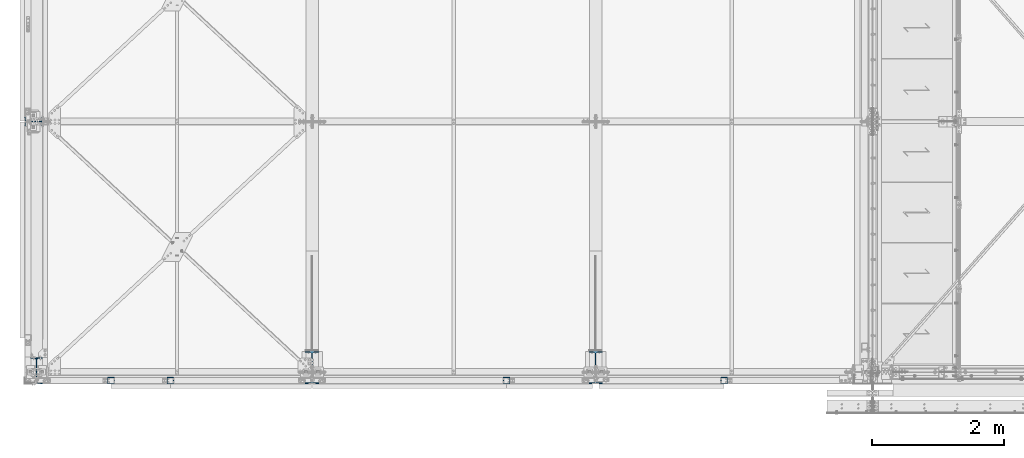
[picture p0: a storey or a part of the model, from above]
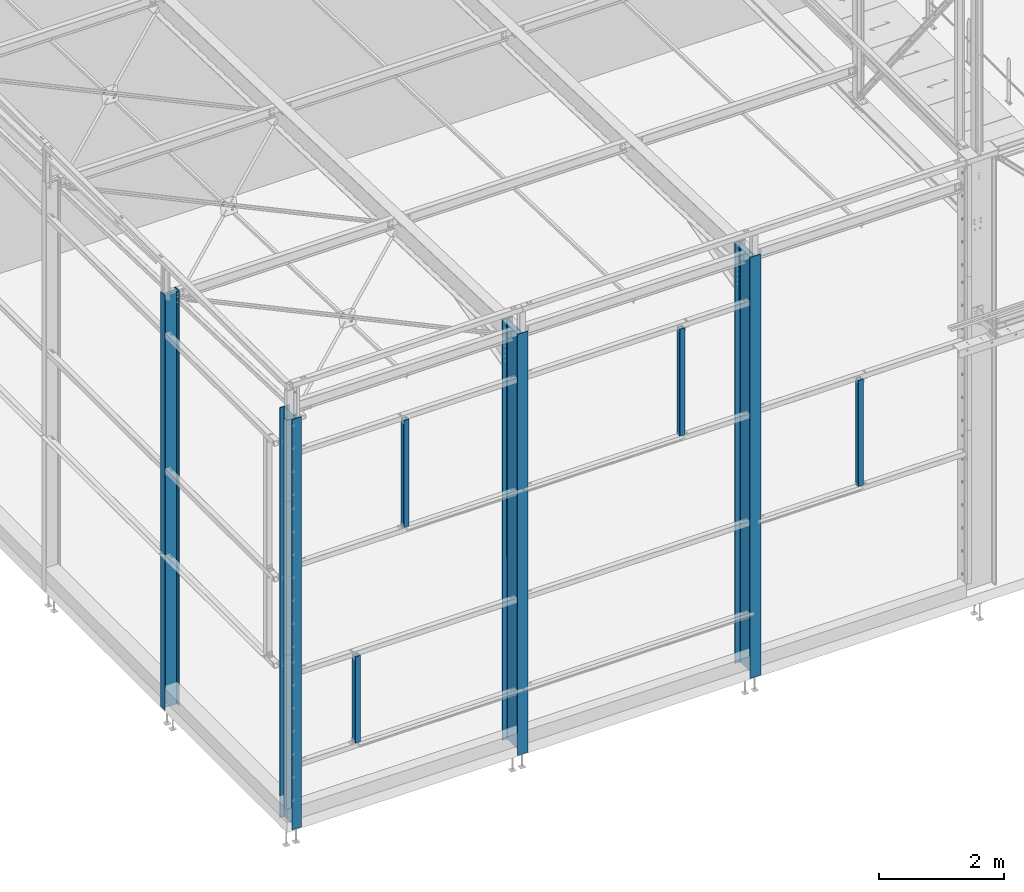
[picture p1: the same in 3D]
Properties of the parts of a building model (IFC2X3), part 1 of 4

# File
Description: ViewDefinition[CoordinationView_V2.0, QuantityTakeOffAddOnView], Option [BaseQuantities:On], Option [GridExport:Off], Option [Assemblies:On], Option [Bolts:On], Option [Rebars:On], Option [PourObjects:Off], Option [Welds:Off], Option [SurfaceTreatments:Off], Option [LocationBy:0], Option [ViewColors:On], Option [SectionedSpine:Off], Option [PropertySets:On], Option [Export all:On]
File name: Tekla.ifc
Time: 2021-06-01T16:03:29
Author: PORTCM01\professeur
Organization: Structural Designer
Written by: IFC Database Version: Work
Made in: Tekla Structures Educational 2019, IFC Export Version: 4.0.0.0 Mar 7 2019

# IfcSite, Undefined
RefElevation: 0 mm

# IfcBuildingStorey, Undefined
In: Undefined
Elevation: 0 mm

# IfcBeam: 250*200 (2)
In: Undefined
Description: 250*200; Material: CONCRETE/C25/30
Tekla Commun - Phase: 1; Profil: 250*200; Nom: POUTRE; sets with these values: 2
Tekla Quantités - Surface par tonne: 7.6 m2; Hauteur: 250 mm; Largeur: 200 mm; sets with these values: 2
Pset_BeamCommon - LoadBearing: no
Name | Repère de pièce = Repère d'assemblage = Reference | Poids (kg) = NetWeight (kg) | Volume (m3) | Surface supérieure totale (m2) | Surface nette (m2) | Longueur (mm) = Length (mm) | OuterSurfaceArea (m2) | NetVolume (m3)
POUTRE | Po9 | 1277.4 | 0.5 | 2.1 | 9.7 | 10645 | 9.6805 | 0.53225
POUTRE | Po8 | 1474.8 | 0.6 | 2.5 | 11.2 | 12290 | 11.161 | 0.6145

# IfcBeam: 250*270 (2)
In: Undefined
Description: 250*270; Material: CONCRETE/C25/30
Tekla Commun - Phase: 1; Profil: 250*270; Nom: POUTRE; sets with these values: 2
Tekla Quantités - Hauteur: 250 mm; Largeur: 270 mm; sets with these values: 2
Pset_BeamCommon - LoadBearing: no
Name | Repère de pièce = Repère d'assemblage = Reference | Poids (kg) | Volume (m3) | Surface supérieure totale (m2) | Surface par tonne (m2) | Surface nette (m2) | Longueur (mm) = Length (mm) | OuterSurfaceArea (m2) | NetVolume (m3) | NetWeight (kg)
POUTRE | Po11 | 2174.9 | 0.9 | 3.6 | 6.5 | 14.1 | 13425 | 14.097 | 0.906188 | 2174.85
POUTRE | Po10 | 81 | 0 | 0.1 | 8.1 | 0.7 | 500 | 0.655 | 0.03375 | 81

# IfcBeam: 4550*200 (2)
In: Undefined
Description: 4550*200; Material: CONCRETE/C25/30
Tekla Commun - Phase: 1; Profil: 4550*200; Nom: POUTRE; sets with these values: 2
Tekla Quantités - Hauteur: 4550 mm; Largeur: 200 mm; sets with these values: 2
Pset_BeamCommon - LoadBearing: no
Name | Repère de pièce = Repère d'assemblage = Reference | Poids (kg) = NetWeight (kg) | Volume (m3) | Surface supérieure totale (m2) | Surface par tonne (m2) | Surface nette (m2) | Longueur (mm) | Length (mm) | OuterSurfaceArea (m2) | NetVolume (m3)
POUTRE | Po5 | 29791.9 | 12.4 | 2.7 | 4.4 | 131.7 | 13733.4 | 13733.4 | 131.739 | 12.4133
POUTRE | Po4 | 20476.6 | 8.5 | 1.9 | 4.5 | 91.2 | 9478.7 | 9478.66 | 91.2034 | 8.53192

# IfcBeam: 8550*200 (5)
In: Undefined
Description: 8550*200; Material: CONCRETE/C25/30
Tekla Commun - Phase: 1; Profil: 8550*200; Nom: POUTRE; sets with these values: 2
Tekla Quantités - Hauteur: 8550 mm; Largeur: 200 mm; sets with these values: 2
Pset_BeamCommon - LoadBearing: no
Name | Repère de pièce = Repère d'assemblage = Reference | Poids (kg) = NetWeight (kg) | Volume (m3) | Surface supérieure totale (m2) | Surface par tonne (m2) | Surface nette (m2) | Longueur (mm) = Length (mm) | OuterSurfaceArea (m2) | NetVolume (m3)
POUTRE | Po7 | 37962 | 15.8 | 1.9 | 4.4 | 165.3 | 9250 | 165.295 | 15.8175
POUTRE | Po6 | 38372.4 | 16 | 1.9 | 4.4 | 167.8 | 9450 | 167.753 | 15.9885
POUTRE | Po3 | 124128 | 51.7 | 6.9 | 4.4 | 547.8 | 34778 | 547.813 | 51.7201
POUTRE | Po2 | 38782.8 | 16.2 | 1.9 | 4.4 | 170.2 | 9650 | 170.212 | 16.1595
POUTRE | Po1 | 201274 | 83.9 | 9.4 | 4.3 | 862.8 | 49248 | 862.765 | 83.8642

# IfcBeam: B140/150 (18)
In: Undefined
Description: B140/150; Material: Undefined/S235-E24
Tekla Commun - Repère de pièce: PN35; Repère d'assemblage: PN35; Phase: 1; Profil: B140/150; Nom: PANNE SHED; sets with these values: 2
Tekla Quantités - Poids: 0 kg; Volume: 0 m3; Surface supérieure totale: 0 m2; Surface par tonne: 0 m2; Surface nette: 4.6 m2; Hauteur: 140 mm; Largeur: 56 mm; Longueur: 7750 mm; sets with these values: 2
Pset_BeamCommon - LoadBearing: no; Reference: PN35
BaseQuantities - Length: 7750 mm; OuterSurfaceArea: 0.00000456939 m2; NetVolume: 0.00341 m3; NetWeight: 0 kg

# IfcBeam: D22 (22)
In: Undefined
Description: D22; Material: Undefined/S235-E24
Tekla Commun - Repère de pièce: 210; Phase: 1; Profil: D22; Nom: TIGE D'ANCRAGE; sets with these values: 2
Tekla Quantités - Poids: 0 kg; Volume: 0 m3; Surface supérieure totale: 0 m2; Surface par tonne: 0 m2; Surface nette: 0 m2; Hauteur: 22 mm; Largeur: 22 mm; Longueur: 350 mm; sets with these values: 2
Pset_BeamCommon - LoadBearing: no; Reference: 210
BaseQuantities - Length: 350 mm; OuterSurfaceArea: 0.0246409 m2; NetVolume: 0.00012705 m3; NetWeight: 0 kg
Name | Repère d'assemblage
14 x TIGE D'ANCRAGE | PS1
8 x TIGE D'ANCRAGE | PS2

# IfcBeam: D24 (22)
In: Undefined
Description: D24; Material: Undefined/S235-E24
Tekla Commun - Repère de pièce: 218; Phase: 1; Profil: D24; Nom: TIGE D'ANCRAGE; sets with these values: 2
Tekla Quantités - Poids: 0 kg; Volume: 0 m3; Surface supérieure totale: 0 m2; Surface par tonne: 0 m2; Surface nette: 0 m2; Hauteur: 24 mm; Largeur: 24 mm; Longueur: 150 mm; sets with these values: 2
Pset_BeamCommon - LoadBearing: no; Reference: 218
BaseQuantities - Length: 150 mm; OuterSurfaceArea: 0.012045 m2; NetVolume: 0.0000648 m3; NetWeight: 0 kg
Name | Repère d'assemblage
14 x TIGE D'ANCRAGE | PS1
8 x TIGE D'ANCRAGE | PS2

# IfcBeam: HEA100, BECHE
In: Undefined
Description: HEA100; Material: Undefined/S275-E28
Tekla Commun - Repère de pièce: 200; Repère d'assemblage: PS3; Phase: 1; Profil: HEA100; Nom: BECHE; sets with these values: 2
Tekla Quantités - Poids: 0 kg; Volume: 0 m3; Surface supérieure totale: 0 m2; Surface par tonne: 0 m2; Surface nette: 0.1 m2; Hauteur: 96 mm; Largeur: 100 mm; Longueur: 100 mm; sets with these values: 2
Pset_BeamCommon - LoadBearing: no; Reference: 200
BaseQuantities - Length: 100 mm; OuterSurfaceArea: 0.0561 m2; NetVolume: 0.0002 m3; NetWeight: 0 kg

# IfcBeam: HEA120 (4)
In: Undefined
Description: HEA120; Material: Undefined/S275-E28
Tekla Commun - Repère de pièce: 201; Repère d'assemblage: PS2; Phase: 1; Profil: HEA120; Nom: BECHE; sets with these values: 2
Tekla Quantités - Poids: 0 kg; Volume: 0 m3; Surface supérieure totale: 0 m2; Surface par tonne: 0 m2; Surface nette: 0.1 m2; Hauteur: 114 mm; Largeur: 120 mm; Longueur: 120 mm; sets with these values: 2
Pset_BeamCommon - LoadBearing: no; Reference: 201
BaseQuantities - Length: 120 mm; OuterSurfaceArea: 0.08124 m2; NetVolume: 0.0002892 m3; NetWeight: 0 kg

# IfcBeam: HEA140 (27)
In: Undefined
Description: HEA140; Material: Undefined/S275-E28
Tekla Commun - Phase: 1; Profil: HEA140; sets with these values: 2
Tekla Quantités - Poids: 0 kg; Volume: 0 m3; Surface par tonne: 0 m2; Hauteur: 133 mm; Largeur: 140 mm; sets with these values: 2
Pset_BeamCommon - LoadBearing: no
BaseQuantities - NetWeight: 0 kg
Name | Repère de pièce = Reference | Repère d'assemblage | Nom | Surface supérieure totale (m2) | Surface nette (m2) | Longueur (mm) = Length (mm) | OuterSurfaceArea (m2) | NetVolume (m3)
LONGERON | L43 | L43 | LONGERON | 0.5 | 2.8 | 3465 | 2.75121 | 0.0104574
12 x LONGERON | L3 | L3 | LONGERON | 0.5 | 3 | 3650 | 2.8981 | 0.0110157
6 x BECHE | 32 | PS6 | BECHE | 0 | 0.1 | 100 | 0.0794 | 0.0003018
BECHE | 33 | PS5 | BECHE | 0 | 0.1 | 125 | 0.09925 | 0.00037725
6 x BECHE | 32 | PS4 | BECHE | 0 | 0.1 | 100 | 0.0794 | 0.0003018
LONGERON | L32 | L32 | LONGERON | 1.6 | 9.4 | 11545 | 9.16673 | 0.0348428

# IfcBeam: HEA180 (2)
In: Undefined
Description: HEA180; Material: Undefined/S275-E28
Tekla Commun - Phase: 1; Profil: HEA180; Nom: LONGERON; sets with these values: 2
Tekla Quantités - Poids: 0 kg; Surface par tonne: 0 m2; Hauteur: 171 mm; Largeur: 180 mm; sets with these values: 2
Pset_BeamCommon - LoadBearing: no
BaseQuantities - NetWeight: 0 kg
Name | Repère de pièce = Repère d'assemblage = Reference | Volume (m3) | Surface supérieure totale (m2) | Surface nette (m2) | Longueur (mm) = Length (mm) | OuterSurfaceArea (m2) | NetVolume (m3)
LONGERON | L42 | 0 | 0.7 | 3.9 | 3690 | 3.77856 | 0.0159851
LONGERON | L40 | 0.1 | 2.1 | 12.1 | 11545 | 11.8221 | 0.0500129

# IfcBeam: HEA200 (6)
In: Undefined
Description: HEA200; Material: Undefined/S275-E28
Tekla Commun - Phase: 1; Profil: HEA200; sets with these values: 2
Tekla Quantités - Poids: 0 kg; Surface par tonne: 0 m2; Hauteur: 190 mm; Largeur: 200 mm; sets with these values: 2
Pset_BeamCommon - LoadBearing: no
BaseQuantities - NetWeight: 0 kg
Name | Repère de pièce = Repère d'assemblage = Reference | Nom | Volume (m3) | Surface supérieure totale (m2) | Surface nette (m2) | Longueur (mm) = Length (mm) | OuterSurfaceArea (m2) | NetVolume (m3)
LONGERON | L41 | LONGERON | 0 | 0.8 | 4.4 | 3765 | 4.27704 | 0.0192203
TRAVERSE HAUTE | TH2 | TRAVERSE HAUTE | 0 | 1.7 | 9.9 | 8515 | 9.67304 | 0.0434691
TRAVERSE BASSE | TB2 | TRAVERSE BASSE | 0 | 1.4 | 8.2 | 7055 | 8.01448 | 0.0360158
TRAVERSE HAUTE | TH1 | TRAVERSE HAUTE | 0 | 1.4 | 8.2 | 7055 | 8.01448 | 0.0360158
TRAVERSE BASSE | TB1 | TRAVERSE BASSE | 0 | 1.7 | 9.9 | 8515 | 9.67304 | 0.0434691
LONGERON | L39 | LONGERON | 0.1 | 2.3 | 13.5 | 11545 | 13.1151 | 0.0589372

# IfcBeam: IPE120 (7)
In: Undefined
Description: IPE120; Material: Undefined/S275-E28
Tekla Commun - Profil: IPE120; Nom: PANNE; sets with these values: 2
Tekla Quantités - Poids: 0 kg; Volume: 0 m3; Surface supérieure totale: 0 m2; Surface par tonne: 0 m2; Hauteur: 120 mm; Largeur: 64 mm; sets with these values: 2
Pset_BeamCommon - LoadBearing: no
BaseQuantities - NetWeight: 0 kg
Name | Repère de pièce = Repère d'assemblage = Reference | Phase | Surface nette (m2) | Longueur (mm) = Length (mm) | OuterSurfaceArea (m2) | NetVolume (m3)
PANNE | PN37 | 2 | 5.2 | 10758 | 5.11005 | 0.0137591 | Tekla Commun - Finition: GALVA
PANNE | PN36 | 2 | 5.2 | 10758 | 5.11005 | 0.0137591 | Tekla Commun - Finition: GALVA
PANNE | PN11 | 2 | 5.2 | 10758 | 5.11005 | 0.0137591 | Tekla Commun - Finition: GALVA
PANNE | PN18 | 1 | 0.6 | 1125 | 0.534375 | 0.00143883
3 x PANNE | PN10 | 1 | 0.6 | 1125 | 0.534375 | 0.00143883

# IfcBeam: IPE160 (4)
In: Undefined
Description: IPE160; Material: Undefined/S275-E28
Tekla Commun - Finition: GALVA; Phase: 2; Profil: IPE160; Nom: TRAVERSE; sets with these values: 2
Tekla Quantités - Poids: 0 kg; Volume: 0 m3; Surface supérieure totale: 0 m2; Surface par tonne: 0 m2; Surface nette: 2.6 m2; Hauteur: 160 mm; Largeur: 82 mm; Longueur: 4043.9 mm; sets with these values: 2
Pset_BeamCommon - LoadBearing: no
BaseQuantities - Length: 4043.91 mm; OuterSurfaceArea: 2.51935 m2; NetVolume: 0.0078273 m3; NetWeight: 0 kg
Name | Repère de pièce = Repère d'assemblage = Reference
2 x TRAVERSE | T8
TRAVERSE | T6
TRAVERSE | T9

# IfcBeam: IPE180 (5)
In: Undefined
Description: IPE180; Material: Undefined/S275-E28
Tekla Commun - Phase: 1; Profil: IPE180; Nom: PANNE; sets with these values: 2
Tekla Quantités - Poids: 0 kg; Volume: 0 m3; Surface supérieure totale: 0 m2; Surface par tonne: 0 m2; Hauteur: 180 mm; Largeur: 91 mm; sets with these values: 2
Pset_BeamCommon - LoadBearing: no
BaseQuantities - NetWeight: 0 kg
Name | Repère de pièce = Repère d'assemblage = Reference | Surface nette (m2) | Longueur (mm) = Length (mm) | OuterSurfaceArea (m2) | NetVolume (m3)
3 x PANNE | PN16 | 2.7 | 3733.5 | 2.60598 | 0.00868113
PANNE | PN17 | 2.7 | 3733.5 | 2.60598 | 0.00868113
PANNE | PN2 | 2.8 | 3866.5 | 2.69882 | 0.00899039

# IfcBeam: IPE200 (20)
In: Undefined
Description: IPE200
Tekla Commun - Phase: 1; Profil: IPE200; Nom: PANNE; sets with these values: 2
Tekla Quantités - Volume: 0 m3; Surface supérieure totale: 0 m2; Hauteur: 200 mm; Largeur: 100 mm; sets with these values: 2
Pset_BeamCommon - LoadBearing: no
Name | Material | Repère de pièce = Repère d'assemblage = Reference | Poids (kg) | Surface par tonne (m2) | Surface nette (m2) | Longueur (mm) = Length (mm) | OuterSurfaceArea (m2) | NetVolume (m3) | NetWeight (kg)
3 x PANNE | Undefined/S275-E28 | PN9 | 0 | 0 | 4.1 | 5213.5 | 4.00397 | 0.0142057 | 0
PANNE | Undefined/S275-E28 | PN15 | 0 | 0 | 4.1 | 5213.5 | 4.00397 | 0.0142057 | 0
PANNE | Undefined/S275-E28 | PN8 | 0 | 0 | 4 | 5075 | 3.8976 | 0.0138284 | 0
2 x PANNE | Undefined/S275-E28 | PN7 | 0 | 0 | 3.2 | 4023.5 | 3.09005 | 0.0109632 | 0
2 x PANNE | Undefined/S275-E28 | PN5 | 0 | 0 | 3.2 | 4100 | 3.1488 | 0.0111717 | 0
2 x PANNE | Undefined/S275-E28 | PN14 | 0 | 0 | 3.2 | 4023.5 | 3.09005 | 0.0109632 | 0
3 x PANNE | Undefined/S275-E28 | PN13 | 0 | 0 | 3.2 | 4100 | 3.1488 | 0.0111717 | 0
PANNE | Undefined/S275-E28 | PN6 | 0 | 0 | 3 | 3790 | 2.91072 | 0.010327 | 0
3 x PANNE | Undefined/S275-E28 | PN4 | 0 | 0 | 3.1 | 3980 | 3.05664 | 0.0108447 | 0
PANNE | Undefined/S275-E28 | PN3 | 0 | 0 | 3.3 | 4165 | 3.19872 | 0.0113488 | 0
PANNE | STEEL/S235J0 | PN12 | 93.2 | 34.3 | 3.3 | 4165 | 3.19872 | 0.0113488 | 89.088

# IfcBeam: IPE270 (2)
In: Undefined
Description: IPE270; Material: Undefined/S275-E28
Tekla Commun - Phase: 1; Profil: IPE270; sets with these values: 2
Tekla Quantités - Poids: 0 kg; Surface supérieure totale: 0 m2; Surface par tonne: 0 m2; Hauteur: 270 mm; Largeur: 135 mm; sets with these values: 2
Pset_BeamCommon - LoadBearing: no
BaseQuantities - NetWeight: 0 kg
Name | Repère de pièce = Reference | Repère d'assemblage | Nom | Volume (m3) | Surface nette (m2) | Longueur (mm) = Length (mm) | OuterSurfaceArea (m2) | NetVolume (m3)
PANNE | PN1 | PN1 | PANNE | 0 | 5.6 | 5260 | 5.47566 | 0.0231512
TRAVERSE | 11 | T3 | TRAVERSE | 0.1 | 16 | 15040.9 | 15.6576 | 0.0661631

# IfcBeam: IPE450 (3)
In: Undefined
Description: IPE450; Material: Undefined/S275-E28
Tekla Commun - Phase: 1; Profil: IPE450; Nom: TRAVERSE; sets with these values: 2
Tekla Quantités - Poids: 0 kg; Surface supérieure totale: 0 m2; Surface par tonne: 0 m2; Hauteur: 450 mm; Largeur: 190 mm; sets with these values: 2
Pset_BeamCommon - LoadBearing: no
BaseQuantities - NetWeight: 0 kg
Name | Repère de pièce = Reference | Repère d'assemblage | Volume (m3) | Surface nette (m2) | Longueur (mm) = Length (mm) | OuterSurfaceArea (m2) | NetVolume (m3)
TRAVERSE | 155 | T7 | 0.1 | 24.7 | 15046.6 | 24.1497 | 0.142861
TRAVERSE | T2 | T2 | 0.2 | 25.1 | 15291.1 | 24.5422 | 0.145252
TRAVERSE | 6 | T1 | 0.1 | 24.7 | 15046.6 | 24.1497 | 0.142861

# IfcBeam: IPE550 (2)
In: Undefined
Description: IPE550; Material: Undefined/S275-E28
Tekla Commun - Phase: 1; Profil: IPE550; Nom: TRAVERSE; sets with these values: 2
Tekla Quantités - Poids: 0 kg; Volume: 0.2 m3; Surface supérieure totale: 0 m2; Surface par tonne: 0 m2; Hauteur: 550 mm; Largeur: 210 mm; sets with these values: 2
Pset_BeamCommon - LoadBearing: no
BaseQuantities - NetWeight: 0 kg
Name | Repère de pièce = Reference | Repère d'assemblage | Surface nette (m2) | Longueur (mm) = Length (mm) | OuterSurfaceArea (m2) | NetVolume (m3)
TRAVERSE | 36 | T5 | 29.3 | 15264.8 | 28.652 | 0.197412
TRAVERSE | 35 | T4 | 29.4 | 15353.9 | 28.8192 | 0.198565

# IfcBeam: L100*10 (19)
In: Undefined
Description: L100*10; Material: Undefined/S235-E24
Tekla Commun - Phase: 1; Profil: L100*10; Nom: ATTACHE; sets with these values: 2
Tekla Quantités - Poids: 0 kg; Volume: 0 m3; Surface supérieure totale: 0 m2; Surface par tonne: 0 m2; Surface nette: 0.1 m2; Hauteur: 100 mm; Largeur: 100 mm; sets with these values: 2
Pset_BeamCommon - LoadBearing: no
BaseQuantities - NetWeight: 0 kg
Name | Repère de pièce = Reference | Repère d'assemblage | Longueur (mm) = Length (mm) | OuterSurfaceArea (m2) | NetVolume (m3)
ATTACHE | A24 | A24 | 200 | 0.078 | 0.00038
ATTACHE | A23 | A23 | 120 | 0.0468 | 0.000228
4 x ATTACHE | A19 | A19 | 200 | 0.078 | 0.00038
5 x ATTACHE | A22 | A22 | 130 | 0.0507 | 0.000247
ATTACHE | 347 | A21 | 200 | 0.078 | 0.00038
ATTACHE | 347 | A20 | 200 | 0.078 | 0.00038
2 x ATTACHE | A10 | A10 | 280 | 0.1092 | 0.000532
3 x ATTACHE | A11 | A11 | 240 | 0.0936 | 0.000456
ATTACHE | A9 | A9 | 180 | 0.0702 | 0.000342

# IfcBeam: L150*15 (10)
In: Undefined
Description: L150*15; Material: Undefined/S235-E24
Tekla Commun - Repère de pièce: A1; Repère d'assemblage: A1; Phase: 1; Profil: L150*15; Nom: ATTACHE; sets with these values: 2
Tekla Quantités - Poids: 0 kg; Volume: 0 m3; Surface supérieure totale: 0 m2; Surface par tonne: 0 m2; Surface nette: 0.1 m2; Hauteur: 150 mm; Largeur: 150 mm; Longueur: 200 mm; sets with these values: 2
Pset_BeamCommon - LoadBearing: no; Reference: A1
BaseQuantities - Length: 200 mm; OuterSurfaceArea: 0.1172 m2; NetVolume: 0.000855 m3; NetWeight: 0 kg

# IfcBeam: L200*100*10 (87)
In: Undefined
Description: L200*100*10; Material: Undefined/S235-E24
Tekla Commun - Phase: 1; Profil: L200*100*10; Nom: ATTACHE; sets with these values: 2
Tekla Quantités - Poids: 0 kg; Volume: 0 m3; Surface supérieure totale: 0 m2; Surface par tonne: 0 m2; sets with these values: 2
Pset_BeamCommon - LoadBearing: no
BaseQuantities - NetWeight: 0 kg
Name | Repère de pièce = Repère d'assemblage = Reference | Surface nette (m2) | Hauteur (mm) | Largeur (mm) | Longueur (mm) = Length (mm) | OuterSurfaceArea (m2) | NetVolume (m3)
ATTACHE | A52 | 0.1 | 150 | 100 | 100 | 0.0587 | 0.00024
ATTACHE | A50 | 0.1 | 200 | 100 | 110 | 0.06457 | 0.000319
35 x ATTACHE | A46 | 0 | 200 | 100 | 60 | 0.03522 | 0.000174
ATTACHE | A49 | 0 | 192 | 100 | 60 | 0.03522 | 0.0001692
ATTACHE | A48 | 0 | 171 | 100 | 60 | 0.03522 | 0.0001566
ATTACHE | A47 | 0.1 | 200 | 100 | 110 | 0.06457 | 0.000319
2 x ATTACHE | A56 | 0.1 | 200 | 100 | 100 | 0.0587 | 0.00029
2 x ATTACHE | A57 | 0.1 | 200 | 70 | 100 | 0.0587 | 0.00026
ATTACHE | A51 | 0.1 | 200 | 100 | 80 | 0.04696 | 0.000232
42 x ATTACHE | A44 | 0 | 200 | 100 | 60 | 0.03522 | 0.000174

# IfcBeam: L40*4 (7)
In: Undefined
Description: L40*4; Material: Undefined/S235-E24
Tekla Commun - Profil: L40*4; sets with these values: 2
Tekla Quantités - Poids: 0 kg; Volume: 0 m3; Surface supérieure totale: 0 m2; Surface par tonne: 0 m2; Hauteur: 40 mm; Largeur: 40 mm; sets with these values: 2
Pset_BeamCommon - LoadBearing: no
BaseQuantities - NetWeight: 0 kg
Name | Finition | Repère de pièce = Repère d'assemblage = Reference | Phase | Nom | Surface nette (m2) | Longueur (mm) | Length (mm) | OuterSurfaceArea (m2) | NetVolume (m3)
4 x STABILITE CVT | GALVA | S15 | 2 | STABILITE CVT | 0.4 | 2209.6 | 2209.65 | 0.342495 | 0.000672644
3 x ATTACHE |  | A14 | 1 | ATTACHE | 0 | 120 | 120 | 0.0186 | 0.00003648

# IfcBeam: L50*5 (64)
In: Undefined
Description: L50*5
Tekla Commun - Profil: L50*5; sets with these values: 2
Tekla Quantités - Poids: 0 kg; Volume: 0 m3; Surface par tonne: 0 m2; Hauteur: 50 mm; Largeur: 50 mm; sets with these values: 2
Pset_BeamCommon - LoadBearing: no
BaseQuantities - NetWeight: 0 kg
Name | Material | Repère de pièce = Reference | Repère d'assemblage | Phase | Nom | Surface supérieure totale (m2) | Surface nette (m2) | Longueur (mm) | Length (mm) | OuterSurfaceArea (m2) | NetVolume (m3)
SUPPORT | Undefined/S235-E24 | S51 | S51 | 3 | SUPPORT | 0.3 | 1.1 | 5660 | 5660 | 1.09804 | 0.0026885 | Tekla Commun - Finition: GALVA
SUPPORT | Undefined/S235-E24 | S33 | S33 | 3 | SUPPORT | 0.3 | 1.1 | 5600 | 5600 | 1.0864 | 0.00266 | Tekla Commun - Finition: GALVA
3 x SUPPORT | Undefined/S235-E24 | S54 | S54 | 3 | SUPPORT | 0 | 0.1 | 705 | 705 | 0.13677 | 0.000334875 | Tekla Commun - Finition: GALVA
3 x SUPPORT | Undefined/S235-E24 | S53 | S53 | 3 | SUPPORT | 0 | 0.1 | 705 | 705 | 0.13677 | 0.000334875 | Tekla Commun - Finition: GALVA
SUPPORT | Undefined/S235-E24 | S25 | S25 | 3 | SUPPORT | 0.3 | 1.1 | 5660 | 5660 | 1.09804 | 0.0026885 | Tekla Commun - Finition: GALVA
4 x SUPPORT | Undefined/S235-E24 | S35 | S35 | 3 | SUPPORT | 0.1 | 0.4 | 2010 | 2010 | 0.38994 | 0.00095475 | Tekla Commun - Finition: GALVA
2 x SUPPORT | Undefined/S235-E24 | S52 | S52 | 3 | SUPPORT | 0 | 0.2 | 960 | 959.999 | 0.18624 | 0.000456 | Tekla Commun - Finition: GALVA
2 x SUPPORT | Undefined/S235-E24 | S36 | S36 | 3 | SUPPORT | 0 | 0.2 | 840 | 840 | 0.16296 | 0.000399 | Tekla Commun - Finition: GALVA
SUPPORT | Undefined/S235-E24 | S41 | S41 | 3 | SUPPORT | 0.3 | 1.1 | 5600 | 5600 | 1.0864 | 0.00266 | Tekla Commun - Finition: GALVA
2 x LIERNE | Undefined/S235-E24 | L79 | L79 | 1 | LIERNE | 0 | 0.8 | 3874.7 | 3874.7 | 0.751691 | 0.00184143
2 x LIERNE | Undefined/S235-E24 | L78 | L78 | 1 | LIERNE | 0 | 0.9 | 4309.7 | 4309.66 | 0.836074 | 0.00204804
LIERNE | Undefined/S235-E24 | L83 | L83 | 1 | LIERNE | 0 | 1.5 | 7646.8 | 7646.75 | 1.48347 | 0.00363316
3 x LIERNE | Undefined/S235-E24 | L80 | L80 | 1 | LIERNE | 0 | 1.5 | 7646.8 | 7646.75 | 1.48347 | 0.00363316
LIERNE | Undefined/S235-E24 | L82 | L82 | 1 | LIERNE | 0 | 1.5 | 7642.3 | 7642.25 | 1.4826 | 0.00363102
LIERNE | Undefined/S235-E24 | L81 | L81 | 1 | LIERNE | 0 | 1.5 | 7400 | 7399.96 | 1.43559 | 0.00351593
STABILITE CVT | Undefined/S235-E24 | S39 | S39 | 1 | STABILITE CVT | 0 | 0.5 | 2596.8 | 2596.85 | 0.503789 | 0.00123493
STABILITE CVT | Undefined/S235-E24 | S40 | S40 | 1 | STABILITE CVT | 0 | 0.5 | 2535 | 2535.02 | 0.491794 | 0.00120556
2 x LIERNE | Undefined/S235-E24 | L84 | L84 | 1 | LIERNE | 0 | 1.5 | 7646.8 | 7646.75 | 1.48347 | 0.00363316
5 x STABILITE CVT | Undefined/S235-E24 | S9 | S9 | 1 | STABILITE CVT | 0 | 0.5 | 2519.7 | 2519.71 | 0.488823 | 0.00119829
LIERNE | Undefined/S235-E24 | L86 | L86 | 1 | LIERNE | 0 | 1.5 | 7646.8 | 7646.75 | 1.48347 | 0.00363316
LIERNE | Undefined/S235-E24 | L85 | L85 | 1 | LIERNE | 0 | 1.5 | 7646.8 | 7646.75 | 1.48347 | 0.00363316
2 x STABILITE CVT | Undefined/S235-E24 | S38 | S38 | 1 | STABILITE CVT | 0 | 1.1 | 5256.2 | 5256.19 | 1.0197 | 0.00249812
2 x STABILITE CVT | Undefined/S235-E24 | S9 | S9 | 1 | STABILITE CVT | 0 | 0.5 | 2519.7 | 2519.7 | 0.488822 | 0.00119828
3 x SUPPORT | Undefined/S235-E24 | S37 | S37 | 1 | SUPPORT | 0.4 | 1.5 | 7470 | 7470 | 1.44918 | 0.00354825
3 x SUPPORT | Undefined/S235-E24 | S13 | S13 | 1 | SUPPORT | 0.4 | 1.5 | 7675 | 7675 | 1.48895 | 0.00364563
8 x STABILITE CVT | Undefined/S235-E24 | S8 | S8 | 1 | STABILITE CVT | 0 | 0.8 | 4071 | 4071.04 | 0.789781 | 0.00193469
STABILITE CVT | Undefined/S235-E24 | S40 | S40 | 1 | STABILITE CVT | 0 | 0.5 | 2535 | 2535.03 | 0.491796 | 0.00120556
STABILITE CVT | Undefined/S235-E24 | S12 | S12 | 1 | STABILITE CVT | 0 | 1.1 | 5283.1 | 5283.05 | 1.02491 | 0.00251087
STABILITE CVT | Undefined/S235-E24 | S39 | S39 | 1 | STABILITE CVT | 0 | 0.5 | 2596.9 | 2596.86 | 0.50379 | 0.00123493
STABILITE CVT | Undefined/S235-E24 | S11 | S11 | 1 | STABILITE CVT | 0 | 1.1 | 5406.7 | 5406.7 | 1.0489 | 0.00256961
STABILITE CVT | Undefined/S235-E24 | S38 | S38 | 1 | STABILITE CVT | 0 | 1.1 | 5256.2 | 5256.19 | 1.0197 | 0.00249811
STABILITE CVT | Undefined/S235-E24 | S9 | S9 | 1 | STABILITE CVT | 0 | 0.5 | 2519.7 | 2519.69 | 0.488821 | 0.00119828
STABILITE CVT | STEEL/S235 -------------- | S38 | S38(?) | 1 | STABILITE CVT | 0 | 1.1 | 5311.3 | 5311.31 | 1.03039 | 0.00252429

# IfcBeam: L60*5 (2)
In: Undefined
Description: L60*5; Material: STEEL/S235 --------------
Tekla Commun - Repère de pièce: S0; Repère d'assemblage: S0(?); Phase: 1; Profil: L60*5; Nom: CORNIERE; sets with these values: 2
Tekla Quantités - Poids: 0 kg; Volume: 0 m3; Surface supérieure totale: 0 m2; Surface par tonne: 0 m2; Surface nette: 0 m2; Hauteur: 60 mm; Largeur: 60 mm; sets with these values: 2
Pset_BeamCommon - LoadBearing: no; Reference: S0
BaseQuantities - NetWeight: 0 kg
Name | Longueur (mm) | Length (mm) | OuterSurfaceArea (m2) | NetVolume (m3)
CORNIERE | 107 | 106.997 | 0.0249304 | 0.0000632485
CORNIERE | 107.2 | 107.192 | 0.0249758 | 0.0000633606

# IfcBeam: L60*6 (59)
In: Undefined
Description: L60*6; Material: Undefined/S235-E24
Tekla Commun - Profil: L60*6; sets with these values: 2
Tekla Quantités - Poids: 0 kg; Volume: 0 m3; Surface supérieure totale: 0 m2; Surface par tonne: 0 m2; Hauteur: 60 mm; Largeur: 60 mm; sets with these values: 2
Pset_BeamCommon - LoadBearing: no
BaseQuantities - NetWeight: 0 kg
Name | Repère de pièce = Repère d'assemblage = Reference | Phase | Nom | Surface nette (m2) | Longueur (mm) | Length (mm) | OuterSurfaceArea (m2) | NetVolume (m3)
14 x ATTACHE | A29 | 3 | ATTACHE | 0 | 120 | 120 | 0.02796 | 0.00008208 | Tekla Commun - Finition: GALVA
2 x ATTACHE | A45 | 3 | ATTACHE | 0 | 180 | 180 | 0.04194 | 0.00012312 | Tekla Commun - Finition: GALVA
3 x ATTACHE | A26 | 1 | ATTACHE | 0 | 150 | 150 | 0.03495 | 0.0001026
5 x STABILITE CVT | S7 | 1 | STABILITE CVT | 1.1 | 4471.9 | 4471.95 | 1.04196 | 0.00306018
3 x STABILITE CVT | S7 | 1 | STABILITE CVT | 1.1 | 4472 | 4471.95 | 1.04196 | 0.00306018
7 x STABILITE CVT | S6 | 1 | STABILITE CVT | 1.2 | 5017.9 | 5017.95 | 1.16918 | 0.00343364
16 x ATTACHE | A25 | 1 | ATTACHE | 0 | 200 | 200 | 0.0466 | 0.0001368
6 x STABILITE CVT | S30 | 1 | STABILITE CVT | 0.8 | 3399.5 | 3399.54 | 0.792092 | 0.00232734
2 x STABILITE CVT | S31 | 1 | STABILITE CVT | 0.8 | 3279.5 | 3279.54 | 0.764132 | 0.00224525
STABILITE CVT | S6 | 1 | STABILITE CVT | 1.2 | 5017.9 | 5017.94 | 1.16918 | 0.00343364

# IfcBeam: L70*7 (66)
In: Undefined
Description: L70*7; Material: Undefined/S235-E24
Tekla Commun - Phase: 1; Profil: L70*7; sets with these values: 2
Tekla Quantités - Poids: 0 kg; Volume: 0 m3; Surface par tonne: 0 m2; Hauteur: 70 mm; Largeur: 70 mm; sets with these values: 2
Pset_BeamCommon - LoadBearing: no
BaseQuantities - NetWeight: 0 kg
Name | Repère de pièce = Reference | Repère d'assemblage | Nom | Surface supérieure totale (m2) | Surface nette (m2) | Longueur (mm) | Length (mm) | OuterSurfaceArea (m2) | NetVolume (m3)
SUPPORT | S10 | S10 | SUPPORT | 0 | 1.9 | 6735 | 6735 | 1.83192 | 0.00627028
SUPPORT | S32 | S32 | SUPPORT | 0.1 | 2.3 | 8195 | 8195 | 2.22904 | 0.00762954
SUPPORT | 495 | L25 | SUPPORT | 0.2 | 0.6 | 2155 | 2155 | 0.586159 | 0.0020063
SUPPORT | 494 | L55 | SUPPORT | 0.2 | 0.8 | 2940 | 2940 | 0.799681 | 0.00273714
SUPPORT | 493 | L2 | SUPPORT | 0.3 | 1.2 | 4240 | 4240 | 1.15328 | 0.00394744
12 x ATTACHE | A37 | A37 | ATTACHE | 0 | 0 | 140 | 140 | 0.03808 | 0.00013034
ATTACHE | A31 | A31 | ATTACHE | 0 | 0.1 | 180 | 180 | 0.04896 | 0.00016758
8 x ATTACHE | A30 | A30 | ATTACHE | 0 | 0 | 100 | 100 | 0.0272 | 0.0000931
ATTACHE | A36 | A36 | ATTACHE | 0 | 0 | 150 | 150 | 0.0408 | 0.00013965
6 x ATTACHE | A35 | A35 | ATTACHE | 0 | 0 | 130 | 130.004 | 0.0353611 | 0.000121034
4 x ATTACHE | A34 | A34 | ATTACHE | 0 | 0 | 160 | 160 | 0.04352 | 0.00014896
ATTACHE | A33 | A33 | ATTACHE | 0 | 0 | 160 | 160 | 0.04352 | 0.00014896
SUPPORT | 380 | L29 | SUPPORT | 0.1 | 0.5 | 1900 | 1900 | 0.516799 | 0.0017689
SUPPORT | 379 | L24 | SUPPORT | 0.3 | 1.3 | 4625 | 4625 | 1.258 | 0.00430587
SUPPORT | 378 | L58 | SUPPORT | 0.2 | 0.8 | 3000 | 3000 | 0.815999 | 0.002793
SUPPORT | 380 | L23 | SUPPORT | 0.1 | 0.5 | 1900 | 1900 | 0.516799 | 0.0017689
SUPPORT | 377 | L21 | SUPPORT | 0.2 | 0.9 | 3040 | 3040 | 0.82688 | 0.00283024
SUPPORT | 376 | L52 | SUPPORT | 0.1 | 0.6 | 2140 | 2140.01 | 0.582081 | 0.00199234
18 x ATTACHE | A32 | A32 | ATTACHE | 0 | 0 | 100 | 100 | 0.0272 | 0.0000931
2 x LISSE CHASSIS | 375 | L4 | LISSE CHASSIS | 0.3 | 1.1 | 3780 | 3780 | 1.02816 | 0.00351918
LISSE CHASSIS | 374 | L18 | LISSE CHASSIS | 0.2 | 1 | 3530 | 3530 | 0.96016 | 0.00326879
LISSE CHASSIS | 373 | L20 | LISSE CHASSIS | 0.2 | 0.9 | 3270 | 3270.01 | 0.889443 | 0.00304438

# IfcBeam: L80*8 (38)
In: Undefined
Description: L80*8; Material: Undefined/S235-E24
Tekla Commun - Phase: 1; Profil: L80*8; Nom: ATTACHE; sets with these values: 2
Tekla Quantités - Poids: 0 kg; Volume: 0 m3; Surface supérieure totale: 0 m2; Surface par tonne: 0 m2; Hauteur: 80 mm; Largeur: 80 mm; sets with these values: 2
Pset_BeamCommon - LoadBearing: no
BaseQuantities - NetWeight: 0 kg
Name | Repère de pièce = Repère d'assemblage = Reference | Surface nette (m2) | Longueur (mm) = Length (mm) | OuterSurfaceArea (m2) | NetVolume (m3)
14 x ATTACHE | A78 | 0 | 100 | 0.0311 | 0.0001216
14 x ATTACHE | A79 | 0.1 | 200 | 0.0622 | 0.0002432
2 x ATTACHE | A18 | 0 | 100 | 0.0311 | 0.0001216
4 x ATTACHE | A15 | 0 | 120 | 0.03732 | 0.00014592
3 x ATTACHE | A17 | 0 | 120 | 0.03732 | 0.00014592
ATTACHE | A8 | 0 | 120 | 0.03732 | 0.00014592

# IfcBeam: PL1*1065 (3)
In: Undefined
Description: PL1*1065; Material: Undefined/S235-E24
Tekla Commun - Finition: X; Repère de pièce: C5; Phase: 3; Profil: PL1*1065; Nom: COIFFE; sets with these values: 2
Tekla Quantités - Poids: 0 kg; Volume: 0 m3; Surface supérieure totale: 0 m2; Surface par tonne: 0 m2; Surface nette: 0.5 m2; Hauteur: 1065 mm; Largeur: 1 mm; Longueur: 229.1 mm; sets with these values: 2
Pset_BeamCommon - LoadBearing: no; Reference: C5
BaseQuantities - Length: 229.098 mm; OuterSurfaceArea: 0.505241 m2; NetVolume: 0.000251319 m3; NetWeight: 0 kg
Name | Repère d'assemblage
COIFFE | C5(?)
2 x COIFFE | C5

# IfcBeam: PL1*20000 (2)
In: Undefined
Description: PL1*20000; Material: Undefined/S235-E24
Tekla Commun - Repère de pièce: X1; Repère d'assemblage: X1; Phase: 2; Profil: PL1*20000; Nom: BAVETTE; sets with these values: 2
Tekla Quantités - Poids: 0 kg; Volume: 0 m3; Surface supérieure totale: 0 m2; Surface par tonne: 0 m2; Surface nette: 7 m2; Hauteur: 20000 mm; Largeur: 1 mm; Longueur: 167.9 mm; sets with these values: 2
Pset_BeamCommon - LoadBearing: no; Reference: X1
BaseQuantities - Length: 167.904 mm; OuterSurfaceArea: 7.03146 m2; NetVolume: 0.00349555 m3; NetWeight: 0 kg

# IfcBeam: PL1*283 (2)
In: Undefined
Description: PL1*283; Material: Undefined/S235-E24
Pset_BeamCommon - LoadBearing: no; Reference: C0
Tekla Commun - Finition: X; Repère de pièce: C0; Repère d'assemblage: C0(?); Phase: 3; Profil: PL1*283; Nom: COIFFE; sets with these values: 2
Tekla Quantités - Poids: 0 kg; Volume: 0 m3; Surface supérieure totale: 0 m2; Surface par tonne: 0 m2; Surface nette: 0.1 m2; Hauteur: 283 mm; Largeur: 1 mm; Longueur: 233.1 mm; sets with these values: 2
BaseQuantities - Length: 233.121 mm; OuterSurfaceArea: 0.133542 m2; NetVolume: 0.0000662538 m3; NetWeight: 0 kg

# IfcBeam: PL1*3000 (2)
In: Undefined
Description: PL1*3000; Material: Undefined/S235-E24
Tekla Commun - Finition: X; Phase: 3; Profil: PL1*3000; Nom: COIFFE; sets with these values: 2
Tekla Quantités - Poids: 0 kg; Volume: 0 m3; Surface supérieure totale: 0 m2; Surface par tonne: 0 m2; Hauteur: 3000 mm; Largeur: 1 mm; sets with these values: 2
Pset_BeamCommon - LoadBearing: no
BaseQuantities - NetWeight: 0 kg
Name | Repère de pièce = Reference | Repère d'assemblage | Surface nette (m2) | Longueur (mm) | Length (mm) | OuterSurfaceArea (m2) | NetVolume (m3)
COIFFE | C8 | C8(?) | 4.4 | 718.7 | 718.69 | 4.3618 | 0.00217718
COIFFE | C7 | C7(?) | 4.7 | 788.7 | 788.68 | 4.70364 | 0.00234807

# IfcBeam: PL1*3045, COIFFE
In: Undefined
Description: PL1*3045; Material: Undefined/S235-E24
Pset_BeamCommon - LoadBearing: no; Reference: C4
Tekla Commun - Finition: X; Repère de pièce: C4; Repère d'assemblage: C4(?); Phase: 3; Profil: PL1*3045; Nom: COIFFE; sets with these values: 2
Tekla Quantités - Poids: 0 kg; Volume: 0 m3; Surface supérieure totale: 0 m2; Surface par tonne: 0 m2; Surface nette: 4 m2; Hauteur: 3045 mm; Largeur: 1 mm; Longueur: 653.7 mm; sets with these values: 2
BaseQuantities - Length: 653.71 mm; OuterSurfaceArea: 4.03135 m2; NetVolume: 0.00201197 m3; NetWeight: 0 kg

# IfcBeam: PL1*3585, COIFFE
In: Undefined
Description: PL1*3585; Material: Undefined/S235-E24
Pset_BeamCommon - LoadBearing: no; Reference: C0
Tekla Commun - Finition: X; Repère de pièce: C0; Repère d'assemblage: C0(?); Phase: 3; Profil: PL1*3585; Nom: COIFFE; sets with these values: 2
Tekla Quantités - Poids: 0 kg; Volume: 0 m3; Surface supérieure totale: 0 m2; Surface par tonne: 0 m2; Surface nette: 1.7 m2; Hauteur: 3585 mm; Largeur: 1 mm; Longueur: 233.1 mm; sets with these values: 2
BaseQuantities - Length: 233.121 mm; OuterSurfaceArea: 1.68622 m2; NetVolume: 0.000839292 m3; NetWeight: 0 kg

# IfcBeam: PL1*419, COIFFE
In: Undefined
Description: PL1*419; Material: Undefined/S235-E24
Tekla Commun - Finition: X; Repère de pièce: C0; Repère d'assemblage: C0(?); Phase: 3; Profil: PL1*419; Nom: COIFFE; sets with these values: 2
Tekla Quantités - Poids: 0 kg; Volume: 0 m3; Surface supérieure totale: 0 m2; Surface par tonne: 0 m2; Surface nette: 0.2 m2; Hauteur: 419 mm; Largeur: 1 mm; Longueur: 233.1 mm; sets with these values: 2
Pset_BeamCommon - LoadBearing: no; Reference: C0
BaseQuantities - Length: 233.121 mm; OuterSurfaceArea: 0.197492 m2; NetVolume: 0.000098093 m3; NetWeight: 0 kg

# IfcBeam: PL1*4540, COIFFE
In: Undefined
Description: PL1*4540; Material: Undefined/S235-E24
Tekla Commun - Finition: X; Repère de pièce: C4; Repère d'assemblage: C4(?); Phase: 3; Profil: PL1*4540; Nom: COIFFE; sets with these values: 2
Tekla Quantités - Poids: 0 kg; Volume: 0 m3; Surface supérieure totale: 0 m2; Surface par tonne: 0 m2; Surface nette: 6 m2; Hauteur: 4540 mm; Largeur: 1 mm; Longueur: 653.7 mm; sets with these values: 2
Pset_BeamCommon - LoadBearing: no; Reference: C4
BaseQuantities - Length: 653.71 mm; OuterSurfaceArea: 6.00997 m2; NetVolume: 0.00299978 m3; NetWeight: 0 kg

# IfcBeam: PL1*4921.5, COIFFE
In: Undefined
Description: PL1*4921.5; Material: Undefined/S235-E24
Pset_BeamCommon - LoadBearing: no; Reference: C0
Tekla Commun - Finition: X; Repère de pièce: C0; Repère d'assemblage: C0(?); Phase: 3; Profil: PL1*4921.5; Nom: COIFFE; sets with these values: 2
Tekla Quantités - Poids: 0 kg; Volume: 0 m3; Surface supérieure totale: 0 m2; Surface par tonne: 0 m2; Surface nette: 2.3 m2; Hauteur: 4921.5 mm; Largeur: 1 mm; Longueur: 233.1 mm; sets with these values: 2
BaseQuantities - Length: 233.121 mm; OuterSurfaceArea: 2.31468 m2; NetVolume: 0.00115218 m3; NetWeight: 0 kg

# IfcBeam: PL1*6000, COIFFE
In: Undefined
Description: PL1*6000; Material: Undefined/S235-E24
Tekla Commun - Finition: X; Repère de pièce: C6; Repère d'assemblage: C6; Phase: 3; Profil: PL1*6000; Nom: COIFFE; sets with these values: 2
Tekla Quantités - Poids: 0 kg; Volume: 0 m3; Surface supérieure totale: 0 m2; Surface par tonne: 0 m2; Surface nette: 6.9 m2; Hauteur: 6000 mm; Largeur: 1 mm; Longueur: 698.7 mm; sets with these values: 2
Pset_BeamCommon - LoadBearing: no; Reference: C6
BaseQuantities - Length: 698.693 mm; OuterSurfaceArea: 6.90223 m2; NetVolume: 0.00344446 m3; NetWeight: 0 kg

# IfcBeam: PL10*100, PLAT
In: Undefined
Description: PL10*100; Material: Undefined/S235-E24
Tekla Commun - Repère de pièce: 119; Repère d'assemblage: PS3; Phase: 1; Profil: PL10*100; Nom: PLAT; sets with these values: 2
Tekla Quantités - Poids: 0 kg; Volume: 0 m3; Surface supérieure totale: 0 m2; Surface par tonne: 0 m2; Surface nette: 0 m2; Hauteur: 100 mm; Largeur: 10 mm; Longueur: 96 mm; sets with these values: 2
Pset_BeamCommon - LoadBearing: no; Reference: 119
BaseQuantities - Length: 96 mm; OuterSurfaceArea: 0.02312 m2; NetVolume: 0.000096 m3; NetWeight: 0 kg

# IfcBeam: PL10*110 (6)
In: Undefined
Description: PL10*110; Material: Undefined/S235-E24
Tekla Commun - Phase: 1; Profil: PL10*110; Nom: RAIDISSEUR; sets with these values: 2
Tekla Quantités - Poids: 0 kg; Volume: 0 m3; Surface supérieure totale: 0 m2; Surface par tonne: 0 m2; Surface nette: 0.1 m2; Hauteur: 110 mm; Largeur: 10 mm; sets with these values: 2
Pset_BeamCommon - LoadBearing: no
BaseQuantities - NetWeight: 0 kg
Name | Repère de pièce = Reference | Repère d'assemblage | Longueur (mm) | Length (mm) | OuterSurfaceArea (m2) | NetVolume (m3)
4 x RAIDISSEUR | 111 | S1 | 547.7 | 547.663 | 0.0839134 | 0.000358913
2 x RAIDISSEUR | 112 | S2 | 447.6 | 447.613 | 0.0689904 | 0.000294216

# IfcBeam: PL10*120 (8)
In: Undefined
Description: PL10*120; Material: Undefined/S235-E24
Tekla Commun - Repère de pièce: E3; Repère d'assemblage: E3; Phase: 1; Profil: PL10*120; Nom: ECLISSE; sets with these values: 2
Tekla Quantités - Poids: 0 kg; Volume: 0 m3; Surface supérieure totale: 0 m2; Surface par tonne: 0 m2; Surface nette: 0.1 m2; Hauteur: 120 mm; Largeur: 10 mm; Longueur: 410 mm; sets with these values: 2
Pset_BeamCommon - LoadBearing: no; Reference: E3
BaseQuantities - Length: 410 mm; OuterSurfaceArea: 0.109 m2; NetVolume: 0.000492 m3; NetWeight: 0 kg

# IfcBeam: PL10*133 (19)
In: Undefined
Description: PL10*133; Material: Undefined/S235-E24
Tekla Commun - Phase: 1; Profil: PL10*133; sets with these values: 2
Tekla Quantités - Poids: 0 kg; Volume: 0 m3; Surface par tonne: 0 m2; Hauteur: 133 mm; Largeur: 10 mm; sets with these values: 2
Pset_BeamCommon - LoadBearing: no
BaseQuantities - NetWeight: 0 kg
Name | Repère de pièce = Reference | Repère d'assemblage | Nom | Surface supérieure totale (m2) | Surface nette (m2) | Longueur (mm) | Length (mm) | OuterSurfaceArea (m2) | NetVolume (m3)
PLATINE | 279 | M36 | PLATINE | 0 | 0 | 146.1 | 146.069 | 0.0444358 | 0.000194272
PLATINE | 288 | M34 | PLATINE | 0 | 0.1 | 200 | 200 | 0.05986 | 0.000266
PLATINE | 288 | M29 | PLATINE | 0 | 0.1 | 200 | 200 | 0.05986 | 0.000266
PLATINE | 289 | M7 | PLATINE | 0 | 0.1 | 180 | 180 | 0.05414 | 0.0002394
3 x ECLISSE | E4 | E4 | ECLISSE | 0.1 | 0.1 | 410 | 410 | 0.11992 | 0.0005453
PLATINE | 288 | M3 | PLATINE | 0 | 0.1 | 200 | 200 | 0.05986 | 0.000266
PLATINE | 288 | M5 | PLATINE | 0 | 0.1 | 200 | 200 | 0.05986 | 0.000266
PLATINE | 288 | M33 | PLATINE | 0 | 0.1 | 200 | 200 | 0.05986 | 0.000266
PLATINE | 288 | M28 | PLATINE | 0 | 0.1 | 200 | 200 | 0.05986 | 0.000266
PLATINE | 288 | M27 | PLATINE | 0 | 0.1 | 200 | 200 | 0.05986 | 0.000266
PLATINE | 295 | M8 | PLATINE | 0.1 | 0.1 | 410 | 410 | 0.11992 | 0.0005453
PLATINE | 288 | M26 | PLATINE | 0 | 0.1 | 200 | 200 | 0.05986 | 0.000266
PLATINE | 295 | M6 | PLATINE | 0.1 | 0.1 | 410 | 410 | 0.11992 | 0.0005453
PLATINE | 288 | M24 | PLATINE | 0 | 0.1 | 200 | 200 | 0.05986 | 0.000266
PLATINE | 295 | M4 | PLATINE | 0.1 | 0.1 | 410 | 410 | 0.11992 | 0.0005453
PLATINE | 288 | M30 | PLATINE | 0 | 0.1 | 200 | 200 | 0.05986 | 0.000266
PLATINE | 288 | M25 | PLATINE | 0 | 0.1 | 200 | 200 | 0.05986 | 0.000266

# IfcBeam: PL10*135 (3)
In: Undefined
Description: PL10*135; Material: Undefined/S235-E24
Tekla Commun - Phase: 1; Profil: PL10*135; sets with these values: 2
Tekla Quantités - Poids: 0 kg; Volume: 0 m3; Surface supérieure totale: 0 m2; Surface par tonne: 0 m2; Hauteur: 135 mm; Largeur: 10 mm; sets with these values: 2
Pset_BeamCommon - LoadBearing: no
BaseQuantities - NetWeight: 0 kg
Name | Repère de pièce = Reference | Repère d'assemblage | Nom | Surface nette (m2) | Longueur (mm) | Length (mm) | OuterSurfaceArea (m2) | NetVolume (m3)
JARRET | 273 | T3 | JARRET | 0.5 | 1549.7 | 1549.71 | 0.452116 | 0.00209211
ATTACHE | A7 | A7 | ATTACHE | 0.1 | 180.6 | 180.619 | 0.0578897 | 0.000256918
COIFFE | 135 | PT4 | COIFFE | 0.1 | 484.2 | 484.239 | 0.143129 | 0.000653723

# IfcBeam: PL10*140 (29)
In: Undefined
Description: PL10*140; Material: Undefined/S235-E24
Tekla Commun - Phase: 1; Profil: PL10*140; sets with these values: 2
Tekla Quantités - Poids: 0 kg; Volume: 0 m3; Surface supérieure totale: 0 m2; Surface par tonne: 0 m2; Hauteur: 140 mm; Largeur: 10 mm; sets with these values: 2
Pset_BeamCommon - LoadBearing: no
BaseQuantities - NetWeight: 0 kg
Name | Repère de pièce = Reference | Repère d'assemblage | Nom | Surface nette (m2) | Longueur (mm) | Length (mm) | OuterSurfaceArea (m2) | NetVolume (m3)
ATTACHE | A4 | A4 | ATTACHE | 0.1 | 239.4 | 239.362 | 0.0668841 | 0.000299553
ATTACHE | A3 | A3 | ATTACHE | 0.1 | 240.6 | 240.619 | 0.0670727 | 0.000300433
PLATINE | 284 | TS9 | PLATINE | 0.1 | 213.4 | 213.395 | 0.0668184 | 0.000298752
PLATINE | 283 | TS4 | PLATINE | 0.1 | 215.7 | 215.685 | 0.0675054 | 0.000301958
PLATINE | 284 | TS8 | PLATINE | 0.1 | 213.4 | 213.395 | 0.0668184 | 0.000298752
PLATINE | 283 | TS3 | PLATINE | 0.1 | 215.7 | 215.685 | 0.0675054 | 0.000301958
PLATINE | 284 | TS7 | PLATINE | 0.1 | 213.4 | 213.395 | 0.0668184 | 0.000298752
PLATINE | 283 | TS2 | PLATINE | 0.1 | 215.7 | 215.685 | 0.0675054 | 0.000301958
PLATINE | 284 | TS6 | PLATINE | 0.1 | 213.4 | 213.395 | 0.0668184 | 0.000298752
PLATINE | 283 | TS1 | PLATINE | 0.1 | 215.7 | 215.685 | 0.0675054 | 0.000301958
PLATINE | 284 | TS10 | PLATINE | 0.1 | 213.4 | 213.395 | 0.0668184 | 0.000298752
PLATINE | 283 | TS5 | PLATINE | 0.1 | 215.7 | 215.685 | 0.0675054 | 0.000301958
PLATINE | 286 | TS15 | PLATINE | 0.1 | 259.8 | 259.795 | 0.0807386 | 0.000363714
PLATINE | 286 | TS13 | PLATINE | 0.1 | 259.8 | 259.795 | 0.0807386 | 0.000363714
PLATINE | 286 | TS12 | PLATINE | 0.1 | 259.8 | 259.795 | 0.0807386 | 0.000363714
PLATINE | 286 | TS11 | PLATINE | 0.1 | 259.8 | 259.795 | 0.0807386 | 0.000363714
PLATINE | 286 | TS14 | PLATINE | 0.1 | 259.8 | 259.795 | 0.0807386 | 0.000363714
6 x PLAT | 129 | PS6 | PLAT | 0 | 133 | 133 | 0.0427 | 0.0001862
6 x PLAT | 129 | PS4 | PLAT | 0 | 133 | 133 | 0.0427 | 0.0001862

# IfcBeam: PL10*141 (2)
In: Undefined
Description: PL10*141; Material: Undefined/S235-E24
Tekla Commun - Finition: GALVA; Repère de pièce: 496; Repère d'assemblage: G11; Phase: 2; Profil: PL10*141; Nom: GOUSSET; sets with these values: 2
Tekla Quantités - Poids: 0 kg; Volume: 0 m3; Surface supérieure totale: 0 m2; Surface par tonne: 0 m2; Surface nette: 0.2 m2; Hauteur: 141.2 mm; Largeur: 10 mm; Longueur: 732.8 mm; sets with these values: 2
Pset_BeamCommon - LoadBearing: no; Reference: 496
BaseQuantities - Length: 732.76 mm; OuterSurfaceArea: 0.167426 m2; NetVolume: 0.000757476 m3; NetWeight: 0 kg

# IfcBeam: PL10*150 (11)
In: Undefined
Description: PL10*150; Material: Undefined/S235-E24
Tekla Commun - Repère de pièce: 42; Phase: 1; Profil: PL10*150; Nom: PRESCELLEMENT PS24; sets with these values: 2
Tekla Quantités - Poids: 0 kg; Volume: 0 m3; Surface supérieure totale: 0.1 m2; Surface par tonne: 0 m2; Surface nette: 0.1 m2; Hauteur: 150 mm; Largeur: 10 mm; Longueur: 350 mm; sets with these values: 2
Pset_BeamCommon - LoadBearing: no; Reference: 42
BaseQuantities - Length: 350 mm; OuterSurfaceArea: 0.115094 m2; NetVolume: 0.000523 m3; NetWeight: 0 kg
Name | Repère d'assemblage
7 x PRESCELLEMENT PS24 | PS1
4 x PRESCELLEMENT PS24 | PS2

# IfcBeam: PL10*155 (2)
In: Undefined
Description: PL10*155; Material: Undefined/S235-E24
Tekla Commun - Repère de pièce: 115; Repère d'assemblage: S5; Phase: 1; Profil: PL10*155; Nom: RAIDISSEUR; sets with these values: 2
Tekla Quantités - Poids: 0 kg; Volume: 0 m3; Surface supérieure totale: 0 m2; Surface par tonne: 0 m2; Surface nette: 0 m2; Hauteur: 155 mm; Largeur: 10 mm; Longueur: 170 mm; sets with these values: 2
Pset_BeamCommon - LoadBearing: no; Reference: 115
BaseQuantities - Length: 170 mm; OuterSurfaceArea: 0.0370421 m2; NetVolume: 0.000157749 m3; NetWeight: 0 kg

# IfcBeam: PL10*160 (66)
In: Undefined
Description: PL10*160
Tekla Commun - Profil: PL10*160; sets with these values: 2
Tekla Quantités - Poids: 0 kg; Volume: 0 m3; Surface supérieure totale: 0 m2; Surface par tonne: 0 m2; Hauteur: 160 mm; Largeur: 10 mm; sets with these values: 2
Pset_BeamCommon - LoadBearing: no
BaseQuantities - NetWeight: 0 kg
Name | Material | Repère de pièce = Reference | Repère d'assemblage | Phase | Nom | Surface nette (m2) | Longueur (mm) = Length (mm) | OuterSurfaceArea (m2) | NetVolume (m3)
4 x PLATINE | Undefined/S275-E28 | 500 | G29 | 2 | PLATINE | 0.1 | 250 | 0.0882 | 0.0004 | Tekla Commun - Finition: GALVA
2 x PLATINE | Undefined/S275-E28 | 500 | G28 | 2 | PLATINE | 0.1 | 250 | 0.0882 | 0.0004 | Tekla Commun - Finition: GALVA
60 x PANNE SHED | Undefined/S235-E24 | 267 | PN19 | 1 | PANNE SHED | 0.2 | 460 | 0.163 | 0.000752

# IfcBeam: PL10*170 (4)
In: Undefined
Description: PL10*170; Material: Undefined/S235-E24
Tekla Commun - Phase: 1; Profil: PL10*170; Nom: RAIDISSEUR; sets with these values: 2
Tekla Quantités - Poids: 0 kg; Volume: 0 m3; Surface supérieure totale: 0 m2; Surface par tonne: 0 m2; Surface nette: 0 m2; Hauteur: 170 mm; Largeur: 10 mm; sets with these values: 2
Pset_BeamCommon - LoadBearing: no
BaseQuantities - NetWeight: 0 kg
Name | Repère de pièce = Reference | Repère d'assemblage | Longueur (mm) | Length (mm) | OuterSurfaceArea (m2) | NetVolume (m3)
2 x RAIDISSEUR | 114 | S4 | 195 | 194.999 | 0.045329 | 0.000195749
2 x RAIDISSEUR | 113 | S3 | 215 | 214.999 | 0.0494843 | 0.000214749

# IfcBeam: PL10*190 (4)
In: Undefined
Description: PL10*190; Material: Undefined/S235-E24
Tekla Commun - Profil: PL10*190; sets with these values: 2
Tekla Quantités - Poids: 0 kg; Volume: 0 m3; Surface supérieure totale: 0 m2; Surface par tonne: 0 m2; Hauteur: 190 mm; Largeur: 10 mm; sets with these values: 2
Pset_BeamCommon - LoadBearing: no
BaseQuantities - NetWeight: 0 kg
Name | Repère de pièce = Reference | Repère d'assemblage | Phase | Nom | Surface nette (m2) | Longueur (mm) | Length (mm) | OuterSurfaceArea (m2) | NetVolume (m3)
COIFFE | 133 | PT5 | 4 | COIFFE | 0.2 | 484.2 | 484.239 | 0.197496 | 0.000920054
2 x ATTACHE | A6 | A6 | 1 | ATTACHE | 0.1 | 180.6 | 180.619 | 0.0799237 | 0.000361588
COIFFE | 133 | PT6(?) | 1 | COIFFE | 0.2 | 484.2 | 484.239 | 0.197496 | 0.000920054

# IfcBeam: PL10*200 (26)
In: Undefined
Description: PL10*200; Material: Undefined/S235-E24
Tekla Commun - Phase: 1; Profil: PL10*200; sets with these values: 2
Tekla Quantités - Poids: 0 kg; Volume: 0 m3; Surface par tonne: 0 m2; Hauteur: 200 mm; Largeur: 10 mm; sets with these values: 2
Pset_BeamCommon - LoadBearing: no
BaseQuantities - NetWeight: 0 kg
Name | Repère de pièce = Reference | Repère d'assemblage | Nom | Surface supérieure totale (m2) | Surface nette (m2) | Longueur (mm) | Length (mm) | OuterSurfaceArea (m2) | NetVolume (m3)
2 x CONTRE PLATINE | CP1 | CP1 | CONTRE PLATINE | 0 | 0.1 | 265 | 264.998 | 0.115299 | 0.000529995 | Tekla Commun - Finition: GALVA
2 x PLATINE | 272 | M20 | PLATINE | 0 | 0.1 | 182 | 182 | 0.0838 | 0.00038
PLATINE | 275 | TS1 | PLATINE | 0 | 0.1 | 150 | 150 | 0.067 | 0.0003
PLATINE | 275 | TS2 | PLATINE | 0 | 0.1 | 150 | 150 | 0.067 | 0.0003
PLATINE | 275 | TS3 | PLATINE | 0 | 0.1 | 150 | 150 | 0.067 | 0.0003
PLATINE | 275 | TS4 | PLATINE | 0 | 0.1 | 150 | 150 | 0.067 | 0.0003
PLATINE | 276 | TS10 | PLATINE | 0 | 0.1 | 135 | 135 | 0.0607 | 0.00027
PLATINE | 275 | TS6 | PLATINE | 0 | 0.1 | 150 | 150 | 0.067 | 0.0003
PLATINE | 275 | TS7 | PLATINE | 0 | 0.1 | 150 | 150 | 0.067 | 0.0003
PLATINE | 275 | TS8 | PLATINE | 0 | 0.1 | 150 | 150 | 0.067 | 0.0003
PLATINE | 275 | TS9 | PLATINE | 0 | 0.1 | 150 | 150 | 0.067 | 0.0003
2 x PLATINE | 294 | M23 | PLATINE | 0.1 | 0.2 | 410 | 410 | 0.1762 | 0.00082
2 x ECLISSE | E2 | E2 | ECLISSE | 0.1 | 0.2 | 410 | 410 | 0.1762 | 0.00082
2 x PLATINE | 287 | M32 | PLATINE | 0 | 0.1 | 200 | 200.003 | 0.0880013 | 0.000400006
2 x PLATINE | 287 | M22 | PLATINE | 0 | 0.1 | 200 | 200.003 | 0.0880013 | 0.000400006
2 x PLATINE | 287 | M19 | PLATINE | 0 | 0.1 | 200 | 200.003 | 0.0880013 | 0.000400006
2 x PLATINE | 287 | M31 | PLATINE | 0 | 0.1 | 200 | 200.003 | 0.0880013 | 0.000400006
COIFFE | 136 | PT3 | COIFFE | 0.1 | 0.2 | 484 | 484 | 0.20728 | 0.000968

# IfcBeam: PL10*240 (4)
In: Undefined
Description: PL10*240; Material: Undefined/S235-E24
Tekla Commun - Repère de pièce: 277; Phase: 1; Profil: PL10*240; Nom: PLATINE; sets with these values: 2
Tekla Quantités - Poids: 0 kg; Volume: 0 m3; Surface supérieure totale: 0 m2; Surface par tonne: 0 m2; Surface nette: 0.1 m2; Hauteur: 240 mm; Largeur: 10 mm; Longueur: 150 mm; sets with these values: 2
Pset_BeamCommon - LoadBearing: no; Reference: 277
BaseQuantities - Length: 150 mm; OuterSurfaceArea: 0.0798 m2; NetVolume: 0.00036 m3; NetWeight: 0 kg
Name | Repère d'assemblage
PLATINE | TS14
PLATINE | TS11
PLATINE | TS12
PLATINE | TS13

# IfcBeam: PL10*250, PRESCELLEMENT
In: Undefined
Description: PL10*250; Material: Undefined/S235-E24
Tekla Commun - Repère de pièce: 118; Repère d'assemblage: PS3; Phase: 1; Profil: PL10*250; Nom: PRESCELLEMENT; sets with these values: 2
Tekla Quantités - Poids: 0 kg; Volume: 0 m3; Surface supérieure totale: 0 m2; Surface par tonne: 0 m2; Surface nette: 0.1 m2; Hauteur: 250 mm; Largeur: 10 mm; Longueur: 230 mm; sets with these values: 2
Pset_BeamCommon - LoadBearing: no; Reference: 118
BaseQuantities - Length: 230 mm; OuterSurfaceArea: 0.1246 m2; NetVolume: 0.000575 m3; NetWeight: 0 kg

# IfcBeam: PL10*260 (12)
In: Undefined
Description: PL10*260; Material: Undefined/S235-E24
Tekla Commun - Phase: 1; Profil: PL10*260; Nom: SABOT; sets with these values: 2
Tekla Quantités - Poids: 0 kg; Volume: 0 m3; Surface supérieure totale: 0 m2; Surface par tonne: 0 m2; Hauteur: 260 mm; Largeur: 10 mm; sets with these values: 2
Pset_BeamCommon - LoadBearing: no
BaseQuantities - NetWeight: 0 kg
Name | Repère de pièce = Reference | Repère d'assemblage | Surface nette (m2) | Longueur (mm) | Length (mm) | OuterSurfaceArea (m2) | NetVolume (m3)
2 x SABOT | 125 | S1 | 0.1 | 110 | 110.012 | 0.0646066 | 0.000286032
2 x SABOT | 120 | S1 | 0.3 | 565 | 565 | 0.3103 | 0.001469
SABOT | 117 | S5 | 0.1 | 170 | 170 | 0.097 | 0.000442
SABOT | 124 | S5 | 0.1 | 180 | 180.001 | 0.1024 | 0.000468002
SABOT | 116 | S4 | 0.1 | 170 | 170 | 0.097 | 0.000442
SABOT | 123 | S4 | 0.1 | 220 | 220.001 | 0.124 | 0.000572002
SABOT | 116 | S3 | 0.1 | 170 | 170 | 0.097 | 0.000442
SABOT | 122 | S3 | 0.1 | 240 | 240.001 | 0.1348 | 0.000624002
SABOT | 126 | S2 | 0.1 | 110 | 110.012 | 0.0646066 | 0.000286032
SABOT | 121 | S2 | 0.3 | 465 | 465 | 0.2563 | 0.001209

# IfcBeam: PL10*290 (2)
In: Undefined
Description: PL10*290; Material: Undefined/S235-E24
Tekla Commun - Phase: 1; Profil: PL10*290; Nom: PLATINE; sets with these values: 2
Tekla Quantités - Poids: 0 kg; Volume: 0 m3; Surface supérieure totale: 0.2 m2; Surface par tonne: 0 m2; Surface nette: 0.4 m2; Hauteur: 290 mm; Largeur: 10 mm; Longueur: 581 mm; sets with these values: 2
Pset_BeamCommon - LoadBearing: no
BaseQuantities - Length: 581 mm; OuterSurfaceArea: 0.3544 m2; NetVolume: 0.0016849 m3; NetWeight: 0 kg
Name | Repère de pièce = Reference | Repère d'assemblage
PLATINE | 274 | PT10
PLATINE | 108 | PT12

# IfcBeam: PL10*360 (4)
In: Undefined
Description: PL10*360; Material: Undefined/S235-E24
Tekla Commun - Finition: GALVA; Repère de pièce: 499; Repère d'assemblage: G29; Phase: 2; Profil: PL10*360; Nom: GOUSSET; sets with these values: 2
Tekla Quantités - Poids: 0 kg; Volume: 0 m3; Surface supérieure totale: 0 m2; Surface par tonne: 0 m2; Surface nette: 0.1 m2; Hauteur: 360 mm; Largeur: 10 mm; Longueur: 237.4 mm; sets with these values: 2
Pset_BeamCommon - LoadBearing: no; Reference: 499
BaseQuantities - Length: 237.448 mm; OuterSurfaceArea: 0.115218 m2; NetVolume: 0.000519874 m3; NetWeight: 0 kg

# IfcBeam: PL10*370 (2)
In: Undefined
Description: PL10*370; Material: Undefined/S235-E24
Tekla Commun - Finition: GALVA; Repère de pièce: 497; Repère d'assemblage: G28; Phase: 2; Profil: PL10*370; Nom: GOUSSET; sets with these values: 2
Tekla Quantités - Poids: 0 kg; Volume: 0 m3; Surface supérieure totale: 0 m2; Surface par tonne: 0 m2; Surface nette: 0.1 m2; Hauteur: 370 mm; Largeur: 10 mm; Longueur: 309.4 mm; sets with these values: 2
Pset_BeamCommon - LoadBearing: no; Reference: 497
BaseQuantities - Length: 309.388 mm; OuterSurfaceArea: 0.14183 m2; NetVolume: 0.000653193 m3; NetWeight: 0 kg

# IfcBeam: PL10*420, PLATINE
In: Undefined
Description: PL10*420; Material: Undefined/S235-E24
Tekla Commun - Repère de pièce: 278; Repère d'assemblage: TS5; Phase: 1; Profil: PL10*420; Nom: PLATINE; sets with these values: 2
Tekla Quantités - Poids: 0 kg; Volume: 0 m3; Surface supérieure totale: 0.1 m2; Surface par tonne: 0 m2; Surface nette: 0.1 m2; Hauteur: 420 mm; Largeur: 10 mm; Longueur: 150 mm; sets with these values: 2
Pset_BeamCommon - LoadBearing: no; Reference: 278
BaseQuantities - Length: 150 mm; OuterSurfaceArea: 0.1374 m2; NetVolume: 0.00063 m3; NetWeight: 0 kg

# IfcBeam: PL10*500, PLATINE
In: Undefined
Description: PL10*500; Material: Undefined/S235-E24
Tekla Commun - Repère de pièce: 285; Repère d'assemblage: TS15; Phase: 1; Profil: PL10*500; Nom: PLATINE; sets with these values: 2
Tekla Quantités - Poids: 0 kg; Volume: 0 m3; Surface supérieure totale: 0.1 m2; Surface par tonne: 0 m2; Surface nette: 0.2 m2; Hauteur: 500 mm; Largeur: 10 mm; Longueur: 150 mm; sets with these values: 2
Pset_BeamCommon - LoadBearing: no; Reference: 285
BaseQuantities - Length: 150 mm; OuterSurfaceArea: 0.163 m2; NetVolume: 0.00075 m3; NetWeight: 0 kg

# IfcBeam: PL10*60 (112)
In: Undefined
Description: PL10*60; Material: Undefined/S235-E24
Tekla Commun - Profil: PL10*60; sets with these values: 2
Tekla Quantités - Poids: 0 kg; Volume: 0 m3; Surface supérieure totale: 0 m2; Surface par tonne: 0 m2; Hauteur: 60 mm; Largeur: 10 mm; sets with these values: 2
Pset_BeamCommon - LoadBearing: no
BaseQuantities - NetWeight: 0 kg
Name | Finition | Repère de pièce = Reference | Repère d'assemblage | Phase | Nom | Surface nette (m2) | Longueur (mm) | Length (mm) | OuterSurfaceArea (m2) | NetVolume (m3)
5 x PLATINE | GALVA | 525 | GC0(?) | 3 | PLATINE | 0 | 130 | 130 | 0.0194 | 0.000078
MONTANT | GALVA | 519 | GC0(?) | 3 | MONTANT | 0.1 | 967.6 | 967.6 | 0.133929 | 0.00056856
MONTANT | GALVA | 0 | 0(?) | 3 | MONTANT | 0.1 | 967.6 | 967.6 | 0.133929 | 0.000568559
2 x PLATINE | GALVA | 526 | GC0(?) | 3 | PLATINE | 0 | 130 | 130 | 0.0194 | 0.000078
2 x MONTANT | GALVA | 569 | GC0(?) | 3 | MONTANT | 0.1 | 876.5 | 876.489 | 0.120647 | 0.000511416
MONTANT | GALVA | 518 | GC0(?) | 3 | MONTANT | 0.1 | 967.6 | 967.6 | 0.133929 | 0.00056856
PLATINE | GALVA | 0 | 0(?) | 3 | PLATINE | 0 | 130 | 130 | 0.0194 | 0.000078
4 x PLATINE | GALVA | 525 | GC12 | 3 | PLATINE | 0 | 130 | 130 | 0.0194 | 0.000078
PLATINE | GALVA | 324 | GC8 | 3 | PLATINE | 0 | 65 | 65 | 0.0103 | 0.000039
2 x PLATINE | GALVA | 324 | GC10 | 3 | PLATINE | 0 | 65 | 65 | 0.0103 | 0.000039
5 x PLATINE | GALVA | 525 | GC8 | 3 | PLATINE | 0 | 130 | 130 | 0.0194 | 0.000078
4 x MONTANT | GALVA | 519 | GC8 | 3 | MONTANT | 0.1 | 967.6 | 967.6 | 0.133929 | 0.00056856
4 x PLATINE | GALVA | 525 | GC4 | 3 | PLATINE | 0 | 130 | 130 | 0.0194 | 0.000078
3 x MONTANT | GALVA | 519 | GC4 | 3 | MONTANT | 0.1 | 967.6 | 967.6 | 0.133929 | 0.00056856
MONTANT | GALVA | 518 | GC8 | 3 | MONTANT | 0.1 | 967.6 | 967.6 | 0.133929 | 0.00056856
3 x PLATINE | GALVA | 525 | GC10 | 3 | PLATINE | 0 | 130 | 130 | 0.0194 | 0.000078
PLATINE | GALVA | 324 | GC4 | 3 | PLATINE | 0 | 65 | 65 | 0.0103 | 0.000039
4 x PLATINE | GALVA | 525 | GC2 | 3 | PLATINE | 0 | 130 | 130 | 0.0194 | 0.000078
3 x MONTANT | GALVA | 509 | GC2 | 3 | MONTANT | 0.1 | 937.6 | 937.6 | 0.129729 | 0.00055056
2 x PLATINE | GALVA | 319 | GC6 | 3 | PLATINE | 0 | 130 | 130 | 0.0194 | 0.000078
2 x MONTANT | GALVA | 518 | GC6 | 3 | MONTANT | 0.1 | 967.6 | 967.6 | 0.133929 | 0.00056856
6 x PLATINE | GALVA | 525 | GC3 | 3 | PLATINE | 0 | 130 | 130 | 0.0194 | 0.000078
5 x MONTANT | GALVA | 509 | GC3 | 3 | MONTANT | 0.1 | 937.6 | 937.6 | 0.129729 | 0.00055056
3 x MONTANT | GALVA | 514 | GC3 | 3 | MONTANT | 0.1 | 863.2 | 863.191 | 0.118507 | 0.000501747
2 x MONTANT | GALVA | 507 | GC2 | 3 | MONTANT | 0.1 | 863.2 | 863.191 | 0.118507 | 0.000501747
2 x PLATINE | GALVA | 318 | GC1 | 3 | PLATINE | 0 | 130 | 130 | 0.0194 | 0.000078
2 x MONTANT | GALVA | 509 | GC1 | 3 | MONTANT | 0.1 | 937.6 | 937.6 | 0.129729 | 0.00055056
MONTANT | GALVA | 507 | GC1 | 3 | MONTANT | 0.1 | 863.2 | 863.191 | 0.118507 | 0.000501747
MONTANT | GALVA | 518 | GC4 | 3 | MONTANT | 0.1 | 967.6 | 967.6 | 0.133929 | 0.00056856
2 x PLATINE | GALVA | 526 | GC7 | 3 | PLATINE | 0 | 130 | 130 | 0.0194 | 0.000078
2 x MONTANT | GALVA | 518 | GC7 | 3 | MONTANT | 0.1 | 967.6 | 967.6 | 0.133929 | 0.00056856
3 x MONTANT | GALVA | 519 | GC10 | 3 | MONTANT | 0.1 | 967.6 | 967.6 | 0.133929 | 0.00056856
MONTANT | GALVA | 517 | GC8 | 3 | MONTANT | 0.1 | 860.1 | 860.124 | 0.117945 | 0.000499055
12 x PLATINE |  | 282 | MC3 | 1 | PLATINE | 0 | 130 | 130 | 0.0194 | 0.000078
6 x PLATINE |  | 282 | MC2 | 1 | PLATINE | 0 | 130 | 130 | 0.0194 | 0.000078
12 x PLATINE |  | 282 | MC1 | 1 | PLATINE | 0 | 130 | 130 | 0.0194 | 0.000078

# IfcBeam: PL10*70 (9)
In: Undefined
Description: PL10*70; Material: Undefined/S235-E24
Tekla Commun - Repère de pièce: 270; Phase: 1; Profil: PL10*70; Nom: PLATINE; sets with these values: 2
Tekla Quantités - Poids: 0 kg; Volume: 0 m3; Surface supérieure totale: 0 m2; Surface par tonne: 0 m2; Surface nette: 0.1 m2; Hauteur: 70 mm; Largeur: 10 mm; Longueur: 360 mm; sets with these values: 2
Pset_BeamCommon - LoadBearing: no; Reference: 270
BaseQuantities - Length: 360 mm; OuterSurfaceArea: 0.059 m2; NetVolume: 0.000252 m3; NetWeight: 0 kg
Name | Repère d'assemblage
3 x PLATINE | S20
3 x PLATINE | S22
3 x PLATINE | S21

# IfcBeam: PL10*80 (8)
In: Undefined
Description: PL10*80; Material: Undefined/S235-E24
Tekla Commun - Profil: PL10*80; sets with these values: 2
Tekla Quantités - Poids: 0 kg; Volume: 0 m3; Surface par tonne: 0 m2; Hauteur: 80 mm; Largeur: 10 mm; sets with these values: 2
Pset_BeamCommon - LoadBearing: no
BaseQuantities - NetWeight: 0 kg
Name | Repère de pièce = Reference | Repère d'assemblage | Phase | Nom | Surface supérieure totale (m2) | Surface nette (m2) | Longueur (mm) = Length (mm) | OuterSurfaceArea (m2) | NetVolume (m3)
SUPPORT | S42 | S42 | 1 | SUPPORT | 0.1 | 1.2 | 6735 | 1.2139 | 0.005388
SUPPORT | S16 | S16 | 1 | SUPPORT | 0.1 | 1.5 | 8195 | 1.4767 | 0.006556
4 x GOUSSET | 498 | B14 | 2 | GOUSSET | 0 | 0 | 260 | 0.0466612 | 0.00020103 | Tekla Commun - Finition: GALVA
2 x ATTACHE | A5 | A5 | 1 | ATTACHE | 0 | 0.1 | 270 | 0.052 | 0.000224

# IfcBeam: PL10*82 (4)
In: Undefined
Description: PL10*82
Tekla Commun - Finition: GALVA; Phase: 2; Profil: PL10*82; sets with these values: 2
Tekla Quantités - Poids: 0 kg; Volume: 0 m3; Surface supérieure totale: 0 m2; Surface par tonne: 0 m2; Hauteur: 82 mm; Largeur: 10 mm; sets with these values: 2
Pset_BeamCommon - LoadBearing: no
BaseQuantities - NetWeight: 0 kg
Name | Material | Repère de pièce = Reference | Repère d'assemblage | Nom | Surface nette (m2) | Longueur (mm) | Length (mm) | OuterSurfaceArea (m2) | NetVolume (m3)
PLAT | Undefined/S235-E24 | 502 | PT11 | PLAT | 0 | 150 | 149.999 | 0.0297919 | 0.000125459
PLAT | Undefined/S235-E24 | 502 | PT13 | PLAT | 0 | 150 | 149.999 | 0.0297919 | 0.000125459
2 x PLATINE | Undefined/S275-E28 | 501 | G11 | PLATINE | 0.1 | 300 | 300 | 0.05684 | 0.000246

# IfcBeam: PL10*90 (2)
In: Undefined
Description: PL10*90; Material: Undefined/S235-E24
Tekla Commun - Repère de pièce: E1; Repère d'assemblage: E1; Phase: 1; Profil: PL10*90; Nom: ECLISSE; sets with these values: 2
Tekla Quantités - Poids: 0 kg; Volume: 0 m3; Surface supérieure totale: 0 m2; Surface par tonne: 0 m2; Surface nette: 0.1 m2; Hauteur: 90 mm; Largeur: 10 mm; Longueur: 410 mm; sets with these values: 2
Pset_BeamCommon - LoadBearing: no; Reference: E1
BaseQuantities - Length: 410 mm; OuterSurfaceArea: 0.0838 m2; NetVolume: 0.000369 m3; NetWeight: 0 kg

# IfcBeam: PL100*5 (15)
In: Undefined
Description: PL100*5; Material: Undefined/S235-E24
Pset_BeamCommon - LoadBearing: no
Tekla Commun - Finition: GALVA; Phase: 3; Profil: PL100*5; Nom: PLINTHE; sets with these values: 2
Tekla Quantités - Poids: 0 kg; Volume: 0 m3; Surface supérieure totale: 0 m2; Surface par tonne: 0 m2; Hauteur: 100 mm; Largeur: 5 mm; sets with these values: 2
BaseQuantities - NetWeight: 0 kg
Name | Reference = Repère de pièce | Repère d'assemblage | Surface nette (m2) | Longueur (mm) | Length (mm) | OuterSurfaceArea (m2) | NetVolume (m3)
PLINTHE | 0 | 0(?) | 0.8 | 3850 | 3849.99 | 0.809498 | 0.00192499
PLINTHE | 537 | GC12 | 0.4 | 1735 | 1734.99 | 0.365349 | 0.000867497
PLINTHE | 540 | GC12 | 0.2 | 1100 | 1100 | 0.232 | 0.00055
PLINTHE | 539 | GC10 | 1.1 | 5200 | 5200 | 1.093 | 0.0026
PLINTHE | 538 | GC4 | 0.8 | 3650 | 3649.98 | 0.767497 | 0.00182499
PLINTHE | 537 | GC8 | 0.4 | 1735 | 1734.99 | 0.365349 | 0.000867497
PLINTHE | 530 | GC6 | 0.2 | 1010 | 1009.99 | 0.213099 | 0.000504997
PLINTHE | 529 | GC3 | 0.2 | 845 | 845.004 | 0.178451 | 0.000422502
2 x PLINTHE | 529 | GC2 | 0.2 | 845 | 845 | 0.17845 | 0.0004225
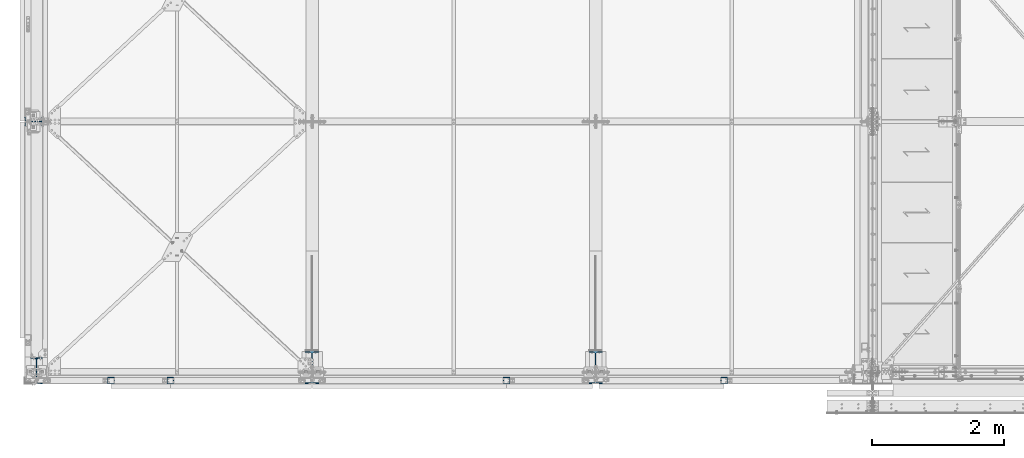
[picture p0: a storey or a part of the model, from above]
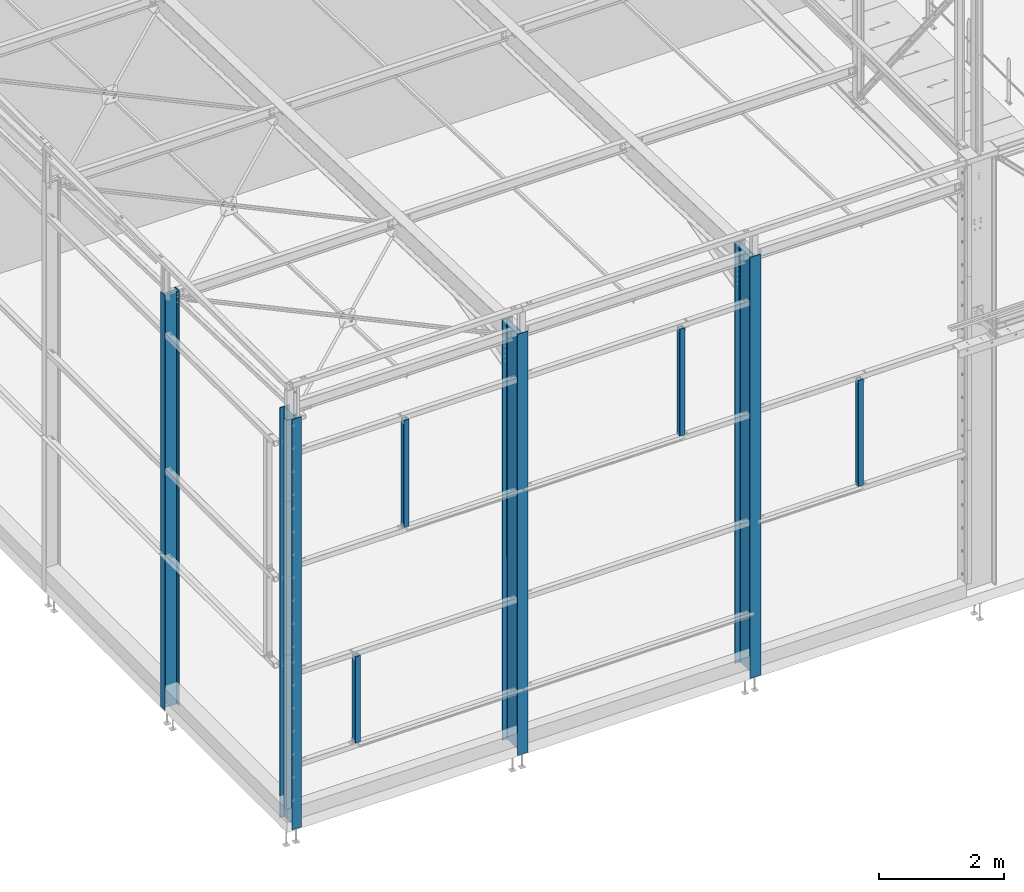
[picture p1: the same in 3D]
Properties of the parts of a building model (IFC2X3), part 2 of 4

# IfcBeam: PL100*5 (15)
Name | Reference = Repère de pièce | Repère d'assemblage | Surface nette (m2) | Longueur (mm) | Length (mm) | OuterSurfaceArea (m2) | NetVolume (m3)
PLINTHE | 529 | GC3 | 0.2 | 845 | 845 | 0.17845 | 0.0004225
PLINTHE | 529 | GC1 | 0.2 | 845 | 845 | 0.17845 | 0.0004225
PLINTHE | 532 | GC8 | 0.5 | 2550 | 2550 | 0.5365 | 0.001275
PLINTHE | 530 | GC7 | 0.2 | 1010 | 1009.99 | 0.213099 | 0.000504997
PLINTHE | 529 | GC3 | 0.2 | 845 | 845.001 | 0.17845 | 0.0004225

# IfcBeam: PL12*140, PLAT
In: Undefined
Description: PL12*140; Material: Undefined/S235-E24
Tekla Commun - Repère de pièce: 226; Repère d'assemblage: PS5; Phase: 1; Profil: PL12*140; Nom: PLAT; sets with these values: 2
Tekla Quantités - Poids: 0 kg; Volume: 0 m3; Surface supérieure totale: 0 m2; Surface par tonne: 0 m2; Surface nette: 0 m2; Hauteur: 140 mm; Largeur: 12 mm; Longueur: 133 mm; sets with these values: 2
Pset_BeamCommon - LoadBearing: no; Reference: 226
BaseQuantities - Length: 133 mm; OuterSurfaceArea: 0.043792 m2; NetVolume: 0.00022344 m3; NetWeight: 0 kg

# IfcBeam: PL12*250, PRESCELLEMENT
In: Undefined
Description: PL12*250; Material: Undefined/S235-E24
Tekla Commun - Repère de pièce: 229; Repère d'assemblage: PS5; Phase: 1; Profil: PL12*250; Nom: PRESCELLEMENT; sets with these values: 2
Tekla Quantités - Poids: 0 kg; Volume: 0 m3; Surface supérieure totale: 0 m2; Surface par tonne: 0 m2; Surface nette: 0.1 m2; Hauteur: 250 mm; Largeur: 12 mm; Longueur: 230 mm; sets with these values: 2
Pset_BeamCommon - LoadBearing: no; Reference: 229
BaseQuantities - Length: 230 mm; OuterSurfaceArea: 0.12652 m2; NetVolume: 0.00069 m3; NetWeight: 0 kg

# IfcBeam: PL12*300 (27)
In: Undefined
Description: PL12*300; Material: Undefined/S235-E24
Tekla Commun - Profil: PL12*300; sets with these values: 2
Tekla Quantités - Poids: 0 kg; Volume: 0 m3; Surface par tonne: 0 m2; Hauteur: 300 mm; Largeur: 12 mm; sets with these values: 2
Pset_BeamCommon - LoadBearing: no
BaseQuantities - NetWeight: 0 kg
Name | Finition | Repère de pièce = Reference | Repère d'assemblage | Phase | Nom | Surface supérieure totale (m2) | Surface nette (m2) | Longueur (mm) = Length (mm) | OuterSurfaceArea (m2) | NetVolume (m3)
7 x PLATINE CONSOLE | GALVA | 511 | C9 | 3 | PLATINE CONSOLE | 0 | 0.2 | 300 | 0.1944 | 0.00108
6 x PLATINE | GALVA | 510 | P4 | 3 | PLATINE | 0.1 | 0.2 | 300 | 0.1944 | 0.00108
8 x PLATINE | GALVA | 510 | P3 | 3 | PLATINE | 0.1 | 0.2 | 300 | 0.1944 | 0.00108
3 x PRESCELLEMENT |  | 227 | PS6 | 1 | PRESCELLEMENT | 0 | 0.4 | 655 | 0.41592 | 0.002358
3 x PRESCELLEMENT |  | 228 | PS4 | 1 | PRESCELLEMENT | 0 | 0.3 | 430 | 0.27552 | 0.001548

# IfcBeam: PL15*190 (5)
In: Undefined
Description: PL15*190; Material: Undefined/S235-E24
Tekla Commun - Phase: 1; Profil: PL15*190; sets with these values: 2
Tekla Quantités - Poids: 0 kg; Volume: 0 m3; Surface supérieure totale: 0 m2; Surface par tonne: 0 m2; Hauteur: 190 mm; Largeur: 15 mm; sets with these values: 2
Pset_BeamCommon - LoadBearing: no
BaseQuantities - NetWeight: 0 kg
Name | Repère de pièce = Reference | Repère d'assemblage | Nom | Surface nette (m2) | Longueur (mm) | Length (mm) | OuterSurfaceArea (m2) | NetVolume (m3)
PLATINE | 154 | T3 | PLATINE | 0.3 | 720 | 720 | 0.3009 | 0.002052
JARRET | 152 | T7 | JARRET | 0.6 | 1549.7 | 1549.71 | 0.641081 | 0.00441667
PLATINE | 139 | T7 | PLATINE | 0.4 | 900 | 900 | 0.3747 | 0.002565
JARRET | 152 | T1 | JARRET | 0.6 | 1549.7 | 1549.71 | 0.641081 | 0.00441667
PLATINE | 139 | T1 | PLATINE | 0.4 | 900 | 900 | 0.3747 | 0.002565

# IfcBeam: PL15*200 (7)
In: Undefined
Description: PL15*200; Material: Undefined/S235-E24
Tekla Commun - Finition: GALVA; Repère de pièce: 199; Phase: 1; Profil: PL15*200; Nom: PLATINE; sets with these values: 2
Tekla Quantités - Poids: 0 kg; Volume: 0 m3; Surface supérieure totale: 0 m2; Surface par tonne: 0 m2; Surface nette: 0.1 m2; Hauteur: 200 mm; Largeur: 15 mm; Longueur: 265 mm; sets with these values: 2
Pset_BeamCommon - LoadBearing: no; Reference: 199
BaseQuantities - NetWeight: 0 kg
Name | Repère d'assemblage | Length (mm) | OuterSurfaceArea (m2) | NetVolume (m3)
2 x PLATINE | C12 | 264.998 | 0.119949 | 0.000794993
5 x PLATINE | C11 | 265 | 0.11995 | 0.000795

# IfcBeam: PL15*210 (2)
In: Undefined
Description: PL15*210; Material: Undefined/S235-E24
Tekla Commun - Repère de pièce: 153; Phase: 1; Profil: PL15*210; Nom: PLATINE; sets with these values: 2
Tekla Quantités - Poids: 0 kg; Volume: 0 m3; Surface supérieure totale: 0 m2; Surface par tonne: 0 m2; Surface nette: 0.3 m2; Hauteur: 210 mm; Largeur: 15 mm; Longueur: 550 mm; sets with these values: 2
Pset_BeamCommon - LoadBearing: no; Reference: 153
BaseQuantities - Length: 550 mm; OuterSurfaceArea: 0.2538 m2; NetVolume: 0.0017325 m3; NetWeight: 0 kg
Name | Repère d'assemblage
PLATINE | T4
PLATINE | T5

# IfcBeam: PL15*300 (2)
In: Undefined
Description: PL15*300; Material: Undefined/S235-E24
Tekla Commun - Repère de pièce: 29; Phase: 1; Profil: PL15*300; Nom: PLATINE; sets with these values: 2
Tekla Quantités - Poids: 0 kg; Volume: 0 m3; Surface supérieure totale: 0.1 m2; Surface par tonne: 0 m2; Surface nette: 0.2 m2; Hauteur: 300 mm; Largeur: 15 mm; Longueur: 310 mm; sets with these values: 2
Pset_BeamCommon - LoadBearing: no; Reference: 29
BaseQuantities - Length: 310 mm; OuterSurfaceArea: 0.2043 m2; NetVolume: 0.001395 m3; NetWeight: 0 kg
Name | Repère d'assemblage
PLATINE | PT10
PLATINE | PT12

# IfcBeam: PL15*490 (4)
In: Undefined
Description: PL15*490; Material: Undefined/S235-E24
Tekla Commun - Repère de pièce: 28; Profil: PL15*490; Nom: PLATINE; sets with these values: 2
Tekla Quantités - Poids: 0 kg; Volume: 0 m3; Surface supérieure totale: 0.2 m2; Surface par tonne: 0 m2; Surface nette: 0.3 m2; Hauteur: 490 mm; Largeur: 15 mm; Longueur: 310 mm; sets with these values: 2
Pset_BeamCommon - LoadBearing: no; Reference: 28
BaseQuantities - Length: 310 mm; OuterSurfaceArea: 0.3278 m2; NetVolume: 0.0022785 m3; NetWeight: 0 kg
Name | Repère d'assemblage | Phase
PLATINE | PT5 | 4
PLATINE | PT4 | 1
PLATINE | PT3 | 1
PLATINE | PT6(?) | 1

# IfcBeam: PL15*90 (44)
In: Undefined
Description: PL15*90; Material: Undefined/S235-E24
Tekla Commun - Phase: 1; Profil: PL15*90; Nom: PLAQUETTE; sets with these values: 2
Tekla Quantités - Poids: 0 kg; Volume: 0 m3; Surface supérieure totale: 0 m2; Surface par tonne: 0 m2; Surface nette: 0 m2; Hauteur: 90 mm; Largeur: 15 mm; Longueur: 90 mm; sets with these values: 2
Pset_BeamCommon - LoadBearing: no
BaseQuantities - Length: 90 mm; OuterSurfaceArea: 0.0216 m2; NetVolume: 0.0001215 m3; NetWeight: 0 kg
Name | Repère de pièce = Reference | Repère d'assemblage
14 x PLAQUETTE | 41 | PS1
14 x PLAQUETTE | 34 | PS1
8 x PLAQUETTE | 41 | PS2
8 x PLAQUETTE | 34 | PS2

# IfcBeam: PL150*4 (7)
In: Undefined
Description: PL150*4; Material: Undefined/S235-E24
Tekla Commun - Phase: 1; Profil: PL150*4; Nom: SUPPORT; sets with these values: 2
Tekla Quantités - Poids: 0 kg; Volume: 0 m3; Surface supérieure totale: 0 m2; Surface par tonne: 0 m2; Hauteur: 150 mm; Largeur: 4 mm; sets with these values: 2
Pset_BeamCommon - LoadBearing: no
BaseQuantities - NetWeight: 0 kg
Name | Repère de pièce = Repère d'assemblage = Reference | Surface nette (m2) | Longueur (mm) = Length (mm) | OuterSurfaceArea (m2) | NetVolume (m3)
SUPPORT | S50 | 0.2 | 515 | 0.15982 | 0.000309
SUPPORT | S49 | 0.7 | 2125 | 0.6557 | 0.001275
2 x SUPPORT | S46 | 0.9 | 2965 | 0.91442 | 0.001779
3 x SUPPORT | S45 | 0.9 | 3000 | 0.9252 | 0.0018

# IfcBeam: PL160*8, ATTACHE
In: Undefined
Description: PL160*8; Material: Undefined/S235-E24
Tekla Commun - Repère de pièce: A76; Repère d'assemblage: A76; Phase: 1; Profil: PL160*8; Nom: ATTACHE; sets with these values: 2
Tekla Quantités - Poids: 0 kg; Volume: 0 m3; Surface supérieure totale: 0 m2; Surface par tonne: 0 m2; Surface nette: 0.1 m2; Hauteur: 160 mm; Largeur: 8 mm; Longueur: 164 mm; sets with these values: 2
Pset_BeamCommon - LoadBearing: no; Reference: A76
BaseQuantities - Length: 164 mm; OuterSurfaceArea: 0.060352 m2; NetVolume: 0.00022016 m3; NetWeight: 0 kg

# IfcBeam: PL2*4000 (12)
In: Undefined
Description: PL2*4000; Material: Undefined/S235-E24
Tekla Commun - Phase: 1; Profil: PL2*4000; Nom: POUTRE; sets with these values: 2
Tekla Quantités - Poids: 0 kg; Volume: 0 m3; Surface supérieure totale: 0 m2; Surface par tonne: 0 m2; Largeur: 2 mm; sets with these values: 2
Pset_BeamCommon - LoadBearing: no
BaseQuantities - NetWeight: 0 kg
Name | Repère de pièce = Repère d'assemblage = Reference | Surface nette (m2) | Hauteur (mm) | Longueur (mm) = Length (mm) | OuterSurfaceArea (m2) | NetVolume (m3)
6 x POUTRE | A70 | 1.3 | 3791.9 | 176 | 1.33859 | 0.00132271
POUTRE | A2 | 1 | 3791.9 | 136 | 1.02828 | 0.00101256
2 x POUTRE | A69 | 1 | 3791.9 | 136 | 1.03508 | 0.00101936
2 x POUTRE | A71 | 1.4 | 3947.3 | 176 | 1.37957 | 0.00136273
POUTRE | A72 | 1.1 | 3947.3 | 136 | 1.06363 | 0.00104695

# IfcBeam: PL20*80, PLAT
In: Undefined
Description: PL20*80; Material: Undefined/S235-E24
Tekla Commun - Repère de pièce: 130; Repère d'assemblage: PS3; Phase: 1; Profil: PL20*80; Nom: PLAT; sets with these values: 2
Tekla Quantités - Poids: 0 kg; Volume: 0 m3; Surface supérieure totale: 0 m2; Surface par tonne: 0 m2; Surface nette: 0 m2; Hauteur: 80 mm; Largeur: 20 mm; Longueur: 120 mm; sets with these values: 2
Pset_BeamCommon - LoadBearing: no; Reference: 130
BaseQuantities - Length: 120 mm; OuterSurfaceArea: 0.0272 m2; NetVolume: 0.000192 m3; NetWeight: 0 kg

# IfcBeam: PL200*6 (3)
In: Undefined
Description: PL200*6; Material: Undefined/S235-E24
Tekla Commun - Finition: GALVA; Repère de pièce: GC0; Repère d'assemblage: GC0(?); Phase: 3; Profil: PL200*6; Nom: CACHE VIDE; sets with these values: 2
Tekla Quantités - Poids: 0 kg; Volume: 0 m3; Surface par tonne: 0 m2; Hauteur: 200 mm; Largeur: 6 mm; sets with these values: 2
Pset_BeamCommon - LoadBearing: no; Reference: GC0
BaseQuantities - NetWeight: 0 kg
Name | Surface supérieure totale (m2) | Surface nette (m2) | Longueur (mm) = Length (mm) | OuterSurfaceArea (m2) | NetVolume (m3)
2 x CACHE VIDE | 0.3 | 0.7 | 1650 | 0.6822 | 0.00198
CACHE VIDE | 1.1 | 2.2 | 5350 | 2.2066 | 0.00642

# IfcBeam: PL3*1055, SUPPORT CHARGE BARDAG
In: Undefined
Description: PL3*1055; Material: Undefined/S235-E24
Tekla Commun - Repère de pièce: S26; Repère d'assemblage: S26; Phase: 1; Profil: PL3*1055; Nom: SUPPORT CHARGE BARDAG; sets with these values: 2
Tekla Quantités - Poids: 0 kg; Volume: 0 m3; Surface supérieure totale: 0 m2; Surface par tonne: 0 m2; Surface nette: 0.8 m2; Hauteur: 1055 mm; Largeur: 3 mm; Longueur: 378 mm; sets with these values: 2
Pset_BeamCommon - LoadBearing: no; Reference: S26
BaseQuantities - Length: 378 mm; OuterSurfaceArea: 0.818874 m2; NetVolume: 0.00121536 m3; NetWeight: 0 kg

# IfcBeam: PL3*1450 (2)
In: Undefined
Description: PL3*1450; Material: Undefined/S235-E24
Tekla Commun - Finition: GALVA; Repère de pièce: F18; Repère d'assemblage: F18; Phase: 2; Profil: PL3*1450; Nom: FEUILLURE; sets with these values: 2
Tekla Quantités - Poids: 0 kg; Volume: 0 m3; Surface supérieure totale: 0 m2; Surface par tonne: 0 m2; Surface nette: 0.5 m2; Hauteur: 1450 mm; Largeur: 3 mm; Longueur: 159.3 mm; sets with these values: 2
Pset_BeamCommon - LoadBearing: no; Reference: F18
BaseQuantities - Length: 159.306 mm; OuterSurfaceArea: 0.479917 m2; NetVolume: 0.000705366 m3; NetWeight: 0 kg

# IfcBeam: PL3*1550 (2)
In: Undefined
Description: PL3*1550; Material: Undefined/S235-E24
Tekla Commun - Repère de pièce: F14; Repère d'assemblage: F14; Phase: 1; Profil: PL3*1550; Nom: FEUILLURE; sets with these values: 2
Tekla Quantités - Poids: 0 kg; Volume: 0 m3; Surface supérieure totale: 0 m2; Surface par tonne: 0 m2; Surface nette: 0.9 m2; Hauteur: 1550 mm; Largeur: 3 mm; Longueur: 285.3 mm; sets with these values: 2
Pset_BeamCommon - LoadBearing: no; Reference: F14
BaseQuantities - Length: 285.25 mm; OuterSurfaceArea: 0.913922 m2; NetVolume: 0.00135431 m3; NetWeight: 0 kg

# IfcBeam: PL3*1950 (2)
In: Undefined
Description: PL3*1950; Material: Undefined/S235-E24
Tekla Commun - Repère de pièce: F13; Repère d'assemblage: F13; Phase: 1; Profil: PL3*1950; Nom: FEUILLURE; sets with these values: 2
Tekla Quantités - Poids: 0 kg; Volume: 0 m3; Surface supérieure totale: 0 m2; Surface par tonne: 0 m2; Surface nette: 1.1 m2; Hauteur: 1950 mm; Largeur: 3 mm; Longueur: 285.3 mm; sets with these values: 2
Pset_BeamCommon - LoadBearing: no; Reference: F13
BaseQuantities - Length: 285.25 mm; OuterSurfaceArea: 1.14932 m2; NetVolume: 0.00170381 m3; NetWeight: 0 kg

# IfcBeam: PL3*2280, FEUILLURE
In: Undefined
Description: PL3*2280; Material: Undefined/S235-E24
Tekla Commun - Repère de pièce: F15; Repère d'assemblage: F15; Phase: 1; Profil: PL3*2280; Nom: FEUILLURE; sets with these values: 2
Tekla Quantités - Poids: 0 kg; Volume: 0 m3; Surface supérieure totale: 0 m2; Surface par tonne: 0 m2; Surface nette: 1.3 m2; Hauteur: 2280 mm; Largeur: 3 mm; Longueur: 285.3 mm; sets with these values: 2
Pset_BeamCommon - LoadBearing: no; Reference: F15
BaseQuantities - Length: 285.25 mm; OuterSurfaceArea: 1.34353 m2; NetVolume: 0.00199215 m3; NetWeight: 0 kg

# IfcBeam: PL3*2515, SUPPORT CHARGE BARDAG
In: Undefined
Description: PL3*2515; Material: Undefined/S235-E24
Tekla Commun - Repère de pièce: S24; Repère d'assemblage: S24; Phase: 1; Profil: PL3*2515; Nom: SUPPORT CHARGE BARDAG; sets with these values: 2
Tekla Quantités - Poids: 0 kg; Volume: 0 m3; Surface supérieure totale: 0 m2; Surface par tonne: 0 m2; Surface nette: 1.9 m2; Hauteur: 2515 mm; Largeur: 3 mm; Longueur: 378 mm; sets with these values: 2
Pset_BeamCommon - LoadBearing: no; Reference: S24
BaseQuantities - Length: 378 mm; OuterSurfaceArea: 1.94891 m2; NetVolume: 0.00289728 m3; NetWeight: 0 kg

# IfcBeam: PL3*3000 (4)
In: Undefined
Description: PL3*3000; Material: Undefined/S235-E24
Tekla Commun - Repère de pièce: S23; Repère d'assemblage: S23; Phase: 1; Profil: PL3*3000; Nom: SUPPORT CHARGE BARDAG; sets with these values: 2
Tekla Quantités - Poids: 0 kg; Volume: 0 m3; Surface supérieure totale: 0 m2; Surface par tonne: 0 m2; Surface nette: 2.3 m2; Hauteur: 3000 mm; Largeur: 3 mm; Longueur: 378 mm; sets with these values: 2
Pset_BeamCommon - LoadBearing: no; Reference: S23
BaseQuantities - Length: 378 mm; OuterSurfaceArea: 2.3243 m2; NetVolume: 0.003456 m3; NetWeight: 0 kg

# IfcBeam: PL3*3790 (12)
In: Undefined
Description: PL3*3790; Material: Undefined/S235-E24
Tekla Commun - Phase: 1; Profil: PL3*3790; Nom: PANNE SHED; sets with these values: 2
Tekla Quantités - Poids: 0 kg; Volume: 0 m3; Surface par tonne: 0 m2; Hauteur: 3790 mm; Largeur: 3 mm; sets with these values: 2
Pset_BeamCommon - LoadBearing: no
BaseQuantities - NetWeight: 0 kg
Name | Repère de pièce = Repère d'assemblage = Reference | Surface supérieure totale (m2) | Surface nette (m2) | Longueur (mm) | Length (mm) | OuterSurfaceArea (m2) | NetVolume (m3)
2 x PANNE SHED | PN21 | 0 | 3.1 | 394.9 | 394.935 | 3.07365 | 0.00457274
2 x PANNE SHED | PN20 | 0 | 3.1 | 394.9 | 394.862 | 3.07331 | 0.00457224
2 x PANNE SHED | PN21 | 0 | 3.1 | 394.9 | 394.949 | 3.07371 | 0.00457283
2 x PANNE SHED | PN34 | 0.3 | 3.5 | 448.2 | 448.194 | 3.48043 | 0.00518243
2 x PANNE SHED | PN33 | 0.3 | 3.5 | 449.6 | 449.551 | 3.49062 | 0.00519771
2 x PANNE SHED | PN33 | 0.3 | 3.5 | 449.8 | 449.806 | 3.49254 | 0.00520058

# IfcBeam: PL3*3950 (12)
In: Undefined
Description: PL3*3950; Material: Undefined/S235-E24
Tekla Commun - Phase: 1; Profil: PL3*3950; Nom: PANNE SHED; sets with these values: 2
Tekla Quantités - Poids: 0 kg; Volume: 0 m3; Surface par tonne: 0 m2; Hauteur: 3950 mm; Largeur: 3 mm; sets with these values: 2
Pset_BeamCommon - LoadBearing: no
BaseQuantities - NetWeight: 0 kg
Name | Repère de pièce = Repère d'assemblage = Reference | Surface supérieure totale (m2) | Surface nette (m2) | Longueur (mm) | Length (mm) | OuterSurfaceArea (m2) | NetVolume (m3)
PANNE SHED | PN32 | 0 | 3.2 | 394.9 | 394.949 | 3.20336 | 0.00476588
PANNE SHED | PN32 | 0 | 3.2 | 394.9 | 394.935 | 3.2033 | 0.00476578
PANNE SHED | PN31 | 0 | 3.2 | 394.9 | 394.862 | 3.20296 | 0.00476526
PANNE SHED | PN29 | 0.3 | 3.6 | 448.2 | 448.194 | 3.62724 | 0.00540121
PANNE SHED | PN28 | 0.3 | 3.6 | 449.6 | 449.551 | 3.63787 | 0.00541714
PANNE SHED | PN28 | 0.3 | 3.6 | 449.8 | 449.806 | 3.63986 | 0.00542013
PANNE SHED | PN23 | 0 | 3.2 | 394.9 | 394.949 | 3.20336 | 0.00476588
PANNE SHED | PN23 | 0 | 3.2 | 394.9 | 394.935 | 3.2033 | 0.00476578
PANNE SHED | PN22 | 0 | 3.2 | 394.9 | 394.862 | 3.20296 | 0.00476526
PANNE SHED | PN27 | 0.3 | 3.6 | 448.2 | 448.194 | 3.62724 | 0.00540121
PANNE SHED | PN26 | 0.3 | 3.6 | 449.6 | 449.551 | 3.63787 | 0.00541714
PANNE SHED | PN26 | 0.3 | 3.6 | 449.8 | 449.806 | 3.63986 | 0.00542013

# IfcBeam: PL3*70 (24)
In: Undefined
Description: PL3*70; Material: Undefined/S235-E24
Tekla Commun - Finition: GALVA; Repère de pièce: 551; Repère d'assemblage: M18; Phase: 3; Profil: PL3*70; Nom: PLAT MARCHE; sets with these values: 2
Tekla Quantités - Poids: 0 kg; Volume: 0 m3; Surface supérieure totale: 0 m2; Surface par tonne: 0 m2; Surface nette: 0 m2; Hauteur: 70 mm; Largeur: 3 mm; Longueur: 310 mm; sets with these values: 2
Pset_BeamCommon - LoadBearing: no; Reference: 551
BaseQuantities - Length: 310 mm; OuterSurfaceArea: 0.0450382 m2; NetVolume: 0.0000642 m3; NetWeight: 0 kg

# IfcBeam: PL30*990 (19)
In: Undefined
Description: PL30*990; Material: Undefined/S235-E24
Tekla Commun - Finition: GALVA; Phase: 3; Profil: PL30*990; Nom: PALIER; sets with these values: 2
Tekla Quantités - Poids: 0 kg; Volume: 0 m3; Surface par tonne: 0 m2; Hauteur: 990 mm; Largeur: 30 mm; sets with these values: 2
Pset_BeamCommon - LoadBearing: no
BaseQuantities - NetWeight: 0 kg
Name | Repère de pièce = Reference | Repère d'assemblage | Surface supérieure totale (m2) | Surface nette (m2) | Longueur (mm) | Length (mm) | OuterSurfaceArea (m2) | NetVolume (m3)
PALIER | P6 | P6(?) | 0.8 | 1.7 | 810 | 810 | 1.7344 | 0.023892
12 x PALIER | P10 | P10(?) | 1 | 2.2 | 1050 | 1050 | 2.224 | 0.03102
2 x PALIER | P5 | P5(?) | 0.8 | 1.8 | 845 | 845 | 1.8058 | 0.0249315
2 x PALIER | P11 | P11(?) | 1.1 | 2.3 | 1090 | 1090 | 2.3056 | 0.032208
PALIER | P5 | P5(?) | 0.8 | 1.8 | 845 | 845.004 | 1.80581 | 0.0249316
PALIER | P8 | P8(?) | 1 | 2.1 | 990 | 990 | 2.1016 | 0.029238

# IfcBeam: PL30*994 (22)
In: Undefined
Description: PL30*994; Material: Undefined/S235-E24
Tekla Commun - Finition: GALVA; Phase: 3; Profil: PL30*994; Nom: MARCHE; sets with these values: 2
Tekla Quantités - Poids: 0 kg; Volume: 0 m3; Surface supérieure totale: 0.3 m2; Surface par tonne: 0 m2; Surface nette: 0.7 m2; Hauteur: 994 mm; Largeur: 30 mm; sets with these values: 2
Pset_BeamCommon - LoadBearing: no
BaseQuantities - NetWeight: 0 kg
Name | Repère de pièce = Reference | Repère d'assemblage | Longueur (mm) = Length (mm) | OuterSurfaceArea (m2) | NetVolume (m3)
12 x MARCHE | 616 | M18 | 310 | 0.69452 | 0.0092442
10 x MARCHE | 576 | M37 | 290 | 0.65356 | 0.0086478

# IfcBeam: PL4*80 (28)
In: Undefined
Description: PL4*80; Material: Undefined/S235-E24
Tekla Commun - Finition: GALVA; Repère de pièce: 579; Phase: 3; Profil: PL4*80; Nom: BORD COLLERETTE; sets with these values: 2
Tekla Quantités - Poids: 0 kg; Volume: 0 m3; Surface supérieure totale: 0 m2; Surface par tonne: 0 m2; Surface nette: 0 m2; Hauteur: 80 mm; Largeur: 4 mm; Longueur: 200 mm; sets with these values: 2
Pset_BeamCommon - LoadBearing: no; Reference: 579
BaseQuantities - Length: 200 mm; OuterSurfaceArea: 0.03424 m2; NetVolume: 0.000064 m3; NetWeight: 0 kg
Name | Repère d'assemblage
12 x BORD COLLERETTE | P4
16 x BORD COLLERETTE | P3

# IfcBeam: PL5*100 (6)
In: Undefined
Description: PL5*100; Material: Undefined/S235-E24
Tekla Commun - Phase: 1; Profil: PL5*100; Nom: ATTACHE; sets with these values: 2
Tekla Quantités - Poids: 0 kg; Volume: 0 m3; Surface supérieure totale: 0 m2; Surface par tonne: 0 m2; Surface nette: 0 m2; Hauteur: 100 mm; Largeur: 5 mm; sets with these values: 2
Pset_BeamCommon - LoadBearing: no
BaseQuantities - NetWeight: 0 kg
Name | Repère de pièce = Repère d'assemblage = Reference | Longueur (mm) | Length (mm) | OuterSurfaceArea (m2) | NetVolume (m3)
4 x ATTACHE | A77 | 130 | 129.999 | 0.0293499 | 0.0000674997
2 x ATTACHE | A13 | 220 | 220 | 0.04825 | 0.0001125

# IfcBeam: PL5*1120, FEUILLURE
In: Undefined
Description: PL5*1120; Material: Undefined/S235-E24
Tekla Commun - Repère de pièce: F2; Repère d'assemblage: F2; Phase: 1; Profil: PL5*1120; Nom: FEUILLURE; sets with these values: 2
Tekla Quantités - Poids: 0 kg; Volume: 0 m3; Surface supérieure totale: 0 m2; Surface par tonne: 0 m2; Surface nette: 0.5 m2; Hauteur: 1120 mm; Largeur: 5 mm; Longueur: 220 mm; sets with these values: 2
Pset_BeamCommon - LoadBearing: no; Reference: F2
BaseQuantities - Length: 220 mm; OuterSurfaceArea: 0.51745 m2; NetVolume: 0.00126 m3; NetWeight: 0 kg

# IfcBeam: PL5*140 (6)
In: Undefined
Description: PL5*140; Material: Undefined/S235-E24
Tekla Commun - Phase: 1; Profil: PL5*140; Nom: SUPPORT; sets with these values: 2
Tekla Quantités - Poids: 0 kg; Volume: 0 m3; Surface supérieure totale: 0 m2; Surface par tonne: 0 m2; Surface nette: 0 m2; Hauteur: 140 mm; Largeur: 5 mm; sets with these values: 2
Pset_BeamCommon - LoadBearing: no
BaseQuantities - NetWeight: 0 kg
Name | Repère de pièce = Repère d'assemblage = Reference | Longueur (mm) | Length (mm) | OuterSurfaceArea (m2) | NetVolume (m3)
3 x SUPPORT | S19 | 110.5 | 110.529 | 0.0348586 | 0.0000807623
3 x SUPPORT | S17 | 109.7 | 109.681 | 0.0347037 | 0.0000803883

# IfcBeam: PL5*157 (4)
In: Undefined
Description: PL5*157; Material: Undefined/S235-E24
Tekla Commun - Finition: GALVA; Repère de pièce: G32; Repère d'assemblage: G32; Phase: 2; Profil: PL5*157; Nom: GOUSSET; sets with these values: 2
Tekla Quantités - Poids: 0 kg; Volume: 0 m3; Surface supérieure totale: 0 m2; Surface par tonne: 0 m2; Surface nette: 0 m2; Hauteur: 156.7 mm; Largeur: 5 mm; Longueur: 169 mm; sets with these values: 2
Pset_BeamCommon - LoadBearing: no; Reference: G32
BaseQuantities - Length: 168.971 mm; NetWeight: 0 kg
Name | OuterSurfaceArea (m2) | NetVolume (m3)
GOUSSET | 0.0305038 | 0.000069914
GOUSSET | 0.030501 | 0.0000699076
2 x GOUSSET | 0.0305038 | 0.0000699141

# IfcBeam: PL5*1590, FEUILLURE
In: Undefined
Description: PL5*1590; Material: Undefined/S235-E24
Tekla Commun - Repère de pièce: F3; Repère d'assemblage: F3; Phase: 1; Profil: PL5*1590; Nom: FEUILLURE; sets with these values: 2
Tekla Quantités - Poids: 0 kg; Volume: 0 m3; Surface supérieure totale: 0 m2; Surface par tonne: 0 m2; Surface nette: 0.7 m2; Hauteur: 1590 mm; Largeur: 5 mm; Longueur: 220 mm; sets with these values: 2
Pset_BeamCommon - LoadBearing: no; Reference: F3
BaseQuantities - Length: 220 mm; OuterSurfaceArea: 0.73365 m2; NetVolume: 0.00178875 m3; NetWeight: 0 kg

# IfcBeam: PL5*211 (4)
In: Undefined
Description: PL5*211; Material: Undefined/S235-E24
Tekla Commun - Finition: GALVA; Repère de pièce: G30; Repère d'assemblage: G30; Phase: 2; Profil: PL5*211; Nom: GOUSSET; sets with these values: 2
Tekla Quantités - Poids: 0 kg; Volume: 0 m3; Surface supérieure totale: 0 m2; Surface par tonne: 0 m2; Surface nette: 0.1 m2; Hauteur: 211.5 mm; Largeur: 5 mm; Longueur: 235.8 mm; sets with these values: 2
Pset_BeamCommon - LoadBearing: no; Reference: G30
BaseQuantities - NetVolume: 0.000143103 m3; NetWeight: 0 kg
Name | Length (mm) | OuterSurfaceArea (m2)
GOUSSET | 235.796 | 0.0608244
GOUSSET | 235.796 | 0.0608243
2 x GOUSSET | 235.797 | 0.0608245

# IfcBeam: PL5*2110 (2)
In: Undefined
Description: PL5*2110; Material: Undefined/S235-E24
Tekla Commun - Repère de pièce: 144; Repère d'assemblage: PT2; Phase: 1; Profil: PL5*2110; Nom: FEUILLURE; sets with these values: 2
Tekla Quantités - Poids: 0 kg; Volume: 0 m3; Surface supérieure totale: 0 m2; Surface par tonne: 0 m2; Surface nette: 0.7 m2; Hauteur: 2110 mm; Largeur: 5 mm; Longueur: 160 mm; sets with these values: 2
Pset_BeamCommon - LoadBearing: no; Reference: 144
BaseQuantities - Length: 160 mm; OuterSurfaceArea: 0.71905 m2; NetVolume: 0.00174075 m3; NetWeight: 0 kg

# IfcBeam: PL5*2180 (2)
In: Undefined
Description: PL5*2180; Material: Undefined/S235-E24
Tekla Commun - Phase: 1; Profil: PL5*2180; Nom: FEUILLURE; sets with these values: 2
Tekla Quantités - Poids: 0 kg; Volume: 0 m3; Surface supérieure totale: 0 m2; Surface par tonne: 0 m2; Surface nette: 0.9 m2; Hauteur: 2180 mm; Largeur: 5 mm; Longueur: 200 mm; sets with these values: 2
Pset_BeamCommon - LoadBearing: no
BaseQuantities - Length: 200 mm; NetWeight: 0 kg
Name | Repère de pièce = Repère d'assemblage = Reference | OuterSurfaceArea (m2) | NetVolume (m3)
FEUILLURE | F12 | 0.86785 | 0.0021055
FEUILLURE | F7 | 0.89185 | 0.0021685

# IfcBeam: PL5*240 (2)
In: Undefined
Description: PL5*240; Material: Undefined/S235-E24
Tekla Commun - Repère de pièce: A12; Repère d'assemblage: A12; Phase: 1; Profil: PL5*240; Nom: ATTACHE; sets with these values: 2
Tekla Quantités - Poids: 0 kg; Volume: 0 m3; Surface supérieure totale: 0 m2; Surface par tonne: 0 m2; Surface nette: 0.1 m2; Hauteur: 240 mm; Largeur: 5 mm; sets with these values: 2
Pset_BeamCommon - LoadBearing: no; Reference: A12
BaseQuantities - NetWeight: 0 kg
Name | Longueur (mm) | Length (mm) | OuterSurfaceArea (m2) | NetVolume (m3)
ATTACHE | 195.2 | 195.156 | 0.0989167 | 0.000236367
ATTACHE | 195.1 | 195.135 | 0.0989102 | 0.000236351

# IfcBeam: PL5*2500, FEUILLURE
In: Undefined
Description: PL5*2500; Material: Undefined/S235-E24
Tekla Commun - Repère de pièce: 149; Repère d'assemblage: PT2; Phase: 1; Profil: PL5*2500; Nom: FEUILLURE; sets with these values: 2
Tekla Quantités - Poids: 0 kg; Volume: 0 m3; Surface supérieure totale: 0 m2; Surface par tonne: 0 m2; Surface nette: 0.9 m2; Hauteur: 2500 mm; Largeur: 5 mm; Longueur: 160 mm; sets with these values: 2
Pset_BeamCommon - LoadBearing: no; Reference: 149
BaseQuantities - Length: 160 mm; OuterSurfaceArea: 0.85165 m2; NetVolume: 0.0020625 m3; NetWeight: 0 kg

# IfcBeam: PL5*300, GOUSSET
In: Undefined
Description: PL5*300; Material: Undefined/S235-E24
Tekla Commun - Finition: GALVA; Repère de pièce: G31; Repère d'assemblage: G31; Phase: 2; Profil: PL5*300; Nom: GOUSSET; sets with these values: 2
Tekla Quantités - Poids: 0 kg; Volume: 0 m3; Surface supérieure totale: 0 m2; Surface par tonne: 0 m2; Surface nette: 0.2 m2; Hauteur: 300.3 mm; Largeur: 5 mm; Longueur: 353.7 mm; sets with these values: 2
Pset_BeamCommon - LoadBearing: no; Reference: G31
BaseQuantities - Length: 353.658 mm; OuterSurfaceArea: 0.213616 m2; NetVolume: 0.000518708 m3; NetWeight: 0 kg

# IfcBeam: PL5*3000 (8)
In: Undefined
Description: PL5*3000; Material: Undefined/S235-E24
Tekla Commun - Phase: 1; Profil: PL5*3000; Nom: FEUILLURE; sets with these values: 2
Tekla Quantités - Poids: 0 kg; Volume: 0 m3; Surface supérieure totale: 0 m2; Surface par tonne: 0 m2; Hauteur: 3000 mm; Largeur: 5 mm; sets with these values: 2
Pset_BeamCommon - LoadBearing: no
BaseQuantities - NetWeight: 0 kg
Name | Repère de pièce = Repère d'assemblage = Reference | Surface nette (m2) | Longueur (mm) = Length (mm) | OuterSurfaceArea (m2) | NetVolume (m3)
FEUILLURE | F11 | 1.3 | 200 | 1.25425 | 0.003054
FEUILLURE | F9 | 1.2 | 200 | 1.24645 | 0.003033
FEUILLURE | F10 | 1.3 | 200 | 1.25425 | 0.003054
FEUILLURE | F6 | 1.3 | 200 | 1.25425 | 0.003054
3 x FEUILLURE | F1 | 1.4 | 220 | 1.38225 | 0.003375
FEUILLURE | F17 | 1.4 | 220 | 1.36725 | 0.0033375

# IfcBeam: PL5*350, FEUILLURE
In: Undefined
Description: PL5*350; Material: Undefined/S235-E24
Tekla Commun - Repère de pièce: F8; Repère d'assemblage: F8; Phase: 1; Profil: PL5*350; Nom: FEUILLURE; sets with these values: 2
Tekla Quantités - Poids: 0 kg; Volume: 0 m3; Surface supérieure totale: 0 m2; Surface par tonne: 0 m2; Surface nette: 0.1 m2; Hauteur: 350 mm; Largeur: 5 mm; Longueur: 230 mm; sets with these values: 2
Pset_BeamCommon - LoadBearing: no; Reference: F8
BaseQuantities - Length: 230 mm; OuterSurfaceArea: 0.11975 m2; NetVolume: 0.000285 m3; NetWeight: 0 kg

# IfcBeam: PL5*560, FEUILLURE
In: Undefined
Description: PL5*560; Material: Undefined/S235-E24
Tekla Commun - Repère de pièce: F4; Repère d'assemblage: F4; Phase: 1; Profil: PL5*560; Nom: FEUILLURE; sets with these values: 2
Tekla Quantités - Poids: 0 kg; Volume: 0 m3; Surface supérieure totale: 0 m2; Surface par tonne: 0 m2; Surface nette: 0.3 m2; Hauteur: 560 mm; Largeur: 5 mm; Longueur: 235 mm; sets with these values: 2
Pset_BeamCommon - LoadBearing: no; Reference: F4
BaseQuantities - Length: 235 mm; OuterSurfaceArea: 0.2768 m2; NetVolume: 0.000672 m3; NetWeight: 0 kg

# IfcBeam: PL5*581 (2)
In: Undefined
Description: PL5*581; Material: Undefined/S235-E24
Tekla Commun - Repère de pièce: 137; Phase: 1; Profil: PL5*581; Nom: PLATINE; sets with these values: 2
Tekla Quantités - Poids: 0 kg; Volume: 0 m3; Surface supérieure totale: 0 m2; Surface par tonne: 0 m2; Surface nette: 0.1 m2; Hauteur: 581 mm; Largeur: 5 mm; Longueur: 90 mm; sets with these values: 2
Pset_BeamCommon - LoadBearing: no; Reference: 137
BaseQuantities - Length: 90 mm; OuterSurfaceArea: 0.11129 m2; NetVolume: 0.00026145 m3; NetWeight: 0 kg
Name | Repère d'assemblage
PLATINE | PT10
PLATINE | PT12

# IfcBeam: PL5*60 (8)
In: Undefined
Description: PL5*60; Material: Undefined/S235-E24
Tekla Commun - Finition: GALVA; Profil: PL5*60; sets with these values: 2
Tekla Quantités - Poids: 0 kg; Volume: 0 m3; Surface supérieure totale: 0 m2; Surface par tonne: 0 m2; Hauteur: 60 mm; Largeur: 5 mm; sets with these values: 2
Pset_BeamCommon - LoadBearing: no
BaseQuantities - NetWeight: 0 kg
Name | Repère de pièce = Reference | Repère d'assemblage | Phase | Nom | Surface nette (m2) | Longueur (mm) = Length (mm) | OuterSurfaceArea (m2) | NetVolume (m3)
MONTANT | 528 | GC8 | 3 | MONTANT | 0.1 | 967.6 | 0.12382 | 0.00028428
2 x MONTANT | 528 | GC10 | 3 | MONTANT | 0.1 | 967.6 | 0.12382 | 0.00028428
MONTANT | 528 | GC4 | 3 | MONTANT | 0.1 | 967.6 | 0.12382 | 0.00028428
4 x ATTACHE | A16 | A16 | 2 | ATTACHE | 0 | 247 | 0.03336 | 0.0000756

# IfcBeam: PL5*620, FEUILLURE
In: Undefined
Description: PL5*620; Material: Undefined/S235-E24
Tekla Commun - Repère de pièce: F5; Repère d'assemblage: F5; Phase: 1; Profil: PL5*620; Nom: FEUILLURE; sets with these values: 2
Tekla Quantités - Poids: 0 kg; Volume: 0 m3; Surface supérieure totale: 0 m2; Surface par tonne: 0 m2; Surface nette: 0.3 m2; Hauteur: 620 mm; Largeur: 5 mm; Longueur: 230 mm; sets with these values: 2
Pset_BeamCommon - LoadBearing: no; Reference: F5
BaseQuantities - Length: 230 mm; OuterSurfaceArea: 0.25265 m2; NetVolume: 0.0006105 m3; NetWeight: 0 kg

# IfcBeam: PL5*75 (9)
In: Undefined
Description: PL5*75; Material: Undefined/S235-E24
Tekla Commun - Repère de pièce: 161; Repère d'assemblage: PT2; Phase: 1; Profil: PL5*75; Nom: RAIDISSEUR; sets with these values: 2
Tekla Quantités - Poids: 0 kg; Volume: 0 m3; Surface supérieure totale: 0 m2; Surface par tonne: 0 m2; Surface nette: 0 m2; Hauteur: 75 mm; Largeur: 5 mm; Longueur: 169.7 mm; sets with these values: 2
Pset_BeamCommon - LoadBearing: no; Reference: 161
BaseQuantities - Length: 169.7 mm; OuterSurfaceArea: 0.0255279 m2; NetVolume: 0.0000579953 m3; NetWeight: 0 kg

# IfcBeam: PL5*90 (2)
In: Undefined
Description: PL5*90; Material: Undefined/S235-E24
Tekla Commun - Repère de pièce: 138; Phase: 1; Profil: PL5*90; Nom: RAIDISSEUR; sets with these values: 2
Tekla Quantités - Poids: 0 kg; Volume: 0 m3; Surface supérieure totale: 0 m2; Surface par tonne: 0 m2; Surface nette: 0 m2; Hauteur: 90 mm; Largeur: 5 mm; Longueur: 168 mm; sets with these values: 2
Pset_BeamCommon - LoadBearing: no; Reference: 138
BaseQuantities - Length: 168 mm; OuterSurfaceArea: 0.0319028 m2; NetVolume: 0.0000736 m3; NetWeight: 0 kg
Name | Repère d'assemblage
RAIDISSEUR | PT10
RAIDISSEUR | PT12

# IfcBeam: PL50*1250 (3)
In: Undefined
Description: PL50*1250; Material: MISCELLANEOUS/POLYURETHANE
Tekla Commun - Repère de pièce: S55; Repère d'assemblage: S55; Phase: 3; Profil: PL50*1250; Nom: STYRODUR; sets with these values: 2
Tekla Quantités - Poids: 1.9 kg; Volume: 0 m3; Surface supérieure totale: 0 m2; Surface par tonne: 898.7 m2; Surface nette: 1.7 m2; Hauteur: 1250 mm; Largeur: 50 mm; Longueur: 600 mm; sets with these values: 2
Pset_BeamCommon - LoadBearing: no; Reference: S55
BaseQuantities - Length: 600 mm; OuterSurfaceArea: 1.685 m2; NetVolume: 0.0375 m3; NetWeight: 1.875 kg

# IfcBeam: PL50*500 (6)
In: Undefined
Description: PL50*500; Material: CONCRETE/BETON
Tekla Commun - Repère de pièce: DP1; Repère d'assemblage: DP1; Phase: 3; Profil: PL50*500; Nom: DALLE SUR PLOT; sets with these values: 2
Tekla Quantités - Poids: 30 kg; Volume: 0 m3; Surface supérieure totale: 0 m2; Surface par tonne: 20 m2; Surface nette: 0.6 m2; Hauteur: 500 mm; Largeur: 50 mm; Longueur: 500 mm; sets with these values: 2
Pset_BeamCommon - LoadBearing: no; Reference: DP1
BaseQuantities - Length: 500 mm; OuterSurfaceArea: 0.6 m2; NetVolume: 0.0125 m3; NetWeight: 30 kg

# IfcBeam: PL6*120 (3)
In: Undefined
Description: PL6*120; Material: Undefined/S235-E24
Tekla Commun - Repère de pièce: 469; Phase: 1; Profil: PL6*120; Nom: PLATINE; sets with these values: 2
Tekla Quantités - Poids: 0 kg; Volume: 0 m3; Surface supérieure totale: 0 m2; Surface par tonne: 0 m2; Surface nette: 0 m2; Hauteur: 120 mm; Largeur: 6 mm; Longueur: 64 mm; sets with these values: 2
Pset_BeamCommon - LoadBearing: no; Reference: 469
BaseQuantities - Length: 64 mm; OuterSurfaceArea: 0.017568 m2; NetVolume: 0.00004608 m3; NetWeight: 0 kg
Name | Repère d'assemblage
PLATINE | G10
PLATINE | G9
PLATINE | G8

# IfcBeam: PL6*150 (8)
In: Undefined
Description: PL6*150; Material: Undefined/S235-E24
Tekla Commun - Repère de pièce: A68; Repère d'assemblage: A68; Phase: 1; Profil: PL6*150; Nom: ATTACHE; sets with these values: 2
Tekla Quantités - Poids: 0 kg; Volume: 0 m3; Surface supérieure totale: 0 m2; Surface par tonne: 0 m2; Surface nette: 0.1 m2; Hauteur: 150 mm; Largeur: 6 mm; sets with these values: 2
Pset_BeamCommon - LoadBearing: no; Reference: A68
BaseQuantities - NetWeight: 0 kg
Name | Longueur (mm) = Length (mm) | OuterSurfaceArea (m2) | NetVolume (m3)
4 x ATTACHE | 185 | 0.0523029 | 0.00014595
4 x ATTACHE | 184.5 | 0.0521469 | 0.0001455

# IfcBeam: PL6*50 (30)
In: Undefined
Description: PL6*50; Material: Undefined/S235-E24
Tekla Commun - Phase: 1; Profil: PL6*50; Nom: ATTACHE; sets with these values: 2
Tekla Quantités - Poids: 0 kg; Volume: 0 m3; Surface supérieure totale: 0 m2; Surface par tonne: 0 m2; Surface nette: 0 m2; Hauteur: 50 mm; Largeur: 6 mm; sets with these values: 2
Pset_BeamCommon - LoadBearing: no
BaseQuantities - NetWeight: 0 kg
Name | Repère de pièce = Repère d'assemblage = Reference | Longueur (mm) | Length (mm) | OuterSurfaceArea (m2) | NetVolume (m3)
2 x ATTACHE | A67 | 330 | 330.012 | 0.0382125 | 0.000100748
5 x ATTACHE | A62 | 276.4 | 276.371 | 0.0328768 | 0.0000864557
ATTACHE | A66 | 274.4 | 274.384 | 0.0320245 | 0.0000841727
2 x ATTACHE | A65 | 275.7 | 275.651 | 0.0321241 | 0.0000844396
ATTACHE | A66 | 274.4 | 274.394 | 0.0320255 | 0.0000841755
8 x ATTACHE | A64 | 279 | 279.037 | 0.0325456 | 0.0000855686
11 x ATTACHE | A63 | 280 | 280.012 | 0.0326125 | 0.0000857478

# IfcBeam: PL60*10 (4)
In: Undefined
Description: PL60*10; Material: Undefined/S235-E24
Tekla Commun - Repère de pièce: A75; Repère d'assemblage: A75; Phase: 1; Profil: PL60*10; Nom: ATTACHE; sets with these values: 2
Tekla Quantités - Poids: 0 kg; Volume: 0 m3; Surface supérieure totale: 0 m2; Surface par tonne: 0 m2; Surface nette: 0 m2; Hauteur: 60 mm; Largeur: 10 mm; Longueur: 320 mm; sets with these values: 2
Pset_BeamCommon - LoadBearing: no; Reference: A75
BaseQuantities - Length: 320 mm; OuterSurfaceArea: 0.0474 m2; NetVolume: 0.000198 m3; NetWeight: 0 kg

# IfcBeam: PL8*160 (14)
In: Undefined
Description: PL8*160; Material: Undefined/S235-E24
Tekla Commun - Finition: GALVA; Repère de pièce: 527; Phase: 3; Profil: PL8*160; Nom: PLATINE; sets with these values: 2
Tekla Quantités - Poids: 0 kg; Volume: 0 m3; Surface supérieure totale: 0 m2; Surface par tonne: 0 m2; Surface nette: 0.1 m2; Hauteur: 160 mm; Largeur: 8 mm; Longueur: 210 mm; sets with these values: 2
Pset_BeamCommon - LoadBearing: no; Reference: 527
BaseQuantities - Length: 210 mm; OuterSurfaceArea: 0.0731198 m2; NetVolume: 0.000268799 m3; NetWeight: 0 kg
Name | Repère d'assemblage
6 x PLATINE | P4
8 x PLATINE | P3

# IfcBeam: PL8*80 (6)
In: Undefined
Description: PL8*80; Material: Undefined/S235-E24
Tekla Commun - Finition: GALVA; Repère de pièce: A80; Repère d'assemblage: A80; Phase: 3; Profil: PL8*80; Nom: ATTACHE; sets with these values: 2
Tekla Quantités - Poids: 0 kg; Volume: 0 m3; Surface supérieure totale: 0 m2; Surface par tonne: 0 m2; Surface nette: 0 m2; Hauteur: 80 mm; Largeur: 8 mm; Longueur: 234 mm; sets with these values: 2
Pset_BeamCommon - LoadBearing: no; Reference: A80
BaseQuantities - Length: 233.997 mm; OuterSurfaceArea: 0.0438714 m2; NetVolume: 0.000154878 m3; NetWeight: 0 kg

# IfcBeam: PL8*90 (20)
In: Undefined
Description: PL8*90; Material: Undefined/S235-E24
Tekla Commun - Finition: GALVA; Phase: 3; Profil: PL8*90; Nom: PLAT LIMON; sets with these values: 2
Tekla Quantités - Poids: 0 kg; Volume: 0 m3; Surface supérieure totale: 0 m2; Surface par tonne: 0 m2; Hauteur: 90 mm; Largeur: 8 mm; sets with these values: 2
Pset_BeamCommon - LoadBearing: no
BaseQuantities - NetWeight: 0 kg
Name | Repère de pièce = Reference | Repère d'assemblage | Surface nette (m2) | Longueur (mm) | Length (mm) | OuterSurfaceArea (m2) | NetVolume (m3)
3 x PLAT LIMON | 561 | L90 | 0.1 | 285.4 | 285.371 | 0.0573727 | 0.000205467
3 x PLAT LIMON | 552 | L90 | 0 | 115 | 114.997 | 0.0239795 | 0.000082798
3 x PLAT LIMON | 561 | L89 | 0.1 | 285.4 | 285.371 | 0.0573727 | 0.000205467
3 x PLAT LIMON | 552 | L89 | 0 | 115 | 114.997 | 0.0239795 | 0.000082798
PLAT LIMON | 524 | L33(?) | 0 | 237.7 | 237.733 | 0.0480357 | 0.000171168
PLAT LIMON | 523 | L33(?) | 0 | 147 | 147 | 0.030252 | 0.00010584
PLAT LIMON | 524 | L63 | 0 | 237.7 | 237.733 | 0.0480357 | 0.000171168
PLAT LIMON | 523 | L63 | 0 | 147 | 147 | 0.030252 | 0.00010584
PLAT LIMON | 524 | L5(?) | 0 | 237.7 | 237.733 | 0.0480357 | 0.000171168
PLAT LIMON | 523 | L5(?) | 0 | 147 | 147 | 0.030252 | 0.00010584
PLAT LIMON | 524 | L75(?) | 0 | 237.7 | 237.733 | 0.0480357 | 0.000171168
PLAT LIMON | 523 | L75(?) | 0 | 147 | 147 | 0.030252 | 0.00010584

# IfcBeam: TOLE10*149 (2)
In: Undefined
Description: TOLE10*149; Material: Undefined/S235-E24
Tekla Commun - Finition: GALVA; Repère de pièce: 590; Repère d'assemblage: C12; Phase: 1; Profil: TOLE10*149; Nom: RAIDISSEUR; sets with these values: 2
Tekla Quantités - Poids: 0 kg; Volume: 0 m3; Surface supérieure totale: 0 m2; Surface par tonne: 0 m2; Surface nette: 0 m2; Hauteur: 149 mm; Largeur: 10 mm; Longueur: 200 mm; sets with these values: 2
Pset_BeamCommon - LoadBearing: no; Reference: 590
BaseQuantities - Length: 200 mm; OuterSurfaceArea: 0.045811 m2; NetVolume: 0.000199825 m3; NetWeight: 0 kg

# IfcBeam: TOLE10*180 (2)
In: Undefined
Description: TOLE10*180; Material: Undefined/S235-E24
Tekla Commun - Repère de pièce: 362; Phase: 2; Profil: TOLE10*180; Nom: PLATINE; sets with these values: 2
Tekla Quantités - Poids: 0 kg; Volume: 0 m3; Surface supérieure totale: 0 m2; Surface par tonne: 0 m2; Surface nette: 0.1 m2; Hauteur: 180 mm; Largeur: 10 mm; Longueur: 250 mm; sets with these values: 2
Pset_BeamCommon - LoadBearing: no; Reference: 362
BaseQuantities - Length: 250 mm; OuterSurfaceArea: 0.0909042 m2; NetVolume: 0.000414 m3; NetWeight: 0 kg
Name | Repère d'assemblage
PLATINE | PT13
PLATINE | PT11

# IfcBeam: TOLE10*192 (24)
In: Undefined
Description: TOLE10*192; Material: Undefined/S235-E24
Tekla Commun - Repère de pièce: 361; Phase: 1; Profil: TOLE10*192; Nom: PLAT; sets with these values: 2
Tekla Quantités - Poids: 0 kg; Volume: 0 m3; Surface supérieure totale: 0 m2; Surface par tonne: 0 m2; Surface nette: 0.1 m2; Hauteur: 192.3 mm; Largeur: 10 mm; Longueur: 140 mm; sets with these values: 2
Pset_BeamCommon - LoadBearing: no; Reference: 361
BaseQuantities - Length: 140 mm; OuterSurfaceArea: 0.0558591 m2; NetVolume: 0.000247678 m3; NetWeight: 0 kg
Name | Repère d'assemblage
PLAT | M34
PLAT | M7
2 x PLAT | M8
2 x PLAT | M27
PLAT | M33
PLAT | M5
2 x PLAT | M6
2 x PLAT | M26
2 x PLAT | M29
2 x PLAT | M28
2 x PLAT | M4
2 x PLAT | M24
PLAT | M30
PLAT | M3
2 x PLAT | M25

# IfcBeam: TOLE10*260, PLATINE
In: Undefined
Description: TOLE10*260; Material: Undefined/S235-E24
Tekla Commun - Repère de pièce: 358; Repère d'assemblage: B5; Phase: 1; Profil: TOLE10*260; Nom: PLATINE; sets with these values: 2
Tekla Quantités - Poids: 0 kg; Volume: 0 m3; Surface supérieure totale: 0 m2; Surface par tonne: 0 m2; Surface nette: 0.2 m2; Hauteur: 260 mm; Largeur: 10 mm; Longueur: 316.7 mm; sets with these values: 2
Pset_BeamCommon - LoadBearing: no; Reference: 358
BaseQuantities - Length: 316.727 mm; OuterSurfaceArea: 0.165061 m2; NetVolume: 0.00077349 m3; NetWeight: 0 kg

# IfcBeam: TOLE10*417 (2)
In: Undefined
Description: TOLE10*417; Material: Undefined/S235-E24
Tekla Commun - Repère de pièce: 357; Phase: 1; Profil: TOLE10*417; Nom: JARRET; sets with these values: 2
Tekla Quantités - Poids: 0 kg; Volume: 0 m3; Surface supérieure totale: 0 m2; Surface par tonne: 0 m2; Surface nette: 0.7 m2; Hauteur: 416.5 mm; Largeur: 10 mm; Longueur: 1465.4 mm; sets with these values: 2
Pset_BeamCommon - LoadBearing: no; Reference: 357
BaseQuantities - Length: 1465.39 mm; OuterSurfaceArea: 0.688162 m2; NetVolume: 0.00327529 m3; NetWeight: 0 kg
Name | Repère d'assemblage
JARRET | T7
JARRET | T1

# IfcBeam: TOLE10*60 (5)
In: Undefined
Description: TOLE10*60; Material: Undefined/S235-E24
Tekla Commun - Finition: GALVA; Repère de pièce: 591; Repère d'assemblage: C11; Phase: 1; Profil: TOLE10*60; Nom: RAIDISSEUR; sets with these values: 2
Tekla Quantités - Poids: 0 kg; Volume: 0 m3; Surface supérieure totale: 0 m2; Surface par tonne: 0 m2; Surface nette: 0 m2; Hauteur: 60 mm; Largeur: 10 mm; Longueur: 200 mm; sets with these values: 2
Pset_BeamCommon - LoadBearing: no; Reference: 591
BaseQuantities - Length: 200 mm; OuterSurfaceArea: 0.0237557 m2; NetVolume: 0.00009525 m3; NetWeight: 0 kg

# IfcBeam: TOLE15*250 (7)
In: Undefined
Description: TOLE15*250; Material: Undefined/S235-E24
Tekla Commun - Finition: GALVA; Phase: 1; Profil: TOLE15*250; Nom: CONSOLE; sets with these values: 2
Tekla Quantités - Poids: 0 kg; Volume: 0 m3; Surface supérieure totale: 0 m2; Surface par tonne: 0 m2; Hauteur: 250 mm; Largeur: 15 mm; sets with these values: 2
Pset_BeamCommon - LoadBearing: no
BaseQuantities - NetWeight: 0 kg
Name | Repère de pièce = Reference | Repère d'assemblage | Surface nette (m2) | Longueur (mm) = Length (mm) | OuterSurfaceArea (m2) | NetVolume (m3)
2 x CONSOLE | 597 | C12 | 0.3 | 599 | 0.255009 | 0.001737
5 x CONSOLE | 596 | C11 | 0.2 | 510 | 0.207839 | 0.00140325

# IfcBeam: TOLE3*70 (20)
In: Undefined
Description: TOLE3*70; Material: Undefined/S235-E24
Tekla Commun - Finition: GALVA; Repère de pièce: 580; Repère d'assemblage: M37; Phase: 3; Profil: TOLE3*70; Nom: PLAT MARCHE; sets with these values: 2
Tekla Quantités - Poids: 0 kg; Volume: 0 m3; Surface supérieure totale: 0 m2; Surface par tonne: 0 m2; Surface nette: 0 m2; Hauteur: 70 mm; Largeur: 3 mm; Longueur: 290 mm; sets with these values: 2
Pset_BeamCommon - LoadBearing: no; Reference: 580
BaseQuantities - Length: 290 mm; OuterSurfaceArea: 0.0421182 m2; NetVolume: 0.00006 m3; NetWeight: 0 kg

# IfcBeam: TOLE30*910 (12)
In: Undefined
Description: TOLE30*910; Material: Undefined/S235-E24
Tekla Commun - Phase: 1; Profil: TOLE30*910; Nom: CAILLEBOTIS; sets with these values: 2
Tekla Quantités - Poids: 0 kg; Volume: 0 m3; Surface supérieure totale: 1.1 m2; Surface par tonne: 0 m2; Surface nette: 2.3 m2; Hauteur: 910 mm; Largeur: 30 mm; Longueur: 1180 mm; sets with these values: 2
Pset_BeamCommon - LoadBearing: no
BaseQuantities - Length: 1179.99 mm; NetWeight: 0 kg
Name | Repère de pièce = Repère d'assemblage = Reference | OuterSurfaceArea (m2) | NetVolume (m3)
CAILLEBOTIS | CA4 | 2.28232 | 0.0318393
11 x CAILLEBOTIS | CA3 | 2.29605 | 0.0320453

# IfcBeam: TOLE30*940 (24)
In: Undefined
Description: TOLE30*940; Material: Undefined/S235-E24
Tekla Commun - Repère de pièce: CA1; Repère d'assemblage: CA1; Phase: 1; Profil: TOLE30*940; Nom: CAILLEBOTIS; sets with these values: 2
Tekla Quantités - Poids: 0 kg; Volume: 0 m3; Surface supérieure totale: 1.1 m2; Surface par tonne: 0 m2; Surface nette: 2.4 m2; Hauteur: 940 mm; Largeur: 30 mm; Longueur: 1180 mm; sets with these values: 2
Pset_BeamCommon - LoadBearing: no; Reference: CA1
BaseQuantities - Length: 1179.99 mm; OuterSurfaceArea: 2.36865 m2; NetVolume: 0.0331073 m3; NetWeight: 0 kg

# IfcBeam: TOLE30*980 (12)
In: Undefined
Description: TOLE30*980; Material: Undefined/S235-E24
Tekla Commun - Repère de pièce: CA2; Repère d'assemblage: CA2; Phase: 1; Profil: TOLE30*980; Nom: CAILLEBOTIS; sets with these values: 2
Tekla Quantités - Poids: 0 kg; Volume: 0 m3; Surface supérieure totale: 1.2 m2; Surface par tonne: 0 m2; Surface nette: 2.5 m2; Hauteur: 980 mm; Largeur: 30 mm; Longueur: 1180 mm; sets with these values: 2
Pset_BeamCommon - LoadBearing: no; Reference: CA2
BaseQuantities - Length: 1179.99 mm; OuterSurfaceArea: 2.46545 m2; NetVolume: 0.0345232 m3; NetWeight: 0 kg

# IfcBeam: TOLE6*100, GOUSSET
In: Undefined
Description: TOLE6*100; Material: Undefined/S235-E24
Tekla Commun - Repère de pièce: 439; Repère d'assemblage: G10; Phase: 1; Profil: TOLE6*100; Nom: GOUSSET; sets with these values: 2
Tekla Quantités - Poids: 0 kg; Volume: 0 m3; Surface supérieure totale: 0 m2; Surface par tonne: 0 m2; Surface nette: 0 m2; Hauteur: 100.3 mm; Largeur: 6 mm; Longueur: 199.9 mm; sets with these values: 2
Pset_BeamCommon - LoadBearing: no; Reference: 439
BaseQuantities - Length: 199.86 mm; OuterSurfaceArea: 0.0241864 m2; NetVolume: 0.0000638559 m3; NetWeight: 0 kg

# IfcBeam: TOLE6*109, GOUSSET
In: Undefined
Description: TOLE6*109; Material: Undefined/S235-E24
Tekla Commun - Repère de pièce: 438; Repère d'assemblage: G9; Phase: 1; Profil: TOLE6*109; Nom: GOUSSET; sets with these values: 2
Tekla Quantités - Poids: 0 kg; Volume: 0 m3; Surface supérieure totale: 0 m2; Surface par tonne: 0 m2; Surface nette: 0 m2; Hauteur: 109 mm; Largeur: 6 mm; Longueur: 183.6 mm; sets with these values: 2
Pset_BeamCommon - LoadBearing: no; Reference: 438
BaseQuantities - Length: 183.622 mm; OuterSurfaceArea: 0.0243077 m2; NetVolume: 0.0000645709 m3; NetWeight: 0 kg

# IfcBeam: TOLE6*113, GOUSSET
In: Undefined
Description: TOLE6*113; Material: Undefined/S235-E24
Tekla Commun - Repère de pièce: 437; Repère d'assemblage: G8; Phase: 1; Profil: TOLE6*113; Nom: GOUSSET; sets with these values: 2
Tekla Quantités - Poids: 0 kg; Volume: 0 m3; Surface supérieure totale: 0 m2; Surface par tonne: 0 m2; Surface nette: 0 m2; Hauteur: 112.8 mm; Largeur: 6 mm; Longueur: 168.2 mm; sets with these values: 2
Pset_BeamCommon - LoadBearing: no; Reference: 437
BaseQuantities - Length: 168.223 mm; OuterSurfaceArea: 0.023904 m2; NetVolume: 0.0000636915 m3; NetWeight: 0 kg

# IfcBeam: TOLE6*164 (8)
In: Undefined
Description: TOLE6*164; Material: Undefined/S235-E24
Tekla Commun - Repère de pièce: G18; Repère d'assemblage: G18; Phase: 1; Profil: TOLE6*164; Nom: GOUSSET; sets with these values: 2
Tekla Quantités - Poids: 0 kg; Volume: 0 m3; Surface supérieure totale: 0 m2; Surface par tonne: 0 m2; Surface nette: 0.1 m2; Hauteur: 163.6 mm; Largeur: 6 mm; Longueur: 239.7 mm; sets with these values: 2
Pset_BeamCommon - LoadBearing: no; Reference: G18
BaseQuantities - Length: 239.671 mm; OuterSurfaceArea: 0.0541094 m2; NetVolume: 0.000150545 m3; NetWeight: 0 kg

# IfcBeam: TOLE6*167, GOUSSET
In: Undefined
Description: TOLE6*167; Material: Undefined/S235-E24
Tekla Commun - Repère de pièce: G5; Repère d'assemblage: G5; Phase: 1; Profil: TOLE6*167; Nom: GOUSSET; sets with these values: 2
Tekla Quantités - Poids: 0 kg; Volume: 0 m3; Surface supérieure totale: 0 m2; Surface par tonne: 0 m2; Surface nette: 0 m2; Hauteur: 166.7 mm; Largeur: 6 mm; Longueur: 203.6 mm; sets with these values: 2
Pset_BeamCommon - LoadBearing: no; Reference: G5
BaseQuantities - Length: 203.578 mm; OuterSurfaceArea: 0.0378729 m2; NetVolume: 0.000103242 m3; NetWeight: 0 kg

# IfcBeam: TOLE6*171, GOUSSET
In: Undefined
Description: TOLE6*171; Material: Undefined/S235-E24
Tekla Commun - Repère de pièce: G6; Repère d'assemblage: G6; Phase: 1; Profil: TOLE6*171; Nom: GOUSSET; sets with these values: 2
Tekla Quantités - Poids: 0 kg; Volume: 0 m3; Surface supérieure totale: 0 m2; Surface par tonne: 0 m2; Surface nette: 0 m2; Hauteur: 171.3 mm; Largeur: 6 mm; Longueur: 185.5 mm; sets with these values: 2
Pset_BeamCommon - LoadBearing: no; Reference: G6
BaseQuantities - Length: 185.499 mm; OuterSurfaceArea: 0.0373877 m2; NetVolume: 0.000102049 m3; NetWeight: 0 kg

# IfcBeam: TOLE6*175 (10)
In: Undefined
Description: TOLE6*175; Material: Undefined/S235-E24
Tekla Commun - Phase: 1; Profil: TOLE6*175; Nom: GOUSSET; sets with these values: 2
Tekla Quantités - Poids: 0 kg; Volume: 0 m3; Surface supérieure totale: 0 m2; Surface par tonne: 0 m2; Largeur: 6 mm; sets with these values: 2
Pset_BeamCommon - LoadBearing: no
BaseQuantities - NetWeight: 0 kg
Name | Repère de pièce = Repère d'assemblage = Reference | Surface nette (m2) | Hauteur (mm) | Longueur (mm) | Length (mm) | OuterSurfaceArea (m2) | NetVolume (m3)
2 x GOUSSET | G20 | 0.1 | 174.7 | 308.8 | 308.793 | 0.0956274 | 0.000271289
GOUSSET | G20 | 0.1 | 174.7 | 308.8 | 308.795 | 0.0956287 | 0.000271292
4 x GOUSSET | G26 | 0.2 | 174.7 | 517.6 | 517.59 | 0.153031 | 0.000437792
2 x GOUSSET | G26 | 0.2 | 174.7 | 517.6 | 517.589 | 0.15303 | 0.00043779
GOUSSET | G7 | 0 | 175.1 | 165.1 | 165.14 | 0.0368183 | 0.000100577

# IfcBeam: TOLE6*178 (11)
In: Undefined
Description: TOLE6*178; Material: Undefined/S235-E24
Tekla Commun - Phase: 1; Profil: TOLE6*178; Nom: GOUSSET; sets with these values: 2
Tekla Quantités - Poids: 0 kg; Volume: 0 m3; Surface supérieure totale: 0 m2; Surface par tonne: 0 m2; Surface nette: 0.1 m2; Largeur: 6 mm; sets with these values: 2
Pset_BeamCommon - LoadBearing: no
BaseQuantities - NetWeight: 0 kg
Name | Repère de pièce = Repère d'assemblage = Reference | Hauteur (mm) | Longueur (mm) | Length (mm) | OuterSurfaceArea (m2) | NetVolume (m3)
4 x GOUSSET | G22 | 177.6 | 309.3 | 309.316 | 0.0970728 | 0.000275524
7 x GOUSSET | G14 | 178.2 | 315.7 | 315.682 | 0.0777998 | 0.000218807

# IfcBeam: TOLE6*182 (4)
In: Undefined
Description: TOLE6*182; Material: Undefined/S235-E24
Tekla Commun - Repère de pièce: G21; Repère d'assemblage: G21; Phase: 1; Profil: TOLE6*182; Nom: GOUSSET; sets with these values: 2
Tekla Quantités - Poids: 0 kg; Volume: 0 m3; Surface supérieure totale: 0 m2; Surface par tonne: 0 m2; Surface nette: 0.1 m2; Hauteur: 181.7 mm; Largeur: 6 mm; Longueur: 304.7 mm; sets with these values: 2
Pset_BeamCommon - LoadBearing: no; Reference: G21
BaseQuantities - Length: 304.744 mm; OuterSurfaceArea: 0.0973188 m2; NetVolume: 0.000276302 m3; NetWeight: 0 kg

# IfcBeam: TOLE6*184, GOUSSET
In: Undefined
Description: TOLE6*184; Material: Undefined/S235-E24
Tekla Commun - Repère de pièce: G13; Repère d'assemblage: G13; Phase: 1; Profil: TOLE6*184; Nom: GOUSSET; sets with these values: 2
Tekla Quantités - Poids: 0 kg; Volume: 0 m3; Surface supérieure totale: 0 m2; Surface par tonne: 0 m2; Surface nette: 0.1 m2; Hauteur: 184.1 mm; Largeur: 6 mm; Longueur: 316.3 mm; sets with these values: 2
Pset_BeamCommon - LoadBearing: no; Reference: G13
BaseQuantities - Length: 316.283 mm; OuterSurfaceArea: 0.100503 m2; NetVolume: 0.000285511 m3; NetWeight: 0 kg

# IfcBeam: TOLE6*190 (8)
In: Undefined
Description: TOLE6*190; Material: Undefined/S235-E24
Tekla Commun - Phase: 1; Profil: TOLE6*190; Nom: GOUSSET; sets with these values: 2
Tekla Quantités - Poids: 0 kg; Volume: 0 m3; Surface supérieure totale: 0 m2; Surface par tonne: 0 m2; Hauteur: 190 mm; Largeur: 6 mm; sets with these values: 2
Pset_BeamCommon - LoadBearing: no
BaseQuantities - NetWeight: 0 kg
Name | Repère de pièce = Repère d'assemblage = Reference | Surface nette (m2) | Longueur (mm) | Length (mm) | OuterSurfaceArea (m2) | NetVolume (m3)
GOUSSET | G4 | 0.1 | 448 | 448.047 | 0.149486 | 0.000427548
GOUSSET | G2 | 0.3 | 832.1 | 832.091 | 0.271252 | 0.000781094
2 x GOUSSET | G2 | 0.3 | 832.1 | 832.091 | 0.271253 | 0.000781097
3 x GOUSSET | G1 | 0.3 | 832.1 | 832.091 | 0.270463 | 0.000778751
GOUSSET | G3 | 0.1 | 448 | 448.047 | 0.149088 | 0.000426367

# IfcBeam: TOLE6*196 (7)
In: Undefined
Description: TOLE6*196; Material: Undefined/S235-E24
Tekla Commun - Repère de pièce: G12; Repère d'assemblage: G12; Phase: 1; Profil: TOLE6*196; Nom: GOUSSET; sets with these values: 2
Tekla Quantités - Poids: 0 kg; Volume: 0 m3; Surface supérieure totale: 0 m2; Surface par tonne: 0 m2; Surface nette: 0.1 m2; Hauteur: 195.7 mm; Largeur: 6 mm; Longueur: 296.9 mm; sets with these values: 2
Pset_BeamCommon - LoadBearing: no; Reference: G12
BaseQuantities - OuterSurfaceArea: 0.0787037 m2; NetVolume: 0.000221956 m3; NetWeight: 0 kg
Name | Length (mm)
3 x GOUSSET | 296.908
4 x GOUSSET | 296.906

# IfcBeam: TOLE6*197 (2)
In: Undefined
Description: TOLE6*197; Material: Undefined/S235-E24
Tekla Commun - Repère de pièce: G19; Repère d'assemblage: G19; Phase: 1; Profil: TOLE6*197; Nom: GOUSSET; sets with these values: 2
Tekla Quantités - Poids: 0 kg; Volume: 0 m3; Surface supérieure totale: 0 m2; Surface par tonne: 0 m2; Surface nette: 0.1 m2; Hauteur: 196.8 mm; Largeur: 6 mm; Longueur: 200 mm; sets with these values: 2
Pset_BeamCommon - LoadBearing: no; Reference: G19
BaseQuantities - Length: 200 mm; OuterSurfaceArea: 0.067384 m2; NetVolume: 0.000189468 m3; NetWeight: 0 kg

# IfcBeam: TOLE6*219, GOUSSET
In: Undefined
Description: TOLE6*219; Material: Undefined/S235-E24
Tekla Commun - Repère de pièce: G15; Repère d'assemblage: G15; Phase: 1; Profil: TOLE6*219; Nom: GOUSSET; sets with these values: 2
Tekla Quantités - Poids: 0 kg; Volume: 0 m3; Surface supérieure totale: 0 m2; Surface par tonne: 0 m2; Surface nette: 0.1 m2; Hauteur: 218.7 mm; Largeur: 6 mm; Longueur: 305.5 mm; sets with these values: 2
Pset_BeamCommon - LoadBearing: no; Reference: G15
BaseQuantities - Length: 305.472 mm; OuterSurfaceArea: 0.107874 m2; NetVolume: 0.000307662 m3; NetWeight: 0 kg

# IfcBeam: TOLE6*259 (5)
In: Undefined
Description: TOLE6*259; Material: Undefined/S235-E24
Tekla Commun - Phase: 1; Profil: TOLE6*259; Nom: GOUSSET; sets with these values: 2
Tekla Quantités - Poids: 0 kg; Volume: 0 m3; Surface supérieure totale: 0 m2; Surface par tonne: 0 m2; Largeur: 6 mm; sets with these values: 2
Pset_BeamCommon - LoadBearing: no
BaseQuantities - NetWeight: 0 kg
Name | Repère de pièce = Repère d'assemblage = Reference | Surface nette (m2) | Hauteur (mm) | Longueur (mm) | Length (mm) | OuterSurfaceArea (m2) | NetVolume (m3)
GOUSSET | G24 | 0.3 | 258.8 | 560.1 | 560.056 | 0.254572 | 0.000737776
3 x GOUSSET | G16 | 0.2 | 258.6 | 541.4 | 541.372 | 0.207336 | 0.00059834
GOUSSET | G16 | 0.2 | 258.5 | 541.5 | 541.503 | 0.20733 | 0.00059832

# IfcBeam: TOLE6*261, GOUSSET
In: Undefined
Description: TOLE6*261; Material: Undefined/S235-E24
Tekla Commun - Repère de pièce: G25; Repère d'assemblage: G25; Phase: 1; Profil: TOLE6*261; Nom: GOUSSET; sets with these values: 2
Tekla Quantités - Poids: 0 kg; Volume: 0 m3; Surface supérieure totale: 0 m2; Surface par tonne: 0 m2; Surface nette: 0.3 m2; Hauteur: 261.2 mm; Largeur: 6 mm; Longueur: 559.5 mm; sets with these values: 2
Pset_BeamCommon - LoadBearing: no; Reference: G25
BaseQuantities - Length: 559.453 mm; OuterSurfaceArea: 0.258276 m2; NetVolume: 0.000748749 m3; NetWeight: 0 kg

# IfcBeam: TOLE6*262 (4)
In: Undefined
Description: TOLE6*262; Material: Undefined/S235-E24
Tekla Commun - Repère de pièce: G23; Repère d'assemblage: G23; Phase: 1; Profil: TOLE6*262; Nom: GOUSSET; sets with these values: 2
Tekla Quantités - Poids: 0 kg; Volume: 0 m3; Surface supérieure totale: 0 m2; Surface par tonne: 0 m2; Surface nette: 0.3 m2; Hauteur: 261.6 mm; Largeur: 6 mm; Longueur: 563.2 mm; sets with these values: 2
Pset_BeamCommon - LoadBearing: no; Reference: G23
BaseQuantities - Length: 563.241 mm; OuterSurfaceArea: 0.260968 m2; NetVolume: 0.000756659 m3; NetWeight: 0 kg

# IfcBeam: TOLE6*272 (4)
In: Undefined
Description: TOLE6*272; Material: Undefined/S235-E24
Tekla Commun - Repère de pièce: G17; Repère d'assemblage: G17; Phase: 1; Profil: TOLE6*272; Nom: GOUSSET; sets with these values: 2
Tekla Quantités - Poids: 0 kg; Volume: 0 m3; Surface supérieure totale: 0 m2; Surface par tonne: 0 m2; Surface nette: 0.2 m2; Hauteur: 272.3 mm; Largeur: 6 mm; Longueur: 458.3 mm; sets with these values: 2
Pset_BeamCommon - LoadBearing: no; Reference: G17
BaseQuantities - Length: 458.306 mm; OuterSurfaceArea: 0.188136 m2; NetVolume: 0.00054273 m3; NetWeight: 0 kg

# IfcBeam: TOLE6*281 (4)
In: Undefined
Description: TOLE6*281; Material: Undefined/S235-E24
Tekla Commun - Repère de pièce: G27; Repère d'assemblage: G27; Phase: 1; Profil: TOLE6*281; Nom: GOUSSET; sets with these values: 2
Tekla Quantités - Poids: 0 kg; Volume: 0 m3; Surface supérieure totale: 0 m2; Surface par tonne: 0 m2; Surface nette: 0.1 m2; Hauteur: 280.7 mm; Largeur: 6 mm; Longueur: 272.3 mm; sets with these values: 2
Pset_BeamCommon - LoadBearing: no; Reference: G27
BaseQuantities - Length: 272.302 mm; OuterSurfaceArea: 0.108188 m2; NetVolume: 0.000308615 m3; NetWeight: 0 kg

# IfcBeam: TOLE6*36 (3)
In: Undefined
Description: TOLE6*36; Material: Undefined/S235-E24
Tekla Commun - Repère de pièce: P2; Repère d'assemblage: P2; Phase: 1; Profil: TOLE6*36; Nom: PLAQUETTE; sets with these values: 2
Tekla Quantités - Poids: 0 kg; Volume: 0 m3; Surface supérieure totale: 0 m2; Surface par tonne: 0 m2; Surface nette: 0 m2; Hauteur: 36 mm; Largeur: 6 mm; Longueur: 36 mm; sets with these values: 2
Pset_BeamCommon - LoadBearing: no; Reference: P2
BaseQuantities - Length: 36 mm; OuterSurfaceArea: 0.00269587 m2; NetVolume: 0.00000605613 m3; NetWeight: 0 kg

# IfcBeam: TOLE6*60 (24)
In: Undefined
Description: TOLE6*60; Material: Undefined/S235-E24
Tekla Commun - Repère d'assemblage: S18; Phase: 1; Profil: TOLE6*60; Nom: PLATINE; sets with these values: 2
Tekla Quantités - Poids: 0 kg; Volume: 0 m3; Surface supérieure totale: 0 m2; Surface par tonne: 0 m2; Surface nette: 0 m2; Hauteur: 60 mm; Largeur: 6 mm; sets with these values: 2
Pset_BeamCommon - LoadBearing: no
BaseQuantities - NetWeight: 0 kg
Name | Repère de pièce = Reference | Longueur (mm) = Length (mm) | OuterSurfaceArea (m2) | NetVolume (m3)
12 x PLATINE | 458 | 160 | 0.02184 | 0.0000576
12 x PLATINE | 457 | 260 | 0.03504 | 0.0000936

# IfcBeam: TOLE8*122, GOUSSET
In: Undefined
Description: TOLE8*122; Material: Undefined/S235-E24
Tekla Commun - Repère de pièce: 396; Repère d'assemblage: A21; Phase: 1; Profil: TOLE8*122; Nom: GOUSSET; sets with these values: 2
Tekla Quantités - Poids: 0 kg; Volume: 0 m3; Surface supérieure totale: 0 m2; Surface par tonne: 0 m2; Surface nette: 0.1 m2; Hauteur: 122.3 mm; Largeur: 8 mm; Longueur: 279.4 mm; sets with these values: 2
Pset_BeamCommon - LoadBearing: no; Reference: 396
BaseQuantities - Length: 279.372 mm; OuterSurfaceArea: 0.0590402 m2; NetVolume: 0.000213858 m3; NetWeight: 0 kg

# IfcBeam: TOLE8*126, GOUSSET
In: Undefined
Description: TOLE8*126; Material: Undefined/S235-E24
Tekla Commun - Repère de pièce: 390; Repère d'assemblage: A20; Phase: 1; Profil: TOLE8*126; Nom: GOUSSET; sets with these values: 2
Tekla Quantités - Poids: 0 kg; Volume: 0 m3; Surface supérieure totale: 0 m2; Surface par tonne: 0 m2; Surface nette: 0.1 m2; Hauteur: 126.5 mm; Largeur: 8 mm; Longueur: 276.1 mm; sets with these values: 2
Pset_BeamCommon - LoadBearing: no; Reference: 390
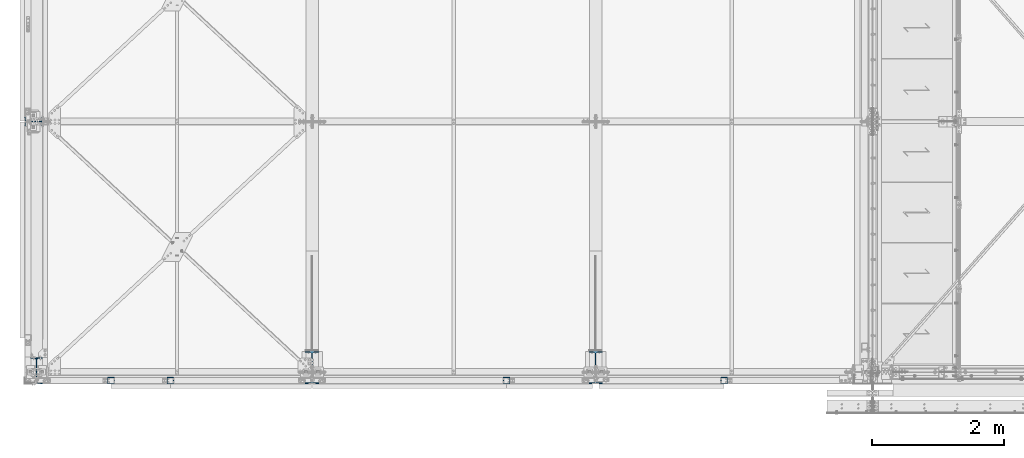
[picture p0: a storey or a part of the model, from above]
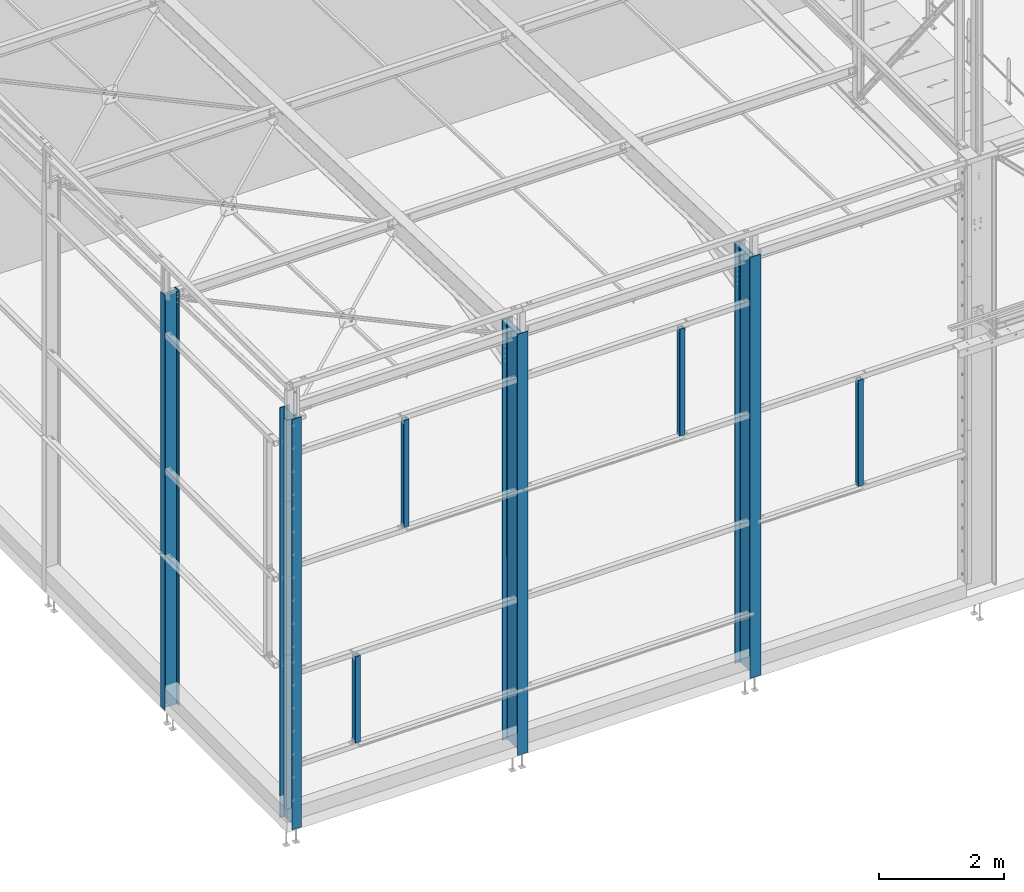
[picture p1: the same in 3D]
Properties of the parts of a building model (IFC2X3), part 3 of 4

# IfcBeam: TOLE8*126, GOUSSET
BaseQuantities - Length: 276.058 mm; OuterSurfaceArea: 0.0593226 m2; NetVolume: 0.000215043 m3; NetWeight: 0 kg

# IfcBeam: TOLE8*127 (4)
In: Undefined
Description: TOLE8*127; Material: Undefined/S235-E24
Tekla Commun - Repère de pièce: 393; Phase: 1; Profil: TOLE8*127; Nom: GOUSSET; sets with these values: 2
Tekla Quantités - Poids: 0 kg; Volume: 0 m3; Surface supérieure totale: 0 m2; Surface par tonne: 0 m2; Surface nette: 0.1 m2; Hauteur: 127.4 mm; Largeur: 8 mm; Longueur: 284.4 mm; sets with these values: 2
Pset_BeamCommon - LoadBearing: no; Reference: 393
BaseQuantities - Length: 284.43 mm; NetVolume: 0.000226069 m3; NetWeight: 0 kg
Name | Repère d'assemblage | OuterSurfaceArea (m2)
GOUSSET | M22 | 0.0622175
2 x GOUSSET | M23 | 0.0622174
GOUSSET | M19 | 0.0622174

# IfcBeam: TOLE8*133, GOUSSET
In: Undefined
Description: TOLE8*133; Material: Undefined/S235-E24
Tekla Commun - Repère de pièce: 395; Repère d'assemblage: M32; Phase: 1; Profil: TOLE8*133; Nom: GOUSSET; sets with these values: 2
Tekla Quantités - Poids: 0 kg; Volume: 0 m3; Surface supérieure totale: 0 m2; Surface par tonne: 0 m2; Surface nette: 0.1 m2; Hauteur: 133 mm; Largeur: 8 mm; Longueur: 282.6 mm; sets with these values: 2
Pset_BeamCommon - LoadBearing: no; Reference: 395
BaseQuantities - Length: 282.642 mm; OuterSurfaceArea: 0.0629307 m2; NetVolume: 0.000228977 m3; NetWeight: 0 kg

# IfcBeam: TOLE8*135 (8)
In: Undefined
Description: TOLE8*135; Material: Undefined/S235-E24
Tekla Commun - Phase: 1; Profil: TOLE8*135; Nom: GOUSSET; sets with these values: 2
Tekla Quantités - Poids: 0 kg; Volume: 0 m3; Surface supérieure totale: 0 m2; Surface par tonne: 0 m2; Surface nette: 0.1 m2; Largeur: 8 mm; sets with these values: 2
Pset_BeamCommon - LoadBearing: no
BaseQuantities - NetWeight: 0 kg
Name | Repère de pièce = Reference | Repère d'assemblage | Hauteur (mm) | Longueur (mm) | Length (mm) | OuterSurfaceArea (m2) | NetVolume (m3)
GOUSSET | 400 | M8 | 134.8 | 285.2 | 285.18 | 0.0635631 | 0.000231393
GOUSSET | 400 | M29 | 134.8 | 285.2 | 285.18 | 0.0635631 | 0.000231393
2 x GOUSSET | 400 | M27 | 134.8 | 285.2 | 285.18 | 0.0635631 | 0.000231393
GOUSSET | 397 | M4 | 134.5 | 282.5 | 282.487 | 0.0632325 | 0.000230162
2 x GOUSSET | 397 | M24 | 134.5 | 282.5 | 282.487 | 0.0632325 | 0.000230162
GOUSSET | 397 | M25 | 134.5 | 282.5 | 282.487 | 0.0632325 | 0.000230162

# IfcBeam: TOLE8*136 (2)
In: Undefined
Description: TOLE8*136; Material: Undefined/S235-E24
Tekla Commun - Repère de pièce: 394; Phase: 1; Profil: TOLE8*136; Nom: GOUSSET; sets with these values: 2
Tekla Quantités - Poids: 0 kg; Volume: 0 m3; Surface supérieure totale: 0 m2; Surface par tonne: 0 m2; Surface nette: 0.1 m2; Hauteur: 135.6 mm; Largeur: 8 mm; Longueur: 281.6 mm; sets with these values: 2
Pset_BeamCommon - LoadBearing: no; Reference: 394
BaseQuantities - NetWeight: 0 kg
Name | Repère d'assemblage | Length (mm) | OuterSurfaceArea (m2) | NetVolume (m3)
GOUSSET | M32 | 281.584 | 0.0632132 | 0.000230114
GOUSSET | M22 | 281.588 | 0.0632128 | 0.000230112

# IfcBeam: TOLE8*137 (2)
In: Undefined
Description: TOLE8*137; Material: Undefined/S235-E24
Tekla Commun - Repère de pièce: 392; Phase: 1; Profil: TOLE8*137; Nom: GOUSSET; sets with these values: 2
Tekla Quantités - Poids: 0 kg; Volume: 0 m3; Surface supérieure totale: 0 m2; Surface par tonne: 0 m2; Surface nette: 0.1 m2; Hauteur: 136.5 mm; Largeur: 8 mm; Longueur: 283.4 mm; sets with these values: 2
Pset_BeamCommon - LoadBearing: no; Reference: 392
BaseQuantities - NetVolume: 0.000230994 m3; NetWeight: 0 kg
Name | Repère d'assemblage | Length (mm) | OuterSurfaceArea (m2)
GOUSSET | M19 | 283.412 | 0.0634448
GOUSSET | M31 | 283.409 | 0.063445

# IfcBeam: TOLE8*138 (12)
In: Undefined
Description: TOLE8*138; Material: Undefined/S235-E24
Tekla Commun - Profil: TOLE8*138; sets with these values: 2
Tekla Quantités - Poids: 0 kg; Volume: 0 m3; Surface supérieure totale: 0 m2; Surface par tonne: 0 m2; Surface nette: 0.1 m2; Largeur: 8 mm; sets with these values: 2
Pset_BeamCommon - LoadBearing: no
BaseQuantities - NetWeight: 0 kg
Name | Finition | Repère de pièce = Reference | Repère d'assemblage | Phase | Nom | Hauteur (mm) | Longueur (mm) | Length (mm) | OuterSurfaceArea (m2) | NetVolume (m3)
7 x RAIDISSEUR CONSOLE | GALVA | 515 | C9 | 3 | RAIDISSEUR CONSOLE | 138 | 300 | 300 | 0.0677634 | 0.00024624
GOUSSET |  | 399 | M6 | 1 | GOUSSET | 137.9 | 280.9 | 280.893 | 0.0635542 | 0.000231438
GOUSSET |  | 399 | M28 | 1 | GOUSSET | 137.9 | 280.9 | 280.893 | 0.0635542 | 0.000231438
2 x GOUSSET |  | 399 | M26 | 1 | GOUSSET | 137.9 | 280.9 | 280.893 | 0.0635542 | 0.000231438
GOUSSET |  | 391 | M31 | 1 | GOUSSET | 138 | 280.4 | 280.41 | 0.0634576 | 0.00023106

# IfcBeam: TOLE8*140 (60)
In: Undefined
Description: TOLE8*140; Material: Undefined/S235-E24
Tekla Commun - Repère de pièce: 404; Repère d'assemblage: PN19; Phase: 1; Profil: TOLE8*140; Nom: RAIDISSEUR; sets with these values: 2
Tekla Quantités - Poids: 0 kg; Volume: 0 m3; Surface supérieure totale: 0 m2; Surface par tonne: 0 m2; Surface nette: 0.1 m2; Hauteur: 140 mm; Largeur: 8 mm; Longueur: 320 mm; sets with these values: 2
Pset_BeamCommon - LoadBearing: no; Reference: 404
BaseQuantities - Length: 320 mm; OuterSurfaceArea: 0.0591443 m2; NetVolume: 0.0002108 m3; NetWeight: 0 kg

# IfcBeam: TOLE8*213 (4)
In: Undefined
Description: TOLE8*213; Material: Undefined/S235-E24
Tekla Commun - Repère de pièce: 402; Phase: 1; Profil: TOLE8*213; Nom: GOUSSET; sets with these values: 2
Tekla Quantités - Poids: 0 kg; Volume: 0 m3; Surface supérieure totale: 0 m2; Surface par tonne: 0 m2; Surface nette: 0.1 m2; Hauteur: 213 mm; Largeur: 8 mm; Longueur: 253.2 mm; sets with these values: 2
Pset_BeamCommon - LoadBearing: no; Reference: 402
BaseQuantities - NetWeight: 0 kg
Name | Repère d'assemblage | Length (mm) | OuterSurfaceArea (m2) | NetVolume (m3)
GOUSSET | M7 | 253.171 | 0.0666447 | 0.000243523
GOUSSET | M8 | 253.165 | 0.0666437 | 0.00024352
GOUSSET | M34 | 253.162 | 0.0666432 | 0.000243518
GOUSSET | M29 | 253.162 | 0.0666432 | 0.000243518

# IfcBeam: TOLE8*235 (4)
In: Undefined
Description: TOLE8*235; Material: Undefined/S235-E24
Tekla Commun - Repère de pièce: 401; Phase: 1; Profil: TOLE8*235; Nom: GOUSSET; sets with these values: 2
Tekla Quantités - Poids: 0 kg; Volume: 0 m3; Surface supérieure totale: 0 m2; Surface par tonne: 0 m2; Surface nette: 0.1 m2; Hauteur: 234.7 mm; Largeur: 8 mm; Longueur: 233.2 mm; sets with these values: 2
Pset_BeamCommon - LoadBearing: no; Reference: 401
BaseQuantities - NetWeight: 0 kg
Name | Repère d'assemblage | Length (mm) | OuterSurfaceArea (m2) | NetVolume (m3)
GOUSSET | M33 | 233.204 | 0.0672126 | 0.000245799
GOUSSET | M6 | 233.207 | 0.0672131 | 0.000245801
GOUSSET | M5 | 233.212 | 0.0672141 | 0.000245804
GOUSSET | M28 | 233.204 | 0.0672126 | 0.000245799

# IfcBeam: TOLE8*250 (4)
In: Undefined
Description: TOLE8*250; Material: Undefined/S235-E24
Tekla Commun - Repère de pièce: 398; Phase: 1; Profil: TOLE8*250; Nom: GOUSSET; sets with these values: 2
Tekla Quantités - Poids: 0 kg; Volume: 0 m3; Surface supérieure totale: 0 m2; Surface par tonne: 0 m2; Surface nette: 0.1 m2; Hauteur: 249.8 mm; Largeur: 8 mm; Longueur: 215.1 mm; sets with these values: 2
Pset_BeamCommon - LoadBearing: no; Reference: 398
BaseQuantities - NetWeight: 0 kg
Name | Repère d'assemblage | Length (mm) | OuterSurfaceArea (m2) | NetVolume (m3)
GOUSSET | M3 | 215.106 | 0.0673195 | 0.000246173
GOUSSET | M4 | 215.1 | 0.0673186 | 0.000246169
GOUSSET | M25 | 215.097 | 0.0673181 | 0.000246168
GOUSSET | M30 | 215.097 | 0.0673175 | 0.000246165

# IfcBeam: TOLE8*417, JARRET
In: Undefined
Description: TOLE8*417; Material: Undefined/S235-E24
Tekla Commun - Repère de pièce: 403; Repère d'assemblage: T3; Phase: 1; Profil: TOLE8*417; Nom: JARRET; sets with these values: 2
Tekla Quantités - Poids: 0 kg; Volume: 0 m3; Surface supérieure totale: 0 m2; Surface par tonne: 0 m2; Surface nette: 0.7 m2; Hauteur: 416.5 mm; Largeur: 8 mm; Longueur: 1465.4 mm; sets with these values: 2
Pset_BeamCommon - LoadBearing: no; Reference: 403
BaseQuantities - Length: 1465.39 mm; OuterSurfaceArea: 0.681541 m2; NetVolume: 0.00262023 m3; NetWeight: 0 kg

# IfcBeam: TOLE8*60 (113)
In: Undefined
Description: TOLE8*60; Material: Undefined/S235-E24
Tekla Commun - Repère de pièce: P1; Repère d'assemblage: P1; Phase: 1; Profil: TOLE8*60; Nom: PLAQUETTE; sets with these values: 2
Tekla Quantités - Poids: 0 kg; Volume: 0 m3; Surface supérieure totale: 0 m2; Surface par tonne: 0 m2; Surface nette: 0 m2; Hauteur: 60 mm; Largeur: 8 mm; Longueur: 60 mm; sets with these values: 2
Pset_BeamCommon - LoadBearing: no; Reference: P1
BaseQuantities - Length: 60 mm; OuterSurfaceArea: 0.00713225 m2; NetVolume: 0.0000225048 m3; NetWeight: 0 kg

# IfcBeam: TUBE-21.3*2 (17)
In: Undefined
Description: TUBE-21.3*2; Material: Undefined/S235-E24
Tekla Commun - Finition: GALVA; Phase: 3; Profil: TUBE-21.3*2; Nom: LISSE; sets with these values: 2
Tekla Quantités - Poids: 0 kg; Volume: 0 m3; Surface supérieure totale: 0 m2; Surface par tonne: 0 m2; Hauteur: 21.3 mm; Largeur: 21.3 mm; sets with these values: 2
Pset_BeamCommon - LoadBearing: no
BaseQuantities - NetWeight: 0 kg
Name | Repère de pièce = Reference | Repère d'assemblage | Surface nette (m2) | Longueur (mm) | Length (mm) | OuterSurfaceArea (m2) | NetVolume (m3)
LISSE | 645 | GC0(?) | 0.2 | 3710 | 3709.99 | 0.245559 | 0.000429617
2 x LISSE | 643 | GC0(?) | 0 | 223.5 | 223.498 | 0.0146653 | 0.0000254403
LISSE | 628 | GC12 | 0.1 | 995 | 995.01 | 0.0659518 | 0.000115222
LISSE | 623 | GC12 | 0.1 | 1828.7 | 1828.67 | 0.120603 | 0.000210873
LISSE | 627 | GC8 | 0.2 | 2460 | 2460.01 | 0.162868 | 0.000284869
LISSE | 626 | GC10 | 0.3 | 5190 | 5190 | 0.343468 | 0.000601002
LISSE | 623 | GC8 | 0.1 | 1828.7 | 1828.67 | 0.120603 | 0.000210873
LISSE | 622 | GC4 | 0.2 | 3625 | 3624.99 | 0.239936 | 0.000419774
2 x LISSE | 619 | GC2 | 0 | 660 | 659.996 | 0.0437893 | 0.0000764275
LISSE | 621 | GC6 | 0.1 | 970 | 969.994 | 0.0642969 | 0.000112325
LISSE | 619 | GC3 | 0 | 660 | 660 | 0.0437895 | 0.000076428
LISSE | 619 | GC1 | 0 | 660 | 659.996 | 0.0437893 | 0.0000764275
LISSE | 619 | GC3 | 0 | 660 | 659.996 | 0.0437893 | 0.0000764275
LISSE | 621 | GC7 | 0.1 | 970 | 969.994 | 0.0642969 | 0.000112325
LISSE | 619 | GC3 | 0 | 660 | 659.996 | 0.0437893 | 0.0000764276

# IfcBeam: TUBE-26.9*2 (12)
In: Undefined
Description: TUBE-26.9*2; Material: Undefined/S235-E24
Tekla Commun - Phase: 1; Profil: TUBE-26.9*2; Nom: LISSE; sets with these values: 2
Tekla Quantités - Poids: 0 kg; Volume: 0 m3; Surface supérieure totale: 0 m2; Surface par tonne: 0 m2; Surface nette: 0.3 m2; Hauteur: 26.9 mm; Largeur: 26.9 mm; sets with these values: 2
Pset_BeamCommon - LoadBearing: no
BaseQuantities - NetWeight: 0 kg
Name | Repère de pièce = Reference | Repère d'assemblage | Longueur (mm) = Length (mm) | OuterSurfaceArea (m2) | NetVolume (m3)
LISSE | 487 | MC3 | 3845 | 0.321399 | 0.000574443
6 x LISSE | 486 | MC1 | 3690 | 0.308449 | 0.000551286
3 x LISSE | 487 | MC3 | 3845 | 0.321399 | 0.000574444
2 x LISSE | 487 | MC2 | 3845 | 0.321399 | 0.000574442

# IfcBeam: TUBE-C-100*100*4 (64)
In: Undefined
Description: TUBE-C-100*100*4; Material: Undefined/S235-E24
Tekla Commun - Phase: 1; Profil: TUBE-C-100*100*4; sets with these values: 2
Tekla Quantités - Poids: 0 kg; Volume: 0 m3; Surface par tonne: 0 m2; Hauteur: 100 mm; Largeur: 100 mm; sets with these values: 2
Pset_BeamCommon - LoadBearing: no
BaseQuantities - NetWeight: 0 kg
Name | Repère de pièce = Reference | Repère d'assemblage | Nom | Surface supérieure totale (m2) | Surface nette (m2) | Longueur (mm) = Length (mm) | OuterSurfaceArea (m2) | NetVolume (m3)
LISSE CHASSIS | 178 | L29 | LISSE CHASSIS | 0.3 | 1.2 | 3025 | 1.16765 | 0.0046464
MONTANT | M35 | M35 | MONTANT | 0 | 0.6 | 1580 | 0.60988 | 0.00242688
4 x LISSE ACROTERE | L16 | L16 | LISSE ACROTERE | 0.8 | 3.1 | 7665 | 2.95869 | 0.0117734
3 x LISSE ACROTERE | L44 | L44 | LISSE ACROTERE | 0.8 | 3.1 | 7755 | 2.99343 | 0.0119117
LISSE ACROTERE | L47 | L47 | LISSE ACROTERE | 0.8 | 3.1 | 7755 | 2.99343 | 0.0119117
LISSE ACROTERE | L46 | L46 | LISSE ACROTERE | 0.8 | 3.3 | 8185 | 3.15941 | 0.0125722
LISSE ACROTERE | L49 | L49 | LISSE ACROTERE | 0.8 | 3.1 | 7775 | 3.00115 | 0.0119424
LISSE CHASSIS | L60 | L60 | LISSE CHASSIS | 0.3 | 1.4 | 3495 | 1.34907 | 0.00536832
4 x LISSE CHASSIS | L19 | L19 | LISSE CHASSIS | 0.4 | 1.5 | 3650 | 1.4089 | 0.0056064
2 x LISSE CHASSIS | L61 | L61 | LISSE CHASSIS | 0.3 | 1.4 | 3405 | 1.31433 | 0.00523008
3 x LISSE ACROTERE | L17 | L17 | LISSE ACROTERE | 0.8 | 3.1 | 7665 | 2.95869 | 0.0117734
LISSE CHASSIS | L62 | L62 | LISSE CHASSIS | 0.5 | 2.1 | 5140 | 1.98404 | 0.00789504
LISSE CHASSIS | L30 | L30 | LISSE CHASSIS | 0.2 | 0.8 | 2005 | 0.773931 | 0.00307968
LISSE CHASSIS | 107 | L25 | LISSE CHASSIS | 0.5 | 2.1 | 5140 | 1.98404 | 0.00789504
LISSE CHASSIS | L59 | L59 | LISSE CHASSIS | 0.5 | 2 | 4990 | 1.92614 | 0.00766464
LISSE CHASSIS | 259 | L58 | LISSE CHASSIS | 0.5 | 2 | 4990 | 1.92614 | 0.00766464
LISSE CHASSIS | L57 | L57 | LISSE CHASSIS | 0.5 | 2 | 4990 | 1.92614 | 0.00766464
LISSE CHASSIS | 106 | L24 | LISSE CHASSIS | 0.5 | 2 | 4990 | 1.92614 | 0.00766464
LISSE CHASSIS | L56 | L56 | LISSE CHASSIS | 0.4 | 1.6 | 4090 | 1.57874 | 0.00628224
LISSE CHASSIS | 256 | L55 | LISSE CHASSIS | 0.4 | 1.6 | 4090 | 1.57874 | 0.00628224
LISSE CHASSIS | L54 | L54 | LISSE CHASSIS | 0.4 | 1.5 | 3790 | 1.46294 | 0.00582144
LISSE CHASSIS | 105 | L23 | LISSE CHASSIS | 0.4 | 1.5 | 3790 | 1.46294 | 0.00582144
LISSE CHASSIS | L22 | L22 | LISSE CHASSIS | 0.4 | 1.6 | 4090 | 1.57874 | 0.00628224
LISSE CHASSIS | 104 | L2 | LISSE CHASSIS | 0.4 | 1.6 | 4090 | 1.57874 | 0.00628224
LISSE CHASSIS | L53 | L53 | LISSE CHASSIS | 0.4 | 1.6 | 3980 | 1.53628 | 0.00611328
LISSE CHASSIS | 253 | L52 | LISSE CHASSIS | 0.4 | 1.6 | 3980 | 1.53628 | 0.00611328
LISSE CHASSIS | L51 | L51 | LISSE CHASSIS | 0.4 | 1.6 | 3980 | 1.53628 | 0.00611328
LISSE CHASSIS | 103 | L21 | LISSE CHASSIS | 0.4 | 1.6 | 3980 | 1.53628 | 0.00611328
LISSE CHASSIS | L50 | L50 | LISSE CHASSIS | 0.3 | 1.4 | 3495 | 1.34907 | 0.00536832
LISSE CHASSIS | 102 | L20 | LISSE CHASSIS | 0.3 | 1.4 | 3495 | 1.34907 | 0.00536832
2 x LISSE CHASSIS | 101 | L4 | LISSE CHASSIS | 0.4 | 1.5 | 3650 | 1.4089 | 0.0056064
MONTANT | M9 | M9 | MONTANT | 0 | 1 | 2540 | 0.98044 | 0.00390144
LISSE CHASSIS | 100 | L18 | LISSE CHASSIS | 0.3 | 1.4 | 3405 | 1.31433 | 0.00523008
MONTANT | M16 | M16 | MONTANT | 0 | 1.1 | 2850 | 1.1001 | 0.0043776
LISSE ACROTERE | L15 | L15 | LISSE ACROTERE | 0.7 | 3 | 7485 | 2.88921 | 0.011497
LISSE ACROTERE | L48 | L48 | LISSE ACROTERE | 0.8 | 3.1 | 7775 | 3.00115 | 0.0119424
LISSE ACROTERE | L14 | L14 | LISSE ACROTERE | 1.1 | 4.2 | 10525 | 4.06265 | 0.0161664
3 x LISSE ACROTERE | L12 | L12 | LISSE ACROTERE | 0.4 | 1.5 | 3660 | 1.41276 | 0.00562176
LISSE ACROTERE | L45 | L45 | LISSE ACROTERE | 0.4 | 1.5 | 3660 | 1.41276 | 0.00562176
4 x LISSE ACROTERE | L64 | L64 | LISSE ACROTERE | 0.4 | 1.5 | 3660 | 1.41276 | 0.00562176
LISSE ACROTERE | L13 | L13 | LISSE ACROTERE | 0.4 | 1.5 | 3660 | 1.41276 | 0.00562176
LISSE ACROTERE | L11 | L11 | LISSE ACROTERE | 0.4 | 1.4 | 3610 | 1.39346 | 0.00554496
LISSE ACROTERE | L10 | L10 | LISSE ACROTERE | 0.4 | 1.5 | 3660 | 1.41276 | 0.00562176
LISSE ACROTERE | L9 | L9 | LISSE ACROTERE | 0.4 | 1.4 | 3620 | 1.39732 | 0.00556032
LISSE ACROTERE | L8 | L8 | LISSE ACROTERE | 0.7 | 3 | 7475 | 2.88535 | 0.0114816
LISSE ACROTERE | L7 | L7 | LISSE ACROTERE | 0.4 | 1.7 | 4245 | 1.63857 | 0.00652032
LISSE ACROTERE | L6 | L6 | LISSE ACROTERE | 0.8 | 3.1 | 7755 | 2.99343 | 0.0119117

# IfcBeam: TUBE-C-100*100*5 (7)
In: Undefined
Description: TUBE-C-100*100*5; Material: Undefined/S235-E24
Tekla Commun - Finition: GALVA; Repère de pièce: 568; Repère d'assemblage: C9; Phase: 3; Profil: TUBE-C-100*100*5; Nom: CONSOLE; sets with these values: 2
Tekla Quantités - Poids: 0 kg; Volume: 0 m3; Surface supérieure totale: 0.2 m2; Surface par tonne: 0 m2; Surface nette: 0.6 m2; Hauteur: 100 mm; Largeur: 100 mm; Longueur: 1518 mm; sets with these values: 2
Pset_BeamCommon - LoadBearing: no; Reference: 568
BaseQuantities - Length: 1517.99 mm; OuterSurfaceArea: 0.581392 m2; NetVolume: 0.00287315 m3; NetWeight: 0 kg

# IfcBeam: TUBE-C-120*120*4, BUTON
In: Undefined
Description: TUBE-C-120*120*4; Material: Undefined/S235-E24
Tekla Commun - Repère de pièce: 81; Repère d'assemblage: B5; Phase: 1; Profil: TUBE-C-120*120*4; Nom: BUTON; sets with these values: 2
Tekla Quantités - Poids: 0 kg; Volume: 0 m3; Surface supérieure totale: 0.5 m2; Surface par tonne: 0 m2; Surface nette: 2.1 m2; Hauteur: 120 mm; Largeur: 120 mm; Longueur: 4456.2 mm; sets with these values: 2
Pset_BeamCommon - LoadBearing: no; Reference: 81
BaseQuantities - Length: 4456.15 mm; OuterSurfaceArea: 2.07657 m2; NetVolume: 0.00795302 m3; NetWeight: 0 kg

# IfcBeam: TUBE-C-40*40*4 (8)
In: Undefined
Description: TUBE-C-40*40*4; Material: Undefined/S235-E24
Tekla Commun - Repère de pièce: B13; Repère d'assemblage: B13; Phase: 1; Profil: TUBE-C-40*40*4; Nom: BUTON; sets with these values: 2
Tekla Quantités - Poids: 0 kg; Volume: 0 m3; Surface supérieure totale: 0 m2; Surface par tonne: 0 m2; Surface nette: 0.6 m2; Hauteur: 40 mm; Largeur: 40 mm; Longueur: 3700 mm; sets with these values: 2
Pset_BeamCommon - LoadBearing: no; Reference: B13
BaseQuantities - Length: 3700 mm; OuterSurfaceArea: 0.5402 m2; NetVolume: 0.0021312 m3; NetWeight: 0 kg

# IfcBeam: TUBE-C-60*60*3 (12)
In: Undefined
Description: TUBE-C-60*60*3; Material: Undefined/S235-E24
Tekla Commun - Repère de pièce: 205; Repère d'assemblage: S18; Phase: 1; Profil: TUBE-C-60*60*3; Nom: SOLIVE; sets with these values: 2
Tekla Quantités - Poids: 0 kg; Volume: 0 m3; Surface supérieure totale: 0.1 m2; Surface par tonne: 0 m2; Surface nette: 0.3 m2; Hauteur: 60 mm; Largeur: 60 mm; Longueur: 1182 mm; sets with these values: 2
Pset_BeamCommon - LoadBearing: no; Reference: 205
BaseQuantities - NetWeight: 0 kg
Name | Length (mm) | OuterSurfaceArea (m2) | NetVolume (m3)
11 x SOLIVE | 1182 | 0.270678 | 0.000808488
SOLIVE | 1181.99 | 0.270676 | 0.000808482

# IfcBeam: TUBE-C-80*80*4 (3)
In: Undefined
Description: TUBE-C-80*80*4; Material: Undefined/S235-E24
Tekla Commun - Phase: 1; Profil: TUBE-C-80*80*4; sets with these values: 2
Tekla Quantités - Poids: 0 kg; Volume: 0 m3; Surface par tonne: 0 m2; Hauteur: 80 mm; Largeur: 80 mm; sets with these values: 2
Pset_BeamCommon - LoadBearing: no
BaseQuantities - NetWeight: 0 kg
Name | Repère de pièce = Repère d'assemblage = Reference | Nom | Surface supérieure totale (m2) | Surface nette (m2) | Longueur (mm) | Length (mm) | OuterSurfaceArea (m2) | NetVolume (m3)
LISSE ACROTERE | L1 | LISSE ACROTERE | 0.3 | 1.3 | 4110 | 4110 | 1.25766 | 0.00499776
RAMASSE PANNE | RP2 | RAMASSE PANNE | 0 | 2.5 | 7691.3 | 7691.31 | 2.35354 | 0.00934957
RAMASSE PANNE | RP1 | RAMASSE PANNE | 0 | 2.5 | 7781.4 | 7781.35 | 2.38109 | 0.00945907

# IfcBeam: UPF-100*50*4 (32)
In: Undefined
Description: UPF-100*50*4; Material: Undefined/S235-E24
Tekla Commun - Profil: UPF-100*50*4; sets with these values: 2
Tekla Quantités - Poids: 0 kg; Volume: 0 m3; Surface par tonne: 0 m2; Hauteur: 100 mm; Largeur: 50 mm; sets with these values: 2
Pset_BeamCommon - LoadBearing: no
BaseQuantities - NetWeight: 0 kg
Name | Repère de pièce = Repère d'assemblage = Reference | Phase | Nom | Surface supérieure totale (m2) | Surface nette (m2) | Longueur (mm) | Length (mm) | OuterSurfaceArea (m2) | NetVolume (m3)
SUPPORT | S44 | 1 | SUPPORT | 0.1 | 3.2 | 8055 | 8055 | 3.1591 | 0.00618624
SUPPORT | S43 | 1 | SUPPORT | 0.1 | 3.7 | 9515 | 9515 | 3.73142 | 0.00730752
2 x LISSE CONTREBARDAGE | L71 | 1 | LISSE CONTREBARDAGE | 0 | 1.6 | 3959.8 | 3959.78 | 1.55334 | 0.00304024
3 x LISSE CONTREBARDAGE | L67 | 1 | LISSE CONTREBARDAGE | 0 | 1.5 | 3791.9 | 3791.88 | 1.48795 | 0.00291216
3 x LISSE CONTREBARDAGE | L66 | 1 | LISSE CONTREBARDAGE | 0 | 1.5 | 3864.8 | 3864.84 | 1.51655 | 0.00296819
6 x LISSE CONTREBARDAGE | L65 | 1 | LISSE CONTREBARDAGE | 0 | 1.4 | 3673.4 | 3673.38 | 1.44089 | 0.00281995
3 x LISSE CONTREBARDAGE | L26 | 1 | LISSE CONTREBARDAGE | 0 | 1.4 | 3534.8 | 3534.82 | 1.38657 | 0.00271353
2 x LISSE CONTREBARDAGE | L70 | 1 | LISSE CONTREBARDAGE | 0 | 1.4 | 3693.4 | 3693.39 | 1.44873 | 0.00283532
LISSE CONTREBARDAGE | L69 | 1 | LISSE CONTREBARDAGE | 0 | 1.4 | 3544.8 | 3544.82 | 1.39049 | 0.00272122
BAIONNETTE | B16 | 1 | BAIONNETTE | 0 | 0.3 | 755 | 754.999 | 0.275055 | 0.000534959
BAIONNETTE | B11 | 1 | BAIONNETTE | 0 | 0.2 | 670 | 669.999 | 0.241735 | 0.000469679
BAIONNETTE | B9 | 1 | BAIONNETTE | 0 | 0.3 | 790 | 789.999 | 0.288775 | 0.000561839
BAIONNETTE | B7 | 1 | BAIONNETTE | 0 | 0.3 | 910 | 909.999 | 0.335815 | 0.000653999
2 x LISSE | L31 | 2 | LISSE | 0.3 | 1.2 | 3000 | 3000 | 1.17754 | 0.002304 | Tekla Commun - Finition: GALVA
LISSE CONTREBARDAGE | L68 | 1 | LISSE CONTREBARDAGE | 0 | 1.5 | 3898.7 | 3898.68 | 1.52916 | 0.00299289
LISSE CONTREBARDAGE | L26 | 1 | LISSE CONTREBARDAGE | 0 | 1.4 | 3534.8 | 3534.81 | 1.38657 | 0.00271353
LISSE CONTREBARDAGE | L28 | 1 | LISSE CONTREBARDAGE | 0 | 1.6 | 3959.8 | 3959.78 | 1.55334 | 0.00304024
LISSE CONTREBARDAGE | L27 | 1 | LISSE CONTREBARDAGE | 0 | 1.5 | 3898.5 | 3898.5 | 1.52913 | 0.00299284

# IfcBeam: UPF-150*70*5 (6)
In: Undefined
Description: UPF-150*70*5; Material: Undefined/S235-E24
Tekla Commun - Phase: 1; Profil: UPF-150*70*5; Nom: LONGERON; sets with these values: 2
Tekla Quantités - Poids: 0 kg; Volume: 0 m3; Surface supérieure totale: 0.5 m2; Surface par tonne: 0 m2; Hauteur: 150 mm; Largeur: 70 mm; sets with these values: 2
Pset_BeamCommon - LoadBearing: no
BaseQuantities - NetWeight: 0 kg
Name | Repère de pièce = Repère d'assemblage = Reference | Surface nette (m2) | Longueur (mm) = Length (mm) | OuterSurfaceArea (m2) | NetVolume (m3)
3 x LONGERON | L72 | 4.4 | 7755 | 4.42315 | 0.010857
LONGERON | L36 | 4.1 | 7265 | 4.14385 | 0.010171
LONGERON | L35 | 4.3 | 7490 | 4.2721 | 0.010486
LONGERON | L34 | 4.3 | 7575 | 4.32055 | 0.010605

# IfcBeam: UPF-200*80*4 (14)
In: Undefined
Description: UPF-200*80*4; Material: Undefined/S235-E24
Tekla Commun - Finition: GALVA; Repère de pièce: 578; Phase: 3; Profil: UPF-200*80*4; Nom: COLLERETTE; sets with these values: 2
Tekla Quantités - Poids: 0 kg; Volume: 0 m3; Surface supérieure totale: 0 m2; Surface par tonne: 0 m2; Surface nette: 0.1 m2; Hauteur: 200 mm; Largeur: 80 mm; Longueur: 192 mm; sets with these values: 2
Pset_BeamCommon - LoadBearing: no; Reference: 578
BaseQuantities - Length: 192 mm; OuterSurfaceArea: 0.120734 m2; NetVolume: 0.000229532 m3; NetWeight: 0 kg
Name | Repère d'assemblage
6 x COLLERETTE | P4
8 x COLLERETTE | P3

# IfcBeam: UPN200 (2)
In: Undefined
Description: UPN200; Material: Undefined/S275-E28
Tekla Commun - Phase: 1; Profil: UPN200; Nom: SUPPORT; sets with these values: 2
Tekla Quantités - Poids: 0 kg; Volume: 0 m3; Surface par tonne: 0 m2; Hauteur: 200 mm; Largeur: 75 mm; sets with these values: 2
Pset_BeamCommon - LoadBearing: no
BaseQuantities - NetWeight: 0 kg
Name | Repère de pièce = Repère d'assemblage = Reference | Surface supérieure totale (m2) | Surface nette (m2) | Longueur (mm) = Length (mm) | OuterSurfaceArea (m2) | NetVolume (m3)
SUPPORT | S47 | 1.6 | 5.4 | 8055 | 5.3163 | 0.0256494
SUPPORT | S48 | 1.9 | 6.4 | 9515 | 6.2799 | 0.0302984

# IfcBeam: UPN260 (20)
In: Undefined
Description: UPN260; Material: Undefined/S275-E28
Tekla Commun - Finition: GALVA; Phase: 3; Profil: UPN260; Nom: LIMON; sets with these values: 2
Tekla Quantités - Poids: 0 kg; Volume: 0 m3; Surface par tonne: 0 m2; Hauteur: 260 mm; Largeur: 90 mm; sets with these values: 2
Pset_BeamCommon - LoadBearing: no
BaseQuantities - NetWeight: 0 kg
Name | Repère de pièce = Reference | Repère d'assemblage | Surface supérieure totale (m2) | Surface nette (m2) | Longueur (mm) | Length (mm) | OuterSurfaceArea (m2) | NetVolume (m3)
3 x LIMON | 606 | L90 | 0.1 | 0.7 | 873.9 | 873.889 | 0.727075 | 0.00382783
LIMON | 605 | L89 | 0.1 | 0.7 | 873.9 | 873.889 | 0.727076 | 0.00382783
LIMON | 605 | L89 | 0.1 | 0.7 | 873.9 | 873.889 | 0.727075 | 0.00382783
LIMON | 604 | L33(?) | 0.1 | 1 | 1246 | 1246.01 | 1.03668 | 0.00572907
LIMON | 603 | L63 | 0.1 | 1 | 1246 | 1246.01 | 1.03668 | 0.00572907
LIMON | 534 | L63 | 0.2 | 1.6 | 1911.9 | 1911.89 | 1.59069 | 0.00868451
LIMON | 605 | L89 | 0.1 | 0.7 | 873.9 | 873.893 | 0.727079 | 0.00382784
LIMON | L91 | L91 | 0.1 | 0.8 | 990 | 989.993 | 0.823674 | 0.00472821
LIMON | 533 | L33(?) | 0.2 | 1.6 | 1911.9 | 1911.89 | 1.59069 | 0.00868451
2 x LIMON | L92 | L92(?) | 0.4 | 3.8 | 4500 | 4500 | 3.744 | 0.021492
LIMON | 534 | L75(?) | 0.2 | 1.6 | 1911.9 | 1911.89 | 1.59069 | 0.00868451
LIMON | 533 | L5(?) | 0.2 | 1.6 | 1911.9 | 1911.89 | 1.59069 | 0.00868451
LIMON | L88 | L88 | 0.1 | 0.8 | 990 | 989.993 | 0.823674 | 0.00472821
LIMON | L87 | L87(?) | 0.3 | 2.5 | 2890 | 2890.01 | 2.40449 | 0.0138027
LIMON | 554 | L5(?) | 0.3 | 2.4 | 2851 | 2851.01 | 2.37204 | 0.0133945
LIMON | L93 | L93 | 0.3 | 2.5 | 2890 | 2890.01 | 2.40449 | 0.0138027
LIMON | 553 | L75(?) | 0.3 | 2.4 | 2851 | 2851.01 | 2.37204 | 0.0133945

# IfcColumn: HEA100 (6)
In: Undefined
Description: HEA100; Material: Undefined/S275-E28
Tekla Commun - Profil: HEA100; Nom: BAIONNETTE; sets with these values: 2
Tekla Quantités - Poids: 0 kg; Volume: 0 m3; Surface supérieure totale: 0 m2; Surface par tonne: 0 m2; Hauteur: 96 mm; Largeur: 100 mm; sets with these values: 2
Pset_ColumnCommon - LoadBearing: no
BaseQuantities - NetWeight: 0 kg
Name | Repère de pièce = Reference | Repère d'assemblage | Phase | Surface nette (m2) | Longueur (mm) | Length (mm) | OuterSurfaceArea (m2) | NetVolume (m3)
BAIONNETTE | 211 | PT5 | 4 | 0.2 | 392.4 | 392.36 | 0.220114 | 0.000781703
BAIONNETTE | B3 | B3 | 1 | 0.8 | 1345 | 1345 | 0.754545 | 0.00269
BAIONNETTE | B2 | B2 | 1 | 0.8 | 1345 | 1345 | 0.754545 | 0.00269
BAIONNETTE | B1 | B1 | 1 | 0.8 | 1345 | 1345 | 0.754544 | 0.00268999
BAIONNETTE | 38 | PT4 | 1 | 0.2 | 392.4 | 392.36 | 0.220114 | 0.000781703
BAIONNETTE | 211 | PT6(?) | 1 | 0.2 | 392.4 | 392.36 | 0.220114 | 0.000781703

# IfcColumn: HEA140 (16)
In: Undefined
Description: HEA140; Material: Undefined/S275-E28
Tekla Commun - Phase: 1; Profil: HEA140; Nom: MONTANT; sets with these values: 2
Tekla Quantités - Poids: 0 kg; Volume: 0 m3; Surface supérieure totale: 0 m2; Surface par tonne: 0 m2; Hauteur: 133 mm; Largeur: 140 mm; sets with these values: 2
Pset_ColumnCommon - LoadBearing: no
BaseQuantities - NetWeight: 0 kg
Name | Repère de pièce = Reference | Repère d'assemblage | Surface nette (m2) | Longueur (mm) | Length (mm) | OuterSurfaceArea (m2) | NetVolume (m3)
MONTANT | 238 | M34 | 3 | 3719.7 | 3719.7 | 2.95344 | 0.0111274
MONTANT | 237 | M33 | 3.7 | 4540.1 | 4540.15 | 3.60488 | 0.0135982
MONTANT | 225 | M30 | 4.3 | 5342.5 | 5342.55 | 4.24198 | 0.0160188
MONTANT | 224 | M29 | 3 | 3719.7 | 3719.7 | 2.95344 | 0.0111274
MONTANT | 223 | M28 | 3.7 | 4540.1 | 4540.15 | 3.60488 | 0.0135982
MONTANT | 206 | M25 | 4.3 | 5342.5 | 5342.55 | 4.24198 | 0.0160188
MONTANT | 217 | M27 | 3 | 3719.7 | 3719.7 | 2.95344 | 0.0111274
MONTANT | 212 | M26 | 3.7 | 4540.1 | 4540.15 | 3.60488 | 0.0135982
MONTANT | 204 | M24 | 4.3 | 5342.5 | 5342.55 | 4.24198 | 0.0160188
MONTANT | 49 | M36 | 0.4 | 492.2 | 492.193 | 0.390801 | 0.0014788
MONTANT | 48 | M8 | 3 | 3719.7 | 3719.7 | 2.95344 | 0.0111274
MONTANT | 47 | M7 | 2 | 2519.7 | 2519.7 | 2.00064 | 0.00750577
MONTANT | 46 | M6 | 3.7 | 4540.1 | 4540.15 | 3.60488 | 0.0135982
MONTANT | 45 | M5 | 2.6 | 3240.1 | 3240.15 | 2.57268 | 0.00967476
MONTANT | 44 | M4 | 4.3 | 5342.5 | 5342.55 | 4.24198 | 0.0160188
MONTANT | 43 | M3 | 3.3 | 4042.5 | 4042.55 | 3.20978 | 0.0120954

# IfcColumn: HEA200 (7)
In: Undefined
Description: HEA200; Material: Undefined/S275-E28
Tekla Commun - Phase: 1; Profil: HEA200; Nom: MONTANT; sets with these values: 2
Tekla Quantités - Poids: 0 kg; Volume: 0 m3; Surface supérieure totale: 0 m2; Surface par tonne: 0 m2; Hauteur: 190 mm; Largeur: 200 mm; sets with these values: 2
Pset_ColumnCommon - LoadBearing: no
BaseQuantities - NetWeight: 0 kg
Name | Repère de pièce = Reference | Repère d'assemblage | Surface nette (m2) | Longueur (mm) | Length (mm) | OuterSurfaceArea (m2) | NetVolume (m3)
MONTANT | 233 | M20 | 0.5 | 410 | 409.994 | 0.465754 | 0.00209302
MONTANT | 581 | M32 | 3.7 | 3150 | 3149.99 | 3.57839 | 0.0160807
MONTANT | 158 | M23 | 3.7 | 3150 | 3150 | 3.5784 | 0.0160807
MONTANT | 233 | M20 | 0.5 | 410 | 409.995 | 0.465755 | 0.00209303
MONTANT | 157 | M22 | 3.7 | 3150 | 3149.99 | 3.57839 | 0.0160807
MONTANT | 156 | M19 | 3.7 | 3150 | 3149.99 | 3.57839 | 0.0160807
MONTANT | 232 | M31 | 3.7 | 3150 | 3149.99 | 3.57839 | 0.0160807

# IfcColumn: IPE160 (2)
In: Undefined
Description: IPE160; Material: Undefined/S275-E28
Tekla Commun - Finition: GALVA; Phase: 2; Profil: IPE160; Nom: POTEAU; sets with these values: 2
Tekla Quantités - Poids: 0 kg; Volume: 0 m3; Surface supérieure totale: 0 m2; Surface par tonne: 0 m2; Surface nette: 1.8 m2; Hauteur: 160 mm; Largeur: 82 mm; Longueur: 2862 mm; sets with these values: 2
Pset_ColumnCommon - LoadBearing: no
BaseQuantities - Length: 2861.96 mm; OuterSurfaceArea: 1.783 m2; NetVolume: 0.00554292 m3; NetWeight: 0 kg
Name | Repère de pièce = Reference | Repère d'assemblage
POTEAU | 131 | PT13
POTEAU | 194 | PT11

# IfcColumn: IPE200 (9)
In: Undefined
Description: IPE200; Material: Undefined/S275-E28
Tekla Commun - Phase: 1; Profil: IPE200; Nom: TRAVERSE SHED; sets with these values: 2
Tekla Quantités - Poids: 0 kg; Volume: 0 m3; Surface supérieure totale: 0 m2; Surface par tonne: 0 m2; Hauteur: 200 mm; Largeur: 100 mm; sets with these values: 2
Pset_ColumnCommon - LoadBearing: no
BaseQuantities - NetWeight: 0 kg
Name | Repère de pièce = Reference | Repère d'assemblage | Surface nette (m2) | Longueur (mm) | Length (mm) | OuterSurfaceArea (m2) | NetVolume (m3)
TRAVERSE SHED | 71 | TS10 | 0.3 | 491.6 | 491.565 | 0.377522 | 0.00116547
TRAVERSE SHED | 70 | TS9 | 0.7 | 969.2 | 969.246 | 0.744381 | 0.00246705
TRAVERSE SHED | 69 | TS8 | 0.6 | 849.8 | 849.825 | 0.652666 | 0.00214166
TRAVERSE SHED | 68 | TS7 | 0.5 | 730.4 | 730.405 | 0.560951 | 0.00181626
TRAVERSE SHED | 67 | TS6 | 0.4 | 611 | 610.985 | 0.469236 | 0.00149087
TRAVERSE SHED | 64 | TS4 | 0.7 | 969.2 | 969.246 | 0.744381 | 0.00247103
TRAVERSE SHED | 63 | TS3 | 0.6 | 849.8 | 849.825 | 0.652666 | 0.00214563
TRAVERSE SHED | 62 | TS2 | 0.5 | 730.4 | 730.405 | 0.560951 | 0.00182023
TRAVERSE SHED | 61 | TS1 | 0.4 | 611 | 610.985 | 0.469236 | 0.00149484

# IfcColumn: IPE240 (4)
In: Undefined
Description: IPE240; Material: Undefined/S275-E28
Tekla Commun - Phase: 1; Profil: IPE240; Nom: TRAVERSE SHED; sets with these values: 2
Tekla Quantités - Poids: 0 kg; Volume: 0 m3; Surface supérieure totale: 0 m2; Surface par tonne: 0 m2; Hauteur: 240 mm; Largeur: 120 mm; sets with these values: 2
Pset_ColumnCommon - LoadBearing: no
BaseQuantities - NetWeight: 0 kg
Name | Repère de pièce = Reference | Repère d'assemblage | Surface nette (m2) | Longueur (mm) | Length (mm) | OuterSurfaceArea (m2) | NetVolume (m3)
TRAVERSE SHED | 76 | TS14 | 0.5 | 611.3 | 611.299 | 0.563618 | 0.00199593
TRAVERSE SHED | 75 | TS13 | 0.9 | 969.6 | 969.56 | 0.893934 | 0.00332812
TRAVERSE SHED | 74 | TS12 | 0.7 | 850.1 | 850.14 | 0.783829 | 0.00288406
TRAVERSE SHED | 73 | TS11 | 0.6 | 730.7 | 730.719 | 0.673723 | 0.00243999

# IfcColumn: IPE270 (3)
In: Undefined
Description: IPE270; Material: Undefined/S275-E28
Tekla Commun - Phase: 1; Profil: IPE270; Nom: POTEAU; sets with these values: 2
Tekla Quantités - Poids: 0 kg; Volume: 0 m3; Surface supérieure totale: 0 m2; Surface par tonne: 0 m2; Hauteur: 270 mm; Largeur: 135 mm; sets with these values: 2
Pset_ColumnCommon - LoadBearing: no
BaseQuantities - NetWeight: 0 kg
Name | Repère de pièce = Repère d'assemblage = Reference | Surface nette (m2) | Longueur (mm) = Length (mm) | OuterSurfaceArea (m2) | NetVolume (m3)
POTEAU | PT9 | 8.7 | 8105 | 8.4373 | 0.035673
POTEAU | PT8 | 8.5 | 7985 | 8.31239 | 0.0351449
POTEAU | PT7 | 8.4 | 7865 | 8.18747 | 0.0346167

# IfcColumn: IPE400 (2)
In: Undefined
Description: IPE400; Material: Undefined/S275-E28
Tekla Commun - Phase: 1; Profil: IPE400; Nom: POTEAU; sets with these values: 2
Tekla Quantités - Poids: 0 kg; Volume: 0.1 m3; Surface supérieure totale: 0 m2; Surface par tonne: 0 m2; Hauteur: 400 mm; Largeur: 180 mm; sets with these values: 2
Pset_ColumnCommon - LoadBearing: no
BaseQuantities - NetWeight: 0 kg
Name | Repère de pièce = Reference | Repère d'assemblage | Surface nette (m2) | Longueur (mm) = Length (mm) | OuterSurfaceArea (m2) | NetVolume (m3)
POTEAU | 2 | PT2 | 11.4 | 7550 | 11.0759 | 0.0609119
POTEAU | PT1 | PT1 | 12.1 | 8020 | 11.7653 | 0.0647037

# IfcColumn: IPE500 (4)
In: Undefined
Description: IPE500; Material: Undefined/S275-E28
Tekla Commun - Profil: IPE500; Nom: POTEAU; sets with these values: 2
Tekla Quantités - Poids: 0 kg; Volume: 0.1 m3; Surface supérieure totale: 0 m2; Surface par tonne: 0 m2; Hauteur: 500 mm; Largeur: 200 mm; sets with these values: 2
Pset_ColumnCommon - LoadBearing: no
BaseQuantities - NetWeight: 0 kg
Name | Repère de pièce = Reference | Repère d'assemblage | Phase | Surface nette (m2) | Longueur (mm) | Length (mm) | OuterSurfaceArea (m2) | NetVolume (m3)
POTEAU | 15 | PT5 | 4 | 14.7 | 8230.7 | 8230.65 | 14.3543 | 0.0918782
POTEAU | 4 | PT4 | 1 | 14.7 | 8230.7 | 8230.65 | 14.3543 | 0.0918782
POTEAU | 3 | PT3 | 1 | 15.4 | 8625 | 8625 | 15.042 | 0.0963723
POTEAU | 5 | PT6(?) | 1 | 14.7 | 8230.7 | 8230.65 | 14.3543 | 0.0918782

# IfcColumn: IPE600 (2)
In: Undefined
Description: IPE600; Material: Undefined/S275-E28
Tekla Commun - Phase: 1; Profil: IPE600; Nom: POTEAU; sets with these values: 2
Tekla Quantités - Poids: 0 kg; Volume: 0.1 m3; Surface supérieure totale: 0 m2; Surface par tonne: 0 m2; Surface nette: 18 m2; Hauteur: 600 mm; Largeur: 220 mm; Longueur: 8725 mm; sets with these values: 2
Pset_ColumnCommon - LoadBearing: no
BaseQuantities - Length: 8725 mm; OuterSurfaceArea: 17.5809 m2; NetVolume: 0.131782 m3; NetWeight: 0 kg
Name | Repère de pièce = Reference | Repère d'assemblage
POTEAU | 14 | PT10
POTEAU | 26 | PT12

# IfcColumn: L100*10 (12)
In: Undefined
Description: L100*10; Material: Undefined/S235-E24
Tekla Commun - Phase: 1; Profil: L100*10; Nom: ATTACHE; sets with these values: 2
Tekla Quantités - Poids: 0 kg; Volume: 0 m3; Surface supérieure totale: 0 m2; Surface par tonne: 0 m2; Surface nette: 0.1 m2; Hauteur: 100 mm; Largeur: 100 mm; sets with these values: 2
Pset_ColumnCommon - LoadBearing: no
BaseQuantities - NetWeight: 0 kg
Name | Repère de pièce = Repère d'assemblage = Reference | Longueur (mm) = Length (mm) | OuterSurfaceArea (m2) | NetVolume (m3)
ATTACHE | A23 | 120 | 0.0468 | 0.000228
5 x ATTACHE | A22 | 130 | 0.0507 | 0.000247
2 x ATTACHE | A10 | 280 | 0.1092 | 0.000532
3 x ATTACHE | A11 | 240 | 0.0936 | 0.000456
ATTACHE | A9 | 180 | 0.0702 | 0.000342

# IfcColumn: L200*100*10 (2)
In: Undefined
Description: L200*100*10; Material: Undefined/S235-E24
Tekla Commun - Phase: 1; Profil: L200*100*10; Nom: ATTACHE; sets with these values: 2
Tekla Quantités - Poids: 0 kg; Volume: 0 m3; Surface supérieure totale: 0 m2; Surface par tonne: 0 m2; Surface nette: 0.1 m2; Largeur: 100 mm; sets with these values: 2
Pset_ColumnCommon - LoadBearing: no
BaseQuantities - NetWeight: 0 kg
Name | Repère de pièce = Repère d'assemblage = Reference | Hauteur (mm) | Longueur (mm) = Length (mm) | OuterSurfaceArea (m2) | NetVolume (m3)
ATTACHE | A52 | 150 | 100 | 0.0587 | 0.00024
ATTACHE | A51 | 200 | 80 | 0.04696 | 0.000232

# IfcColumn: L40*4 (3)
In: Undefined
Description: L40*4; Material: Undefined/S235-E24
Tekla Commun - Repère de pièce: A14; Repère d'assemblage: A14; Phase: 1; Profil: L40*4; Nom: ATTACHE; sets with these values: 2
Tekla Quantités - Poids: 0 kg; Volume: 0 m3; Surface supérieure totale: 0 m2; Surface par tonne: 0 m2; Surface nette: 0 m2; Hauteur: 40 mm; Largeur: 40 mm; Longueur: 120 mm; sets with these values: 2
BaseQuantities - Length: 120 mm; OuterSurfaceArea: 0.0186 m2; NetVolume: 0.00003648 m3; NetWeight: 0 kg
Pset_ColumnCommon - LoadBearing: no; Reference: A14

# IfcColumn: L60*6 (2)
In: Undefined
Description: L60*6; Material: Undefined/S235-E24
Tekla Commun - Finition: GALVA; Repère de pièce: A45; Repère d'assemblage: A45; Phase: 3; Profil: L60*6; Nom: ATTACHE; sets with these values: 2
Tekla Quantités - Poids: 0 kg; Volume: 0 m3; Surface supérieure totale: 0 m2; Surface par tonne: 0 m2; Surface nette: 0 m2; Hauteur: 60 mm; Largeur: 60 mm; Longueur: 180 mm; sets with these values: 2
Pset_ColumnCommon - LoadBearing: no; Reference: A45
BaseQuantities - Length: 180 mm; OuterSurfaceArea: 0.04194 m2; NetVolume: 0.00012312 m3; NetWeight: 0 kg

# IfcColumn: L70*7 (3)
In: Undefined
Description: L70*7; Material: Undefined/S235-E24
Tekla Commun - Repère de pièce: A30; Repère d'assemblage: A30; Phase: 1; Profil: L70*7; Nom: ATTACHE; sets with these values: 2
Tekla Quantités - Poids: 0 kg; Volume: 0 m3; Surface supérieure totale: 0 m2; Surface par tonne: 0 m2; Surface nette: 0 m2; Hauteur: 70 mm; Largeur: 70 mm; Longueur: 100 mm; sets with these values: 2
Pset_ColumnCommon - LoadBearing: no; Reference: A30
BaseQuantities - Length: 100 mm; OuterSurfaceArea: 0.0272 m2; NetVolume: 0.0000931 m3; NetWeight: 0 kg

# IfcColumn: L80*8 (3)
In: Undefined
Description: L80*8; Material: Undefined/S235-E24
Tekla Quantités - Poids: 0 kg; Volume: 0 m3; Surface supérieure totale: 0 m2; Surface par tonne: 0 m2; Surface nette: 0 m2; Hauteur: 80 mm; Largeur: 80 mm; sets with these values: 2
Tekla Commun - Phase: 1; Profil: L80*8; Nom: ATTACHE; sets with these values: 2
Pset_ColumnCommon - LoadBearing: no
BaseQuantities - NetWeight: 0 kg
Name | Longueur (mm) = Length (mm) | Repère de pièce = Repère d'assemblage = Reference | OuterSurfaceArea (m2) | NetVolume (m3)
2 x ATTACHE | 100 | A18 | 0.0311 | 0.0001216
ATTACHE | 120 | A8 | 0.03732 | 0.00014592

# IfcColumn: PL10*60 (40)
In: Undefined
Description: PL10*60; Material: Undefined/S235-E24
Tekla Quantités - Poids: 0 kg; Volume: 0 m3; Surface supérieure totale: 0 m2; Surface par tonne: 0 m2; Surface nette: 0.1 m2; Hauteur: 60 mm; Largeur: 10 mm; sets with these values: 2
BaseQuantities - NetWeight: 0 kg
Tekla Commun - Profil: PL10*60; Nom: MONTANT; sets with these values: 2
Pset_ColumnCommon - LoadBearing: no
Name | Longueur (mm) | Length (mm) | OuterSurfaceArea (m2) | NetVolume (m3) | Repère de pièce = Reference | Repère d'assemblage | Phase
MONTANT | 967.6 | 967.6 | 0.133929 | 0.00056856 | 516 | GC0(?) | 3 | Tekla Commun - Finition: GALVA
MONTANT | 967.6 | 967.6 | 0.133929 | 0.00056856 | 0 | 0(?) | 3 | Tekla Commun - Finition: GALVA
MONTANT | 967.6 | 967.6 | 0.133929 | 0.00056856 | 519 | GC0(?) | 3 | Tekla Commun - Finition: GALVA
2 x MONTANT | 967.6 | 967.6 | 0.133929 | 0.00056856 | 518 | GC12 | 3 | Tekla Commun - Finition: GALVA
2 x MONTANT | 967.6 | 967.6 | 0.133929 | 0.00056856 | 519 | GC12 | 3 | Tekla Commun - Finition: GALVA
MONTANT | 860.1 | 860.124 | 0.117945 | 0.000499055 | 517 | GC12 | 3 | Tekla Commun - Finition: GALVA
MONTANT | 937.6 | 937.6 | 0.129729 | 0.00055056 | 509 | GC3 | 3 | Tekla Commun - Finition: GALVA
MONTANT | 937.6 | 937.6 | 0.129729 | 0.00055056 | 509 | GC2 | 3 | Tekla Commun - Finition: GALVA
12 x MONTANT | 857.6 | 857.6 | 0.118529 | 0.00050256 | 281 | MC3 | 1
2 x MONTANT | 547.6 | 547.6 | 0.0751289 | 0.00031656 | 280 | MC2 | 1
12 x MONTANT | 857.6 | 857.6 | 0.118529 | 0.00050256 | 281 | MC1 | 1
4 x MONTANT | 857.6 | 857.6 | 0.118529 | 0.00050256 | 281 | MC2 | 1

# IfcColumn: PL100*5 (6)
In: Undefined
Description: PL100*5; Material: Undefined/S235-E24
Tekla Commun - Phase: 1; Profil: PL100*5; Nom: FEUILLURE; sets with these values: 2
Tekla Quantités - Poids: 0 kg; Volume: 0 m3; Surface supérieure totale: 0 m2; Surface par tonne: 0 m2; Hauteur: 100 mm; Largeur: 5 mm; sets with these values: 2
Pset_ColumnCommon - LoadBearing: no
BaseQuantities - NetWeight: 0 kg
Name | Repère de pièce = Reference | Repère d'assemblage | Surface nette (m2) | Longueur (mm) = Length (mm) | OuterSurfaceArea (m2) | NetVolume (m3)
2 x FEUILLURE | 142 | M15 | 0.4 | 1845 | 0.38845 | 0.0009225
2 x FEUILLURE | 141 | M14 | 0.6 | 2670 | 0.5617 | 0.001335
2 x FEUILLURE | 140 | M13 | 0.7 | 3470 | 0.7297 | 0.001735

# IfcColumn: PL2*100 (7)
In: Undefined
Description: PL2*100; Material: MISCELLANEOUS/PVC
Tekla Commun - Repère de pièce: O1; Repère d'assemblage: O1; Phase: 3; Profil: PL2*100; Nom: OBTURATEUR; sets with these values: 2
Tekla Quantités - Poids: 0 kg; Volume: 0 m3; Surface supérieure totale: 0 m2; Surface par tonne: 737.6 m2; Surface nette: 0 m2; Hauteur: 100 mm; Largeur: 2 mm; Longueur: 100 mm; sets with these values: 2
Pset_ColumnCommon - LoadBearing: no; Reference: O1
BaseQuantities - Length: 100.004 mm; OuterSurfaceArea: 0.0208008 m2; NetVolume: 0.0000200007 m3; NetWeight: 0.028201 kg

# IfcColumn: PL5*60 (18)
In: Undefined
Description: PL5*60; Material: Undefined/S235-E24
Tekla Commun - Repère de pièce: 304; Phase: 1; Profil: PL5*60; Nom: MONTANT; sets with these values: 2
Tekla Quantités - Poids: 0 kg; Volume: 0 m3; Surface supérieure totale: 0 m2; Surface par tonne: 0 m2; Surface nette: 0.1 m2; Hauteur: 60 mm; Largeur: 5 mm; Longueur: 807.6 mm; sets with these values: 2
Pset_ColumnCommon - LoadBearing: no; Reference: 304
BaseQuantities - Length: 807.6 mm; OuterSurfaceArea: 0.10302 m2; NetVolume: 0.00023628 m3; NetWeight: 0 kg
Name | Repère d'assemblage
4 x MONTANT | MC3
12 x MONTANT | MC1
2 x MONTANT | MC2

# IfcColumn: PL6*100 (5)
In: Undefined
Description: PL6*100; Material: Undefined/S235-E24
Tekla Commun - Phase: 1; Profil: PL6*100; Nom: CALE; sets with these values: 2
Tekla Quantités - Poids: 0 kg; Volume: 0 m3; Surface supérieure totale: 0 m2; Surface par tonne: 0 m2; Surface nette: 0 m2; Hauteur: 100 mm; Largeur: 6 mm; sets with these values: 2
Pset_ColumnCommon - LoadBearing: no
BaseQuantities - NetWeight: 0 kg
Name | Repère de pièce = Repère d'assemblage = Reference | Longueur (mm) = Length (mm) | OuterSurfaceArea (m2) | NetVolume (m3)
2 x CALE | C2 | 100 | 0.0224 | 0.00006
3 x CALE | C1 | 95 | 0.02134 | 0.000057

# IfcColumn: PL8*100, CALE
In: Undefined
Description: PL8*100; Material: Undefined/S235-E24
Tekla Commun - Repère de pièce: C3; Repère d'assemblage: C3; Phase: 1; Profil: PL8*100; Nom: CALE; sets with these values: 2
Tekla Quantités - Poids: 0 kg; Volume: 0 m3; Surface supérieure totale: 0 m2; Surface par tonne: 0 m2; Surface nette: 0 m2; Hauteur: 100 mm; Largeur: 8 mm; Longueur: 95 mm; sets with these values: 2
Pset_ColumnCommon - LoadBearing: no; Reference: C3
BaseQuantities - Length: 95 mm; OuterSurfaceArea: 0.02212 m2; NetVolume: 0.000076 m3; NetWeight: 0 kg

# IfcColumn: TUBE-C-100*100*4 (14)
In: Undefined
Description: TUBE-C-100*100*4; Material: Undefined/S235-E24
Tekla Commun - Phase: 1; Profil: TUBE-C-100*100*4; Nom: MONTANT; sets with these values: 2
Tekla Quantités - Poids: 0 kg; Volume: 0 m3; Surface supérieure totale: 0 m2; Surface par tonne: 0 m2; Hauteur: 100 mm; Largeur: 100 mm; sets with these values: 2
Pset_ColumnCommon - LoadBearing: no
BaseQuantities - NetWeight: 0 kg
Name | Repère de pièce = Reference | Repère d'assemblage | Surface nette (m2) | Longueur (mm) = Length (mm) | OuterSurfaceArea (m2) | NetVolume (m3)
3 x MONTANT | M10 | M10 | 0.8 | 2090 | 0.80674 | 0.00321024
2 x MONTANT | 88 | M15 | 0.7 | 1635 | 0.63111 | 0.00251136
2 x MONTANT | 87 | M14 | 1 | 2460 | 0.94956 | 0.00377856
2 x MONTANT | 86 | M13 | 1.3 | 3260 | 1.25836 | 0.00500736
2 x MONTANT | M12 | M12 | 0.8 | 2070 | 0.79902 | 0.00317952
MONTANT | M17 | M17 | 1.5 | 3830 | 1.47838 | 0.00588288
2 x MONTANT | M11 | M11 | 0.7 | 1690 | 0.65234 | 0.00259584

# IfcColumn: TUBE-C-100*100*5 (14)
In: Undefined
Description: TUBE-C-100*100*5; Material: Undefined/S235-E24
Tekla Commun - Finition: GALVA; Phase: 3; Profil: TUBE-C-100*100*5; Nom: POTELET; sets with these values: 2
Tekla Quantités - Poids: 0 kg; Volume: 0 m3; Surface supérieure totale: 0 m2; Surface par tonne: 0 m2; Hauteur: 100 mm; Largeur: 100 mm; sets with these values: 2
Pset_ColumnCommon - LoadBearing: no
BaseQuantities - NetWeight: 0 kg
Name | Repère de pièce = Reference | Repère d'assemblage | Surface nette (m2) | Longueur (mm) = Length (mm) | OuterSurfaceArea (m2) | NetVolume (m3)
6 x POTELET | 565 | P4 | 0.6 | 1370 | 0.52471 | 0.002603
8 x POTELET | 564 | P3 | 0.3 | 780 | 0.29874 | 0.001482

# IfcColumn: TUBE-C-80*80*4 (4)
In: Undefined
Description: TUBE-C-80*80*4; Material: Undefined/S235-E24
Tekla Commun - Phase: 1; Profil: TUBE-C-80*80*4; Nom: MONTANT BARDAGE; sets with these values: 2
Tekla Quantités - Poids: 0 kg; Volume: 0 m3; Surface supérieure totale: 0 m2; Surface par tonne: 0 m2; Hauteur: 80 mm; Largeur: 80 mm; sets with these values: 2
Pset_ColumnCommon - LoadBearing: no
BaseQuantities - NetWeight: 0 kg
Name | Repère de pièce = Repère d'assemblage = Reference | Surface nette (m2) | Longueur (mm) = Length (mm) | OuterSurfaceArea (m2) | NetVolume (m3)
MONTANT BARDAGE | M21 | 1.6 | 5070 | 1.55142 | 0.00616512
2 x MONTANT BARDAGE | M1 | 1.1 | 3440 | 1.05264 | 0.00418304
MONTANT BARDAGE | M2 | 1.8 | 5570 | 1.70442 | 0.00677312

# IfcColumn: TUBE-R-100*50*3 (9)
In: Undefined
Description: TUBE-R-100*50*3; Material: Undefined/S235-E24
Tekla Commun - Phase: 1; Profil: TUBE-R-100*50*3; Nom: SUSPENTE; sets with these values: 2
Tekla Quantités - Poids: 0 kg; Volume: 0 m3; Surface supérieure totale: 0 m2; Surface par tonne: 0 m2; Hauteur: 100 mm; Largeur: 50 mm; sets with these values: 2
Pset_ColumnCommon - LoadBearing: no
BaseQuantities - NetWeight: 0 kg
Name | Repère de pièce = Reference | Repère d'assemblage | Surface nette (m2) | Longueur (mm) | Length (mm) | OuterSurfaceArea (m2) | NetVolume (m3)
3 x SUSPENTE | 209 | S22 | 0.4 | 1472.8 | 1472.77 | 0.425632 | 0.0012618
3 x SUSPENTE | 208 | S21 | 0.7 | 2250.8 | 2250.8 | 0.650481 | 0.0019335
3 x SUSPENTE | 207 | S20 | 0.9 | 3000.2 | 3000.17 | 0.86705 | 0.00258085

# IfcColumn: UPF-100*50*4 (4)
In: Undefined
Description: UPF-100*50*4; Material: Undefined/S235-E24
Tekla Commun - Phase: 1; Profil: UPF-100*50*4; Nom: BAIONNETTE; sets with these values: 2
Tekla Quantités - Poids: 0 kg; Volume: 0 m3; Surface supérieure totale: 0 m2; Surface par tonne: 0 m2; Hauteur: 100 mm; Largeur: 50 mm; sets with these values: 2
Pset_ColumnCommon - LoadBearing: no
BaseQuantities - NetWeight: 0 kg
Name | Repère de pièce = Repère d'assemblage = Reference | Surface nette (m2) | Longueur (mm) | Length (mm) | OuterSurfaceArea (m2) | NetVolume (m3)
BAIONNETTE | B6 | 0.3 | 755 | 754.999 | 0.275055 | 0.000534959
BAIONNETTE | B12 | 0.2 | 670 | 669.999 | 0.241735 | 0.000469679
BAIONNETTE | B10 | 0.3 | 790 | 789.999 | 0.288775 | 0.000561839
BAIONNETTE | B8 | 0.3 | 910 | 909.999 | 0.335815 | 0.000653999

# IfcDiscreteAccessory: GOUSSET
In: Undefined
Description: BL225*6; Material: STEEL/S235J0
Tekla Commun - Repère de pièce: PN24; Repère d'assemblage: PN24; Phase: 1; Profil: BL225*6; Nom: GOUSSET
Tekla Quantités - Poids: 1.8 kg; Volume: 0 m3; Surface supérieure totale: 0 m2; Surface par tonne: 45 m2; Surface nette: 0.1 m2; Hauteur: 225 mm; Largeur: 6 mm; Longueur: 202.8 mm
Pset_PlateCommon - LoadBearing: no; Reference: PN24
BaseQuantities - NetArea: 0.0804402 m2; GrossArea: 0.0963936 m2; CrossSectionArea: 0.00135 m2; NetVolume: 0.000227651 m3; GrossVolume: 0.00027378 m3

# IfcElementAssembly (1554)
In: Undefined
Tekla Assemblages - sets with these values: 2
Name | Poids Assemblage/Elément béton (kg) | Nom Assemblage/Elément béton | Repère Assemblage/Elément béton | Width (mm)
Steel Assembly | 0.00628 | GOUSSET | G0(?) | 2 | PredefinedType: RIGID_FRAME
Steel Assembly | 0 | CORNIERE | S0(?) | 60 | PredefinedType: RIGID_FRAME
Steel Assembly | 0 | STABILITE CVT | S0(?) | 60 | PredefinedType: RIGID_FRAME
Steel Assembly | 1.78706 | GOUSSET | PN24 | 6 | PredefinedType: RIGID_FRAME
5 x COIFFE | 0 | COIFFE | C0(?) | 134.078
2 x COIFFE | 0 | COIFFE | C4(?) | 456.94
4 x CACHE VIDE | 0 | CACHE VIDE | GC0(?) | 6
MAIN COURANTE | 0 | MAIN COURANTE | GC0(?) | 6
COIFFE | 0 | COIFFE | C5(?) | 101.774
MAIN COURANTE | 0 | MAIN COURANTE | GC0(?) | 977.6
2 x MONTANT | 0 | MONTANT | 0(?) | 10
2 x MAIN COURANTE | 0 | MAIN COURANTE | GC0(?) | 901.923
7 x CONSOLE | 0 | CONSOLE | C9 | 300
PLINTHE | 0 | PLINTHE | 0(?) | 5
PLATINE | 0 | PLATINE | 0(?) | 10
MAIN COURANTE | 0 | MAIN COURANTE | GC12 | 2117.35
MAIN COURANTE | 0 | MAIN COURANTE | GC8 | 2117.35
MAIN COURANTE | 0 | MAIN COURANTE | GC10 | 977.6
MAIN COURANTE | 0 | MAIN COURANTE | GC4 | 977.6
2 x MAIN COURANTE | 0 | MAIN COURANTE | GC2 | 1211.44
MAIN COURANTE | 0 | MAIN COURANTE | GC6 | 977.6
MAIN COURANTE | 0 | MAIN COURANTE | GC3 | 1211.45
MAIN COURANTE | 0 | MAIN COURANTE | GC1 | 1211.44
2 x MAIN COURANTE | 0 | MAIN COURANTE | GC3 | 1211.44
MAIN COURANTE | 0 | MAIN COURANTE | GC7 | 977.6
6 x POTELET | 0 | POTELET | P4 | 300
PALIER | 0 | PALIER | P6(?) | 30
12 x PALIER | 0 | PALIER | P10(?) | 30
SUPPORT | 0 | SUPPORT | S51 | 50
SUPPORT | 0 | SUPPORT | S33 | 50
4 x ATTACHE | 0 | ATTACHE | A45 | 60
12 x MARCHE | 0 | MARCHE | M18 | 70
3 x LIMON | 0 | LIMON | L90 | 90.0092
3 x LIMON | 0 | LIMON | L89 | 90.0011
6 x DALLE SUR PLOT | 30 | DALLE SUR PLOT | DP1 | 50 | PredefinedType: REINFORCEMENT_UNIT; Tekla Assemblages - Poids ferraillage Elément béton: 0 kg
3 x Steel Assembly | 1.875 | STYRODUR | S55 | 50
3 x SUPPORT | 0 | SUPPORT | S54 | 50
3 x SUPPORT | 0 | SUPPORT | S53 | 50
6 x ATTACHE | 0 | ATTACHE | A80 | 140
3 x PALIER | 0 | PALIER | P5(?) | 30
SUPPORT | 0 | SUPPORT | S25 | 50
10 x MARCHE | 0 | MARCHE | M37 | 70
8 x POTELET | 0 | POTELET | P3 | 300
LIMON | 0 | LIMON | L33(?) | 90.0065
LIMON | 0 | LIMON | L63 | 90.0018
2 x COIFFE | 0 | COIFFE | C5 | 101.774
14 x ATTACHE | 0 | ATTACHE | A29 | 60
4 x SUPPORT | 0 | SUPPORT | S35 | 50
2 x SUPPORT | 0 | SUPPORT | S52 | 50
2 x SUPPORT | 0 | SUPPORT | S36 | 50
2 x PALIER | 0 | PALIER | P11(?) | 30
LIMON | 0 | LIMON | L91 | 90
7 x Steel Assembly | 0.0282 | OBTURATEUR | O1 | 2
2 x LIMON | 0 | LIMON | L92(?) | 90
COIFFE | 0 | COIFFE | C8(?) | 561.113
4 x PANNE SHED | 0 | PANNE SHED | PN21 | 140
2 x PANNE SHED | 0 | PANNE SHED | PN20 | 140
SUPPORT | 0 | SUPPORT | S50 | 4
SUPPORT | 0 | SUPPORT | S49 | 4
2 x SUPPORT | 0 | SUPPORT | S46 | 4
3 x SUPPORT | 0 | SUPPORT | S45 | 4
2 x CONTRE PLATINE | 0 | CONTRE PLATINE | CP1 | 10
14 x ATTACHE | 0 | ATTACHE | A78 | 80
SUPPORT | 0 | SUPPORT | S44 | 50
SUPPORT | 0 | SUPPORT | S43 | 50
14 x ATTACHE | 0 | ATTACHE | A79 | 80
5 x CONSOLE | 0 | CONSOLE | C11 | 200
2 x CONSOLE | 0 | CONSOLE | C12 | 200
4 x ATTACHE | 0 | ATTACHE | A77 | 75
SUPPORT | 0 | SUPPORT | S47 | 75
SUPPORT | 0 | SUPPORT | S48 | 75
SUPPORT | 0 | SUPPORT | S42 | 10
SUPPORT | 0 | SUPPORT | S16 | 10
4 x ATTACHE | 0 | ATTACHE | A75 | 200
ATTACHE | 0 | ATTACHE | A76 | 70
LISSE CHASSIS | 0 | LISSE CHASSIS | L29 | 170
2 x BAVETTE | 0 | BAVETTE | X1 | 43.7883
4 x GOUSSET | 0 | GOUSSET | G32 | 5
4 x ATTACHE | 0 | ATTACHE | A16 | 147
POTEAU | 0 | POTEAU | PT11 | 180
POTEAU | 0 | POTEAU | PT13 | 180
GOUSSET | 0 | GOUSSET | G31 | 5
4 x GOUSSET | 0 | GOUSSET | G30 | 5
4 x STABILITE CVT | 0 | STABILITE CVT | S15 | 40
4 x GOUSSET | 0 | GOUSSET | G29 | 160
2 x GOUSSET | 0 | GOUSSET | G11 | 82
2 x GOUSSET | 0 | GOUSSET | G28 | 160
2 x BUTON | 0 | BUTON | B14 | 80
SUPPORT | 0 | SUPPORT | S41 | 50
LIMON | 0 | LIMON | L5(?) | 90.0039
LIMON | 0 | LIMON | L75(?) | 90.0074
PALIER | 0 | PALIER | P8(?) | 30
COIFFE | 0 | COIFFE | C6 | 541.223
LIMON | 0 | LIMON | L88 | 90
LIMON | 0 | LIMON | L87(?) | 90
COIFFE | 0 | COIFFE | C7(?) | 630.73
LIMON | 0 | LIMON | L93 | 90
CAILLEBOTIS | 0 | CAILLEBOTIS | CA4 | 30
11 x CAILLEBOTIS | 0 | CAILLEBOTIS | CA3 | 30
12 x CAILLEBOTIS | 0 | CAILLEBOTIS | CA2 | 30
24 x CAILLEBOTIS | 0 | CAILLEBOTIS | CA1 | 30
SUPPORT | 0 | SUPPORT | S10 | 70
SUPPORT | 0 | SUPPORT | S32 | 70
7 x GOUSSET | 0 | GOUSSET | G12 | 6
24 x ATTACHE | 0 | ATTACHE | A28 | 60
LISSE CHASSIS | 0 | LISSE CHASSIS | L25 | 170
LISSE CHASSIS | 0 | LISSE CHASSIS | L55 | 170
LISSE CHASSIS | 0 | LISSE CHASSIS | L2 | 170
2 x ATTACHE | 0 | ATTACHE | A13 | 170
4 x ATTACHE | 0 | ATTACHE | A18 | 80
ATTACHE | 0 | ATTACHE | A12 | 64.3434
ATTACHE | 0 | ATTACHE | A12 | 117.724
SUPPORT CHARGE BARDAG | 0 | SUPPORT CHARGE BARDAG | S26 | 260
4 x SUPPORT CHARGE BARDAG | 0 | SUPPORT CHARGE BARDAG | S23 | 260
SUPPORT CHARGE BARDAG | 0 | SUPPORT CHARGE BARDAG | S24 | 260
60 x PANNE SHED | 0 | PANNE SHED | PN19 | 150
FEUILLURE | 0 | FEUILLURE | F12 | 130
FEUILLURE | 0 | FEUILLURE | F11 | 130
FEUILLURE | 0 | FEUILLURE | F9 | 130
FEUILLURE | 0 | FEUILLURE | F8 | 80
BUTON | 0 | BUTON | B5 | 129.254
113 x PLAQUETTE | 0 | PLAQUETTE | P1 | 8
3 x PLAQUETTE | 0 | PLAQUETTE | P2 | 6
2 x GOUSSET | 0 | GOUSSET | G19 | 6
2 x LIERNE | 0 | LIERNE | L79 | 50
2 x LIERNE | 0 | LIERNE | L78 | 50
LIERNE | 0 | LIERNE | L83 | 50
3 x LIERNE | 0 | LIERNE | L80 | 50
LIERNE | 0 | LIERNE | L82 | 50
LIERNE | 0 | LIERNE | L81 | 50
4 x GOUSSET | 0 | GOUSSET | G22 | 6
4 x GOUSSET | 0 | GOUSSET | G21 | 6
2 x STABILITE CVT | 0 | STABILITE CVT | S39 | 50
2 x STABILITE CVT | 0 | STABILITE CVT | S40 | 50
GOUSSET | 0 | GOUSSET | G25 | 6
2 x LIERNE | 0 | LIERNE | L84 | 50
GOUSSET | 0 | GOUSSET | G24 | 6
8 x STABILITE CVT | 0 | STABILITE CVT | S9 | 50
4 x GOUSSET | 0 | GOUSSET | G23 | 6
LIERNE | 0 | LIERNE | L86 | 50
LIERNE | 0 | LIERNE | L85 | 50
3 x GOUSSET | 0 | GOUSSET | G20 | 6
6 x GOUSSET | 0 | GOUSSET | G26 | 6
4 x MAIN COURANTE | 0 | MAIN COURANTE | MC3 | 60
2 x MAIN COURANTE | 0 | MAIN COURANTE | MC2 | 60
6 x POUTRE | 0 | POUTRE | A70 | 40
POUTRE | 0 | POUTRE | A2 | 40
2 x POUTRE | 0 | POUTRE | A69 | 40
2 x POUTRE | 0 | POUTRE | A71 | 40
POUTRE | 0 | POUTRE | A72 | 40
POTEAU | 0 | POTEAU | PT10 | 334.997
12 x ATTACHE | 0 | ATTACHE | A37 | 70
ATTACHE | 0 | ATTACHE | A31 | 70
2 x ATTACHE | 0 | ATTACHE | A67 | 160.219
2 x ATTACHE | 0 | ATTACHE | A5 | 130
3 x STABILITE CVT | 0 | STABILITE CVT | S38 | 50
4 x ATTACHE | 0 | ATTACHE | A54 | 70
32 x ATTACHE | 0 | ATTACHE | A53 | 100
MONTANT | 0 | MONTANT | M36 | 146.311
2 x ATTACHE | 0 | ATTACHE | A52 | 100
TRAVERSE | 0 | TRAVERSE | T3 | 190
TRAVERSE | 0 | TRAVERSE | T4 | 210
3 x ATTACHE | 0 | ATTACHE | A26 | 60
TRAVERSE | 0 | TRAVERSE | T5 | 210
2 x MONTANT | 0 | MONTANT | M20 | 200
6 x MAIN COURANTE | 0 | MAIN COURANTE | MC1 | 60
8 x STABILITE CVT | 0 | STABILITE CVT | S7 | 60
3 x SUSPENTE | 0 | SUSPENTE | S22 | 192.866
3 x SUSPENTE | 0 | SUSPENTE | S21 | 191.054
3 x SUSPENTE | 0 | SUSPENTE | S20 | 190.713
12 x SOLIVE | 0 | SOLIVE | S18 | 60
3 x SUPPORT | 0 | SUPPORT | S37 | 50
3 x SUPPORT | 0 | SUPPORT | S13 | 50
ATTACHE | 0 | ATTACHE | A50 | 100
11 x ATTACHE | 0 | ATTACHE | A30 | 70
3 x SUPPORT | 0 | SUPPORT | S19 | 50.1324
3 x SUPPORT | 0 | SUPPORT | S17 | 69.9655
4 x ATTACHE | 0 | ATTACHE | A15 | 80
2 x CALE | 0 | CALE | C2 | 6
3 x CALE | 0 | CALE | C1 | 6
35 x ATTACHE | 0 | ATTACHE | A46 | 100
5 x ATTACHE | 0 | ATTACHE | A62 | 64.0839
ATTACHE | 0 | ATTACHE | A66 | 176.932
2 x ATTACHE | 0 | ATTACHE | A65 | 110.386
ATTACHE | 0 | ATTACHE | A66 | 176.941
ATTACHE | 0 | ATTACHE | A4 | 129.936
ATTACHE | 0 | ATTACHE | A3 | 130.25
CALE | 0 | CALE | C3 | 8
ATTACHE | 0 | ATTACHE | A49 | 100
ATTACHE | 0 | ATTACHE | A48 | 100
ATTACHE | 0 | ATTACHE | A47 | 100
8 x ATTACHE | 0 | ATTACHE | A64 | 181.441
11 x ATTACHE | 0 | ATTACHE | A63 | 110.244
4 x GOUSSET | 0 | GOUSSET | G27 | 6
12 x ATTACHE | 0 | ATTACHE | A27 | 60
8 x GOUSSET | 0 | GOUSSET | G18 | 6
8 x STABILITE CVT | 0 | STABILITE CVT | S8 | 50
4 x GOUSSET | 0 | GOUSSET | G17 | 6
7 x GOUSSET | 0 | GOUSSET | G14 | 6
GOUSSET | 0 | GOUSSET | G15 | 6
8 x ATTACHE | 0 | ATTACHE | A68 | 60
8 x BUTON | 0 | BUTON | B13 | 40
4 x GOUSSET | 0 | GOUSSET | G16 | 6
GOUSSET | 0 | GOUSSET | G13 | 6
8 x STABILITE CVT | 0 | STABILITE CVT | S6 | 60
ATTACHE | 0 | ATTACHE | A36 | 70
DALLE | 22200 | DALLE | Da8 | 200 | PredefinedType: REINFORCEMENT_UNIT; Tekla Assemblages - Poids ferraillage Elément béton: 0 kg
2 x ATTACHE | 0 | ATTACHE | A56 | 100
2 x ATTACHE | 0 | ATTACHE | A57 | 70
TRAVERSE SHED | 0 | TRAVERSE SHED | TS15 | 150
TRAVERSE SHED | 0 | TRAVERSE SHED | TS5 | 150
TRAVERSE SHED | 0 | TRAVERSE SHED | TS14 | 150.24
TRAVERSE SHED | 0 | TRAVERSE SHED | TS11 | 150.24
TRAVERSE SHED | 0 | TRAVERSE SHED | TS12 | 150.24
TRAVERSE SHED | 0 | TRAVERSE SHED | TS13 | 150.24
TRAVERSE SHED | 0 | TRAVERSE SHED | TS1 | 150.24
TRAVERSE SHED | 0 | TRAVERSE SHED | TS2 | 150.24
TRAVERSE SHED | 0 | TRAVERSE SHED | TS3 | 150.24
TRAVERSE SHED | 0 | TRAVERSE SHED | TS4 | 150.24
TRAVERSE SHED | 0 | TRAVERSE SHED | TS10 | 140.922
TRAVERSE SHED | 0 | TRAVERSE SHED | TS6 | 150.24
TRAVERSE SHED | 0 | TRAVERSE SHED | TS7 | 150.24
TRAVERSE SHED | 0 | TRAVERSE SHED | TS8 | 150.24
TRAVERSE SHED | 0 | TRAVERSE SHED | TS9 | 150.24
6 x ATTACHE | 0 | ATTACHE | A35 | 70
2 x LISSE CONTREBARDAGE | 0 | LISSE CONTREBARDAGE | L71 | 50
3 x LISSE CONTREBARDAGE | 0 | LISSE CONTREBARDAGE | L67 | 50
3 x LISSE CONTREBARDAGE | 0 | LISSE CONTREBARDAGE | L66 | 50
2 x ATTACHE | 0 | ATTACHE | A58 | 100
GOUSSET | 0 | GOUSSET | G10 | 64.1569
GOUSSET | 0 | GOUSSET | G7 | 6
6 x ATTACHE | 0 | ATTACHE | A14 | 40
GOUSSET | 0 | GOUSSET | G9 | 64.1569
GOUSSET | 0 | GOUSSET | G6 | 6
GOUSSET | 0 | GOUSSET | G8 | 64.1569
GOUSSET | 0 | GOUSSET | G5 | 6
3 x ATTACHE | 0 | ATTACHE | A17 | 80
GOUSSET | 0 | GOUSSET | G4 | 6
3 x GOUSSET | 0 | GOUSSET | G2 | 6
3 x GOUSSET | 0 | GOUSSET | G1 | 6
GOUSSET | 0 | GOUSSET | G3 | 6
16 x ATTACHE | 0 | ATTACHE | A25 | 60
2 x ATTACHE | 0 | ATTACHE | A59 | 100
ATTACHE | 0 | ATTACHE | A61 | 70
15 x ATTACHE | 0 | ATTACHE | A60 | 100
ATTACHE | 0 | ATTACHE | A43 | 80
ATTACHE | 0 | ATTACHE | A42 | 80
2 x ATTACHE | 0 | ATTACHE | A41 | 80
2 x ATTACHE | 0 | ATTACHE | A40 | 80
28 x ATTACHE | 0 | ATTACHE | A38 | 80
18 x ATTACHE | 0 | ATTACHE | A55 | 100
2 x ATTACHE | 0 | ATTACHE | A51 | 100
ATTACHE | 0 | ATTACHE | A24 | 100
2 x ATTACHE | 0 | ATTACHE | A23 | 100
4 x ATTACHE | 0 | ATTACHE | A19 | 100
10 x ATTACHE | 0 | ATTACHE | A22 | 100
MONTANT | 0 | MONTANT | M7 | 335.921
MONTANT | 0 | MONTANT | M8 | 511.83
MONTANT | 0 | MONTANT | M34 | 355.915
MONTANT | 0 | MONTANT | M29 | 511.83
MONTANT | 0 | MONTANT | M27 | 511.83
LONGERON | 0 | LONGERON | L43 | 140
2 x ECLISSE | 0 | ECLISSE | E1 | 10
3 x ECLISSE | 0 | ECLISSE | E4 | 10
MONTANT | 0 | MONTANT | M3 | 317.856
MONTANT | 0 | MONTANT | M5 | 335.962
MONTANT | 0 | MONTANT | M33 | 335.957
MONTANT | 0 | MONTANT | M6 | 471.914
MONTANT | 0 | MONTANT | M28 | 471.914
8 x ECLISSE | 0 | ECLISSE | E3 | 10
LONGERON | 0 | LONGERON | L42 | 180
MONTANT | 0 | MONTANT | M26 | 471.914
LONGERON | 0 | LONGERON | L41 | 200
MONTANT | 0 | MONTANT | M4 | 435.7
MONTANT | 0 | MONTANT | M25 | 435.701
MONTANT | 0 | MONTANT | M30 | 317.85
MONTANT | 0 | MONTANT | M24 | 435.701
MONTANT | 0 | MONTANT | M23 | 410
2 x ECLISSE | 0 | ECLISSE | E2 | 10
TRAVERSE HAUTE | 0 | TRAVERSE HAUTE | TH2 | 200
TRAVERSE BASSE | 0 | TRAVERSE BASSE | TB2 | 200
ATTACHE | 0 | ATTACHE | A21 | 213.193
MONTANT | 0 | MONTANT | M32 | 438.352
MONTANT | 0 | MONTANT | M22 | 416.951
MONTANT | 0 | MONTANT | M19 | 439.383
MONTANT | 0 | MONTANT | M31 | 487.245
ATTACHE | 0 | ATTACHE | A20 | 239.383
MONTANT | 0 | MONTANT | M35 | 100
42 x ATTACHE | 0 | ATTACHE | A44 | 100
4 x ATTACHE | 0 | ATTACHE | A34 | 70
ATTACHE | 0 | ATTACHE | A33 | 70
LISSE CHASSIS | 0 | LISSE CHASSIS | L24 | 170
LISSE CHASSIS | 0 | LISSE CHASSIS | L58 | 170
LISSE CHASSIS | 0 | LISSE CHASSIS | L23 | 170
LISSE CHASSIS | 0 | LISSE CHASSIS | L21 | 170
LISSE CHASSIS | 0 | LISSE CHASSIS | L52 | 170
18 x ATTACHE | 0 | ATTACHE | A32 | 70
3 x MONTANT | 0 | MONTANT | M10 | 100
6 x ATTACHE | 0 | ATTACHE | A39 | 80
4 x ATTACHE | 0 | ATTACHE | A53(?) | 100
12 x LONGERON | 0 | LONGERON | L3 | 140
4 x LISSE ACROTERE | 0 | LISSE ACROTERE | L16 | 100
3 x LISSE ACROTERE | 0 | LISSE ACROTERE | L44 | 100
3 x LONGERON | 0 | LONGERON | L72 | 70
2 x LONGERON | 0 | LONGERON | L74 | 0
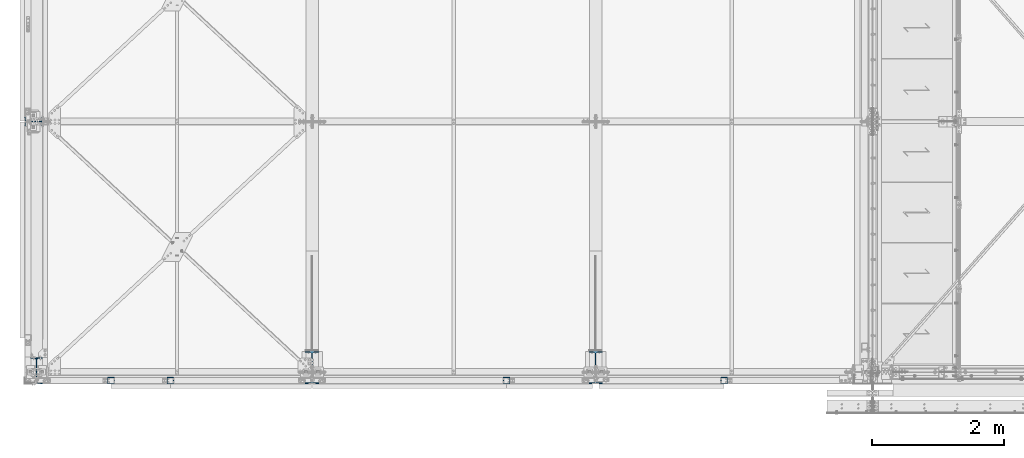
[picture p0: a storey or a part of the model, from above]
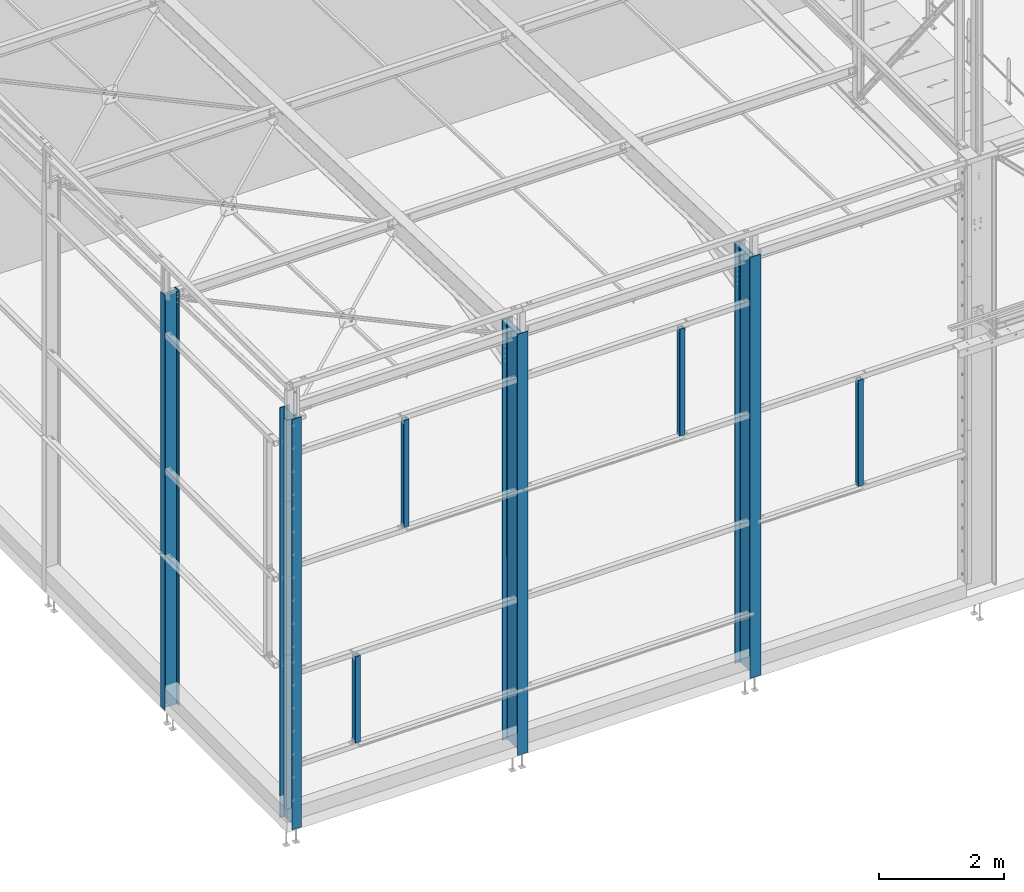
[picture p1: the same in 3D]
Properties of the parts of a building model (IFC2X3), part 4 of 4

# IfcElementAssembly (1554)
Name | Poids Assemblage/Elément béton (kg) | Nom Assemblage/Elément béton | Repère Assemblage/Elément béton | Width (mm)
LONGERON | 0 | LONGERON | L73 | 0
LISSE ACROTERE | 0 | LISSE ACROTERE | L47 | 100
MONTANT BARDAGE | 0 | MONTANT BARDAGE | M21 | 80
LISSE ACROTERE | 0 | LISSE ACROTERE | L46 | 100
LISSE ACROTERE | 0 | LISSE ACROTERE | L49 | 100
18 x PANNE SHED | 0 | PANNE SHED | PN35 | 56
2 x LISSE CHASSIS | 0 | LISSE CHASSIS | L4 | 170
LISSE CHASSIS | 0 | LISSE CHASSIS | L18 | 170
LISSE CHASSIS | 0 | LISSE CHASSIS | L20 | 170
2 x STABILITE | 0 | STABILITE | S29 | 40
2 x STABILITE | 0 | STABILITE | S28 | 40
2 x STABILITE | 0 | STABILITE | S27 | 40
POUTRE | 2174.85 | POUTRE | Po11 | 270 | PredefinedType: REINFORCEMENT_UNIT; Tekla Assemblages - Poids ferraillage Elément béton: 0 kg
POUTRE | 1277.4 | POUTRE | Po9 | 200 | PredefinedType: REINFORCEMENT_UNIT; Tekla Assemblages - Poids ferraillage Elément béton: 0 kg
POUTRE | 1474.8 | POUTRE | Po8 | 200 | PredefinedType: REINFORCEMENT_UNIT; Tekla Assemblages - Poids ferraillage Elément béton: 0 kg
POUTRE | 81 | POUTRE | Po10 | 270 | PredefinedType: REINFORCEMENT_UNIT; Tekla Assemblages - Poids ferraillage Elément béton: 0 kg
DALLE | 298981 | DALLE | Da7 | 200 | PredefinedType: REINFORCEMENT_UNIT; Tekla Assemblages - Poids ferraillage Elément béton: 0 kg
LISSE CHASSIS | 0 | LISSE CHASSIS | L60 | 100
4 x LISSE CHASSIS | 0 | LISSE CHASSIS | L19 | 100
2 x LISSE CHASSIS | 0 | LISSE CHASSIS | L61 | 100
FEUILLURE | 0 | FEUILLURE | F15 | 177.25
2 x FEUILLURE | 0 | FEUILLURE | F14 | 177.25
2 x FEUILLURE | 0 | FEUILLURE | F13 | 177.25
FEUILLURE | 0 | FEUILLURE | F20 | 70
FEUILLURE | 0 | FEUILLURE | F19 | 70
FEUILLURE | 0 | FEUILLURE | F16 | 70
2 x PANNE SHED | 0 | PANNE SHED | PN32 | 140
PANNE SHED | 0 | PANNE SHED | PN31 | 140
PANNE SHED | 0 | PANNE SHED | PN29 | 210
2 x PANNE SHED | 0 | PANNE SHED | PN28 | 210
2 x PANNE SHED | 0 | PANNE SHED | PN34 | 210
4 x PANNE SHED | 0 | PANNE SHED | PN33 | 210
2 x PANNE SHED | 0 | PANNE SHED | PN23 | 140
PANNE SHED | 0 | PANNE SHED | PN22 | 140
PANNE SHED | 0 | PANNE SHED | PN27 | 210
2 x PANNE SHED | 0 | PANNE SHED | PN26 | 210
8 x DIAGONALE | 0 | DIAGONALE | D1 | 45
8 x DIAGONALE | 0 | DIAGONALE | D2 | 45
8 x DIAGONALE | 0 | DIAGONALE | D3 | 45
6 x STABILITE CVT | 0 | STABILITE CVT | S30 | 60
2 x STABILITE CVT | 0 | STABILITE CVT | S31 | 60
TRAVERSE | 0 | TRAVERSE | T7 | 190
TRAVERSE | 0 | TRAVERSE | T1 | 190
6 x LISSE CONTREBARDAGE | 0 | LISSE CONTREBARDAGE | L65 | 50
4 x LISSE CONTREBARDAGE | 0 | LISSE CONTREBARDAGE | L26 | 50
2 x LISSE CONTREBARDAGE | 0 | LISSE CONTREBARDAGE | L70 | 50
LISSE CONTREBARDAGE | 0 | LISSE CONTREBARDAGE | L69 | 50
BAIONNETTE | 0 | BAIONNETTE | B6 | 50
BAIONNETTE | 0 | BAIONNETTE | B16 | 50
2 x SABOT | 0 | SABOT | S1 | 120.272
3 x PRESCELLEMENT | 0 | PRESCELLEMENT | PS6 | 122
POTEAU | 0 | POTEAU | PT5 | 310
2 x ATTACHE | 0 | ATTACHE | A6 | 100.265
4 x ATTACHE | 0 | ATTACHE | A10 | 100
POTEAU | 0 | POTEAU | PT4 | 310
POTEAU | 0 | POTEAU | PT3 | 310
DALLE | 2217.26 | DALLE | Da3 | 200 | PredefinedType: REINFORCEMENT_UNIT; Tekla Assemblages - Poids ferraillage Elément béton: 0 kg
DALLE | 4030.23 | DALLE | Da2 | 200 | PredefinedType: REINFORCEMENT_UNIT; Tekla Assemblages - Poids ferraillage Elément béton: 0 kg
DALLE | 6459.18 | DALLE | Da1 | 200 | PredefinedType: REINFORCEMENT_UNIT; Tekla Assemblages - Poids ferraillage Elément béton: 0 kg
BAIONNETTE | 0 | BAIONNETTE | B12 | 50
BAIONNETTE | 0 | BAIONNETTE | B11 | 50
BAIONNETTE | 0 | BAIONNETTE | B10 | 50
BAIONNETTE | 0 | BAIONNETTE | B9 | 50
BAIONNETTE | 0 | BAIONNETTE | B8 | 50
BAIONNETTE | 0 | BAIONNETTE | B7 | 50
2 x MONTANT BARDAGE | 0 | MONTANT BARDAGE | M1 | 80
2 x DIAGONALE | 0 | DIAGONALE | D7 | 45
2 x DIAGONALE | 0 | DIAGONALE | D6 | 45
2 x DIAGONALE | 0 | DIAGONALE | D8 | 45
2 x DIAGONALE | 0 | DIAGONALE | D5 | 45
2 x DIAGONALE | 0 | DIAGONALE | D9 | 45
2 x DIAGONALE | 0 | DIAGONALE | D4 | 45
TRAVERSE HAUTE | 0 | TRAVERSE HAUTE | TH1 | 200
TRAVERSE BASSE | 0 | TRAVERSE BASSE | TB1 | 200
2 x MONTANT | 0 | MONTANT | M15 | 105
2 x MONTANT | 0 | MONTANT | M14 | 105
2 x MONTANT | 0 | MONTANT | M13 | 105
BAIONNETTE | 0 | BAIONNETTE | B3 | 100
BAIONNETTE | 0 | BAIONNETTE | B2 | 100
BAIONNETTE | 0 | BAIONNETTE | B1 | 100
PRESCELLEMENT | 0 | PRESCELLEMENT | PS5 | 149
6 x ATTACHE | 0 | ATTACHE | A11 | 100
SABOT | 0 | SABOT | S5 | 180
3 x PRESCELLEMENT | 0 | PRESCELLEMENT | PS4 | 122
SABOT | 0 | SABOT | S4 | 180
SABOT | 0 | SABOT | S3 | 180
SABOT | 0 | SABOT | S2 | 120.272
ATTACHE | 0 | ATTACHE | A7 | 100.265
2 x ATTACHE | 0 | ATTACHE | A9 | 100
2 x ATTACHE | 0 | ATTACHE | A8 | 80
PRESCELLEMENT | 0 | PRESCELLEMENT | PS3 | 200
2 x LONGERON | 0 | LONGERON | L38 | 0
LONGERON | 0 | LONGERON | L37 | 0
7 x PRESCELLEMENT PS24 | 0 | PRESCELLEMENT PS24 | PS1 | 500
DALLE | 233208 | DALLE | Da6 | 200 | PredefinedType: REINFORCEMENT_UNIT; Tekla Assemblages - Poids ferraillage Elément béton: 0 kg
DALLE | 148983 | DALLE | Da9 | 230 | PredefinedType: REINFORCEMENT_UNIT; Tekla Assemblages - Poids ferraillage Elément béton: 0 kg
POUTRE | 37962 | POUTRE | Po7 | 200 | PredefinedType: REINFORCEMENT_UNIT; Tekla Assemblages - Poids ferraillage Elément béton: 0 kg
POUTRE | 38372.4 | POUTRE | Po6 | 200 | PredefinedType: REINFORCEMENT_UNIT; Tekla Assemblages - Poids ferraillage Elément béton: 0 kg
POUTRE | 29791.9 | POUTRE | Po5 | 200 | PredefinedType: REINFORCEMENT_UNIT; Tekla Assemblages - Poids ferraillage Elément béton: 0 kg
DALLE | 142505 | DALLE | Da5 | 220 | PredefinedType: REINFORCEMENT_UNIT; Tekla Assemblages - Poids ferraillage Elément béton: 0 kg
DALLE | 71045.8 | DALLE | Da4 | 230 | PredefinedType: REINFORCEMENT_UNIT; Tekla Assemblages - Poids ferraillage Elément béton: 0 kg
2 x FEUILLURE | 0 | FEUILLURE | F18 | 50.0885
2 x STABILTE | 0 | STABILTE | S14 | 40
2 x LISSE | 0 | LISSE | L31 | 50
2 x TRAVERSE | 0 | TRAVERSE | T8 | 82
TRAVERSE | 0 | TRAVERSE | T6 | 82
PANNE | 0 | PANNE | PN37 | 64
PANNE | 0 | PANNE | PN36 | 64
PANNE | 0 | PANNE | PN11 | 64
TRAVERSE | 0 | TRAVERSE | T9 | 82
LONGERON | 0 | LONGERON | L36 | 70
LONGERON | 0 | LONGERON | L35 | 70
LONGERON | 0 | LONGERON | L34 | 70
FEUILLURE | 0 | FEUILLURE | F7 | 130
FEUILLURE | 0 | FEUILLURE | F10 | 130
FEUILLURE | 0 | FEUILLURE | F6 | 130
STABILITE CVT | 0 | STABILITE CVT | S12 | 50
STABILITE CVT | 0 | STABILITE CVT | S11 | 50
Steel Assembly | 0 | STABILITE CVT | S38(?) | 50 | PredefinedType: RIGID_FRAME
3 x LISSE ACROTERE | 0 | LISSE ACROTERE | L17 | 100
2 x MONTANT | 0 | MONTANT | M12 | 100
MONTANT | 0 | MONTANT | M17 | 100
2 x MONTANT | 0 | MONTANT | M11 | 100
LISSE CHASSIS | 0 | LISSE CHASSIS | L62 | 100
LISSE CHASSIS | 0 | LISSE CHASSIS | L30 | 100
LISSE CHASSIS | 0 | LISSE CHASSIS | L59 | 100
LISSE CHASSIS | 0 | LISSE CHASSIS | L57 | 100
LISSE CHASSIS | 0 | LISSE CHASSIS | L56 | 100
LISSE CHASSIS | 0 | LISSE CHASSIS | L54 | 100
LISSE CHASSIS | 0 | LISSE CHASSIS | L22 | 100
LISSE CHASSIS | 0 | LISSE CHASSIS | L53 | 100
LISSE CHASSIS | 0 | LISSE CHASSIS | L51 | 100
POTEAU | 0 | POTEAU | PT2 | 270
LISSE CHASSIS | 0 | LISSE CHASSIS | L50 | 100
FEUILLURE | 0 | FEUILLURE | F5 | 80
FEUILLURE | 0 | FEUILLURE | F4 | 80
FEUILLURE | 0 | FEUILLURE | F3 | 80
FEUILLURE | 0 | FEUILLURE | F2 | 80
3 x FEUILLURE | 0 | FEUILLURE | F1 | 80
FEUILLURE | 0 | FEUILLURE | F17 | 80
MONTANT | 0 | MONTANT | M9 | 100
MONTANT | 0 | MONTANT | M16 | 100
LISSE CONTREBARDAGE | 0 | LISSE CONTREBARDAGE | L68 | 50
LISSE CONTREBARDAGE | 0 | LISSE CONTREBARDAGE | L28 | 50
LISSE CONTREBARDAGE | 0 | LISSE CONTREBARDAGE | L27 | 50
MONTANT BARDAGE | 0 | MONTANT BARDAGE | M2 | 80
LISSE ACROTERE | 0 | LISSE ACROTERE | L15 | 100
POTEAU | 0 | POTEAU | PT12 | 334.997
LISSE ACROTERE | 0 | LISSE ACROTERE | L1 | 80
LISSE ACROTERE | 0 | LISSE ACROTERE | L48 | 100
LISSE ACROTERE | 0 | LISSE ACROTERE | L14 | 100
PANNE | 0 | PANNE | PN18 | 64
3 x PANNE | 0 | PANNE | PN10 | 64
PANNE | 0 | PANNE | PN1 | 135
3 x LISSE ACROTERE | 0 | LISSE ACROTERE | L12 | 100
LISSE ACROTERE | 0 | LISSE ACROTERE | L45 | 100
4 x LISSE ACROTERE | 0 | LISSE ACROTERE | L64 | 100
LISSE ACROTERE | 0 | LISSE ACROTERE | L13 | 100
LISSE ACROTERE | 0 | LISSE ACROTERE | L11 | 100
LISSE ACROTERE | 0 | LISSE ACROTERE | L10 | 100
LISSE ACROTERE | 0 | LISSE ACROTERE | L9 | 100
3 x PANNE | 0 | PANNE | PN9 | 100
PANNE | 0 | PANNE | PN15 | 100
PANNE | 0 | PANNE | PN8 | 100
3 x PANNE | 0 | PANNE | PN16 | 91
PANNE | 0 | PANNE | PN17 | 91
PANNE | 0 | PANNE | PN2 | 91
LISSE ACROTERE | 0 | LISSE ACROTERE | L8 | 100
LISSE ACROTERE | 0 | LISSE ACROTERE | L7 | 100
LISSE ACROTERE | 0 | LISSE ACROTERE | L6 | 100
POTEAU | 0 | POTEAU | PT6(?) | 310
2 x PANNE | 0 | PANNE | PN7 | 100
2 x PANNE | 0 | PANNE | PN5 | 100
2 x PANNE | 0 | PANNE | PN14 | 100
3 x PANNE | 0 | PANNE | PN13 | 100
PANNE | 0 | PANNE | PN6 | 100
LONGERON | 0 | LONGERON | L32 | 140
LONGERON | 0 | LONGERON | L40 | 180
LONGERON | 0 | LONGERON | L39 | 200
TRAVERSE | 0 | TRAVERSE | T2 | 190
4 x PRESCELLEMENT PS24 | 0 | PRESCELLEMENT PS24 | PS2 | 500
10 x ATTACHE | 0 | ATTACHE | A1 | 150
RAMASSE PANNE | 0 | RAMASSE PANNE | RP2 | 80
POTEAU | 0 | POTEAU | PT9 | 135
POTEAU | 0 | POTEAU | PT8 | 135
POTEAU | 0 | POTEAU | PT7 | 135
3 x PANNE | 0 | PANNE | PN4 | 100
PANNE | 0 | PANNE | PN3 | 100
Steel Assembly | 93.1815 | PANNE | PN12 | 100 | PredefinedType: RIGID_FRAME
RAMASSE PANNE | 0 | RAMASSE PANNE | RP1 | 80
POUTRE | 20476.6 | POUTRE | Po4 | 200 | PredefinedType: REINFORCEMENT_UNIT; Tekla Assemblages - Poids ferraillage Elément béton: 0 kg
POUTRE | 124128 | POUTRE | Po3 | 200 | PredefinedType: REINFORCEMENT_UNIT; Tekla Assemblages - Poids ferraillage Elément béton: 0 kg
POUTRE | 38782.8 | POUTRE | Po2 | 200 | PredefinedType: REINFORCEMENT_UNIT; Tekla Assemblages - Poids ferraillage Elément béton: 0 kg
POUTRE | 201274 | POUTRE | Po1 | 200 | PredefinedType: REINFORCEMENT_UNIT; Tekla Assemblages - Poids ferraillage Elément béton: 0 kg
POTEAU | 0 | POTEAU | PT1 | 180

# IfcMechanicalFastener: Bolt assembly (2682)
In: Undefined
Tekla Boulons - sets with these values: 2
Name | NominalDiameter (mm) | NominalLength (mm) = Longueur (mm) | Material = Standard | Diamètre (mm)
Bolt assembly | 12 | 25 | 8.8 | 12 | Tekla Boulons - Nom: Boulons tête H
4 x Bolt assembly | 12 | 30 | 8.8 | 12 | Tekla Boulons - Nom: Boulons tête H
Bolt assembly | 12 | 35 | 8.8 | 12 | Tekla Boulons - Nom: Boulons tête H
47 x Bolt assembly | 12 | 50 | 8.8-SB-GALVA | 12
14 x Bolt assembly | 20 | 10 | 6.8 | 22 | Tekla Boulons - Nom: Boulons tête H
34 x Bolt assembly | 12 | 10 | 6.8 | 14 | Tekla Boulons - Nom: Boulons tête H
21 x Bolt assembly | 12 | 12 | 6.8 | 14 | Tekla Boulons - Nom: Boulons tête H
34 x Bolt assembly | 12 | 89.2 | HILTI-HSA-R | 12
14 x Bolt assembly | 30 | 5 | 6.8 | 32 | Tekla Boulons - Nom: Boulons tête H
135 x Bolt assembly | 12 | 40 | 8.8-SB-GALVA | 12
4 x Bolt assembly | 12 | 5 | 6.8 | 14 | Tekla Boulons - Nom: Boulons tête H
4 x Bolt assembly | 8 | 20 | 6.8 | 8 | Tekla Boulons - Nom: Boulons tête H
109 x Bolt assembly | 12 | 30 | 8.8-SB-GALVA | 12
14 x Bolt assembly | 12 | 8 | 6.8 | 14 | Tekla Boulons - Nom: Boulons tête H
6 x Bolt assembly | 6 | 10 | 6.8 | 8 | Tekla Boulons - Nom: Boulons tête H
520 x Bolt assembly | 12 | 30 | 8.8-SB-ZINGUE | 12
24 x Bolt assembly | 12 | 3 | 6.8 | 14 | Tekla Boulons - Nom: Boulons tête H
7 x Bolt assembly | 8 | 30 | 6.8 | 8 | Tekla Boulons - Nom: Boulons tête H
37 x Bolt assembly | 12 | 8.5 | 8.8-SB-ZINGUE | 14
153 x Bolt assembly | 12 | 50 | 8.8-SB-ZINGUE | 12
374 x Bolt assembly | 12 | 40 | 8.8-SB-ZINGUE | 12
10 x Bolt assembly | 12 | 60 | 8.8-SB-ZINGUE | 12
2 x Bolt assembly | 12 | 10.2 | 8.8-SB-ZINGUE | 14
238 x Bolt assembly | 30 | 4 | 6.8 | 30 | Tekla Boulons - Nom: Boulons tête H
4 x Bolt assembly | 12 | 7.4 | #_SB-8.8-ZINGUE | 14
48 x Bolt assembly | 10 | 30 | 6.8 | 10 | Tekla Boulons - Nom: Boulons tête H
2 x Bolt assembly | 12 | 40 | 6.8-SB-ZINGUE | 12
98 x Bolt assembly | 16 | 40 | #_SB-8.8-ZINGUE | 16
193 x Bolt assembly | 16 | 40 | 8.8-SB-ZINGUE | 16
195 x Bolt assembly | 16 | 50 | 8.8-SB-ZINGUE | 16
2 x Bolt assembly | 16 | 6 | 8.8-SB-ZINGUE | 18
41 x Bolt assembly | 16 | 30 | 8.8-SB-ZINGUE | 16
Bolt assembly | 12 | 37.4931 | 8.8-SB-ZINGUE | 12
Bolt assembly | 12 | 38.4931 | 8.8-SB-ZINGUE | 12
50 x Bolt assembly | 27 | 10 | 6.8 | 28 | Tekla Boulons - Nom: Boulons tête H
24 x Bolt assembly | 12 | 40 | #_SB-8.8-ZINGUE | 12
18 x Bolt assembly | 12 | 130 | 6.8 | 12 | Tekla Boulons - Nom: Boulons tête H
15 x Bolt assembly | 6 | 16 | 6.8 | 6 | Tekla Boulons - Nom: Boulons tête H
Bolt assembly | 12 | 140 | 8.8-SB-ZINGUE | 12
2 x Bolt assembly | 12 | 40.4931 | 8.8-SB-ZINGUE | 12
32 x Bolt assembly | 16 | 30 | #_SB-8.8-ZINGUE | 16
3 x Bolt assembly | 12 | 45 | 8.8 | 12 | Tekla Boulons - Nom: Boulons tête H
19 x Bolt assembly | 16 | 146.2 | HILTI-HST-R | 16
Bolt assembly | 16 | 50 | 8.8 | 16 | Tekla Boulons - Nom: Boulons tête H
3 x Bolt assembly | 20 | 60 | HR10.9 | 20 | Tekla Boulons - Nom: Boulons HR tête H
13 x Bolt assembly | 20 | 5.5 | 6.8 | 22 | Tekla Boulons - Nom: Boulons tête H
22 x Bolt assembly | 30 | 15 | 6.8 | 50 | Tekla Boulons - Nom: Boulons tête H
8 x Bolt assembly | 16 | 60 | HR10.9 | 16 | Tekla Boulons - Nom: Boulons HR tête H
6 x Bolt assembly | 16 | 50 | HR10.9 | 16 | Tekla Boulons - Nom: Boulons HR tête H
Bolt assembly | 16 | 70 | HR10.9 | 16 | Tekla Boulons - Nom: Boulons HR tête H
Bolt assembly | 20 | 5 | 6.8 | 22 | Tekla Boulons - Nom: Boulons tête H
22 x Bolt assembly | 24 | 15 | 6.8 | 26 | Tekla Boulons - Nom: Boulons tête H
22 x Bolt assembly | 22 | 15 | 6.8 | 24 | Tekla Boulons - Nom: Boulons tête H
11 x Bolt assembly | 8 | 10 | 6.8 | 10 | Tekla Boulons - Nom: Boulons tête H
11 x Bolt assembly | 24 | 10 | 6.8 | 26 | Tekla Boulons - Nom: Boulons tête H
5 x Bolt assembly | 16 | 60 | 8.8-SB-ZINGUE | 16

# IfcMember: IPE200 (10)
In: Undefined
Description: IPE200; Material: Undefined/S275-E28
Tekla Commun - Phase: 1; Profil: IPE200; Nom: TRAVERSE SHED; sets with these values: 2
Tekla Quantités - Poids: 0 kg; Volume: 0 m3; Surface supérieure totale: 0 m2; Surface par tonne: 0 m2; Hauteur: 200 mm; Largeur: 100 mm; sets with these values: 2
Pset_MemberCommon - LoadBearing: no
BaseQuantities - CrossSectionArea: 0.00285 m2; NetWeight: 0 kg; GrossWeight: 0 kg
Name | Repère de pièce = Reference | Repère d'assemblage | Surface nette (m2) | Longueur (mm) | Length (mm) | OuterSurfaceArea (m2) = GrossSurfaceArea (m2) | NetVolume (m3) | GrossVolume (m3)
TRAVERSE SHED | 109 | TS10 | 3.5 | 4539.2 | 4539.23 | 3.48613 | 0.0120649 | 0.0129368
TRAVERSE SHED | 109 | TS9 | 3.5 | 4539.2 | 4539.23 | 3.48613 | 0.0120649 | 0.0129368
TRAVERSE SHED | 66 | TS8 | 3.5 | 4539.2 | 4539.23 | 3.48613 | 0.0120649 | 0.0129368
TRAVERSE SHED | 37 | TS7 | 3.5 | 4539.2 | 4539.23 | 3.48613 | 0.0120649 | 0.0129368
TRAVERSE SHED | 66 | TS6 | 3.5 | 4539.2 | 4539.23 | 3.48613 | 0.0120649 | 0.0129368
TRAVERSE SHED | 65 | TS5 | 4.6 | 6098 | 6097.96 | 4.68324 | 0.0159487 | 0.0173792
TRAVERSE SHED | 31 | TS4 | 4.7 | 6119.7 | 6119.7 | 4.69993 | 0.0163681 | 0.0174411
TRAVERSE SHED | 60 | TS3 | 4.7 | 6119.7 | 6119.7 | 4.69993 | 0.0163681 | 0.0174411
TRAVERSE SHED | 25 | TS2 | 4.7 | 6119.7 | 6119.7 | 4.69993 | 0.0163681 | 0.0174411
TRAVERSE SHED | 60 | TS1 | 4.7 | 6119.7 | 6119.7 | 4.69993 | 0.0163681 | 0.0174411

# IfcMember: IPE240 (5)
In: Undefined
Description: IPE240; Material: Undefined/S275-E28
Tekla Commun - Phase: 1; Profil: IPE240; Nom: TRAVERSE SHED; sets with these values: 2
Tekla Quantités - Poids: 0 kg; Volume: 0 m3; Surface supérieure totale: 0 m2; Surface par tonne: 0 m2; Hauteur: 240 mm; Largeur: 120 mm; sets with these values: 2
Pset_MemberCommon - LoadBearing: no
BaseQuantities - CrossSectionArea: 0.003909 m2; NetWeight: 0 kg; GrossWeight: 0 kg
Name | Repère de pièce = Reference | Repère d'assemblage | Surface nette (m2) | Longueur (mm) | Length (mm) | OuterSurfaceArea (m2) = GrossSurfaceArea (m2) | NetVolume (m3) | GrossVolume (m3)
TRAVERSE SHED | 77 | TS15 | 7.1 | 7780.8 | 7780.75 | 7.17385 | 0.0278462 | 0.030415
TRAVERSE SHED | 242 | TS14 | 7.3 | 7802.3 | 7802.33 | 7.19374 | 0.0285092 | 0.0304993
TRAVERSE SHED | 243 | TS13 | 7.3 | 7802.3 | 7802.33 | 7.19374 | 0.0285092 | 0.0304993
TRAVERSE SHED | 242 | TS12 | 7.3 | 7802.3 | 7802.33 | 7.19374 | 0.0285092 | 0.0304993
TRAVERSE SHED | 72 | TS11 | 7.3 | 7802.3 | 7802.33 | 7.19374 | 0.0285092 | 0.0304993

# IfcMember: L120*80*10 (40)
In: Undefined
Description: L120*80*10; Material: Undefined/S235-E24
Tekla Commun - Phase: 1; Profil: L120*80*10; Nom: ATTACHE; sets with these values: 2
Tekla Quantités - Poids: 0 kg; Volume: 0 m3; Surface supérieure totale: 0 m2; Surface par tonne: 0 m2; Surface nette: 0.1 m2; Hauteur: 120 mm; Largeur: 80 mm; sets with these values: 2
Pset_MemberCommon - LoadBearing: no
BaseQuantities - CrossSectionArea: 0.00191 m2; NetWeight: 0 kg; GrossWeight: 0 kg
Name | Repère de pièce = Repère d'assemblage = Reference | Longueur (mm) = Length (mm) | OuterSurfaceArea (m2) = GrossSurfaceArea (m2) | NetVolume (m3) | GrossVolume (m3)
ATTACHE | A43 | 200 | 0.0782 | 0.00038 | 0.000382
ATTACHE | A42 | 200 | 0.0782 | 0.00038 | 0.000382
2 x ATTACHE | A41 | 120 | 0.04692 | 0.000228 | 0.0002292
2 x ATTACHE | A40 | 120 | 0.04692 | 0.000228 | 0.0002292
28 x ATTACHE | A38 | 120 | 0.04692 | 0.000228 | 0.0002292
6 x ATTACHE | A39 | 120 | 0.04692 | 0.000228 | 0.0002292

# IfcMember: L200*100*10 (78)
In: Undefined
Description: L200*100*10; Material: Undefined/S235-E24
Tekla Commun - Phase: 1; Profil: L200*100*10; Nom: ATTACHE; sets with these values: 2
Tekla Quantités - Poids: 0 kg; Volume: 0 m3; Surface supérieure totale: 0 m2; Surface par tonne: 0 m2; Hauteur: 200 mm; sets with these values: 2
Pset_MemberCommon - LoadBearing: no
BaseQuantities - CrossSectionArea: 0.00292 m2; NetWeight: 0 kg; GrossWeight: 0 kg
Name | Repère de pièce = Reference | Repère d'assemblage | Surface nette (m2) | Largeur (mm) | Longueur (mm) = Length (mm) | OuterSurfaceArea (m2) = GrossSurfaceArea (m2) | NetVolume (m3) | GrossVolume (m3)
4 x ATTACHE | A54 | A54 | 0.1 | 70 | 120 | 0.07044 | 0.000312 | 0.0003504
32 x ATTACHE | A53 | A53 | 0.1 | 100 | 120 | 0.07044 | 0.000348 | 0.0003504
2 x ATTACHE | A58 | A58 | 0.1 | 100 | 200 | 0.1174 | 0.00058 | 0.000584
2 x ATTACHE | A59 | A59 | 0.1 | 100 | 200 | 0.1174 | 0.00058 | 0.000584
ATTACHE | A61 | A61 | 0 | 70 | 60 | 0.03522 | 0.000156 | 0.0001752
15 x ATTACHE | A60 | A60 | 0 | 100 | 60 | 0.03522 | 0.000174 | 0.0001752
18 x ATTACHE | A55 | A55 | 0.1 | 100 | 120 | 0.07044 | 0.000348 | 0.0003504
4 x ATTACHE | A53 | A53(?) | 0.1 | 100 | 120 | 0.07044 | 0.000348 | 0.0003504

# IfcMember: L40*4 (8)
In: Undefined
Description: L40*4; Material: Undefined/S235-E24
Tekla Commun - Profil: L40*4; sets with these values: 2
Tekla Quantités - Poids: 0 kg; Volume: 0 m3; Surface supérieure totale: 0 m2; Surface par tonne: 0 m2; Hauteur: 40 mm; Largeur: 40 mm; sets with these values: 2
Pset_MemberCommon - LoadBearing: no
BaseQuantities - CrossSectionArea: 0.000308 m2; NetWeight: 0 kg; GrossWeight: 0 kg
Name | Repère de pièce = Repère d'assemblage = Reference | Phase | Nom | Surface nette (m2) | Longueur (mm) | Length (mm) | OuterSurfaceArea (m2) = GrossSurfaceArea (m2) | NetVolume (m3) | GrossVolume (m3)
2 x STABILITE | S29 | 1 | STABILITE | 0.1 | 688.9 | 688.884 | 0.106777 | 0.000209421 | 0.000212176
2 x STABILITE | S28 | 1 | STABILITE | 0.1 | 757.5 | 757.453 | 0.117405 | 0.000230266 | 0.000233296
2 x STABILITE | S27 | 1 | STABILITE | 0.1 | 835.6 | 835.634 | 0.129523 | 0.000254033 | 0.000257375
2 x STABILTE | S14 | 2 | STABILTE | 0.6 | 3982 | 3982 | 0.61721 | 0.00121136 | 0.00122646 | Tekla Commun - Finition: GALVA

# IfcMember: L60*6 (36)
In: Undefined
Description: L60*6; Material: Undefined/S235-E24
Tekla Quantités - Poids: 0 kg; Volume: 0 m3; Surface supérieure totale: 0 m2; Surface par tonne: 0 m2; Surface nette: 0 m2; Hauteur: 60 mm; Largeur: 60 mm; sets with these values: 2
Tekla Commun - Phase: 1; Profil: L60*6; Nom: ATTACHE; sets with these values: 2
Pset_MemberCommon - LoadBearing: no
BaseQuantities - CrossSectionArea: 0.000691 m2; NetWeight: 0 kg; GrossWeight: 0 kg
Name | Longueur (mm) = Length (mm) | Repère de pièce = Repère d'assemblage = Reference | OuterSurfaceArea (m2) = GrossSurfaceArea (m2) | NetVolume (m3) | GrossVolume (m3)
24 x ATTACHE | 180 | A28 | 0.04194 | 0.00012312 | 0.00012438
12 x ATTACHE | 150 | A27 | 0.03495 | 0.0001026 | 0.00010365

# IfcMember: L70*7 (3)
In: Undefined
Description: L70*7; Material: Undefined/S235-E24
Tekla Commun - Phase: 1; Profil: L70*7; Nom: FEUILLURE; sets with these values: 2
Tekla Quantités - Poids: 0 kg; Volume: 0 m3; Surface supérieure totale: 0 m2; Surface par tonne: 0 m2; Hauteur: 70 mm; Largeur: 70 mm; sets with these values: 2
Pset_MemberCommon - LoadBearing: no
BaseQuantities - CrossSectionArea: 0.00094 m2; NetWeight: 0 kg; GrossWeight: 0 kg
Name | Repère de pièce = Repère d'assemblage = Reference | Surface nette (m2) | Longueur (mm) = Length (mm) | OuterSurfaceArea (m2) = GrossSurfaceArea (m2) | NetVolume (m3) | GrossVolume (m3)
FEUILLURE | F20 | 1.5 | 5450 | 1.4824 | 0.00507395 | 0.005123
FEUILLURE | F19 | 2 | 7015 | 1.90808 | 0.00653097 | 0.0065941
FEUILLURE | F16 | 2.4 | 8700 | 2.3664 | 0.0080997 | 0.008178

# IfcMember: PL10*100 (9)
In: Undefined
Description: PL10*100; Material: Undefined/S235-E24
Tekla Commun - Repère de pièce: 271; Phase: 1; Profil: PL10*100; Nom: PLATINE; sets with these values: 2
Tekla Quantités - Poids: 0 kg; Volume: 0 m3; Surface supérieure totale: 0 m2; Surface par tonne: 0 m2; Surface nette: 0 m2; Hauteur: 100 mm; Largeur: 10 mm; Longueur: 210 mm; sets with these values: 2
Pset_MemberCommon - LoadBearing: no; Reference: 271
BaseQuantities - Length: 210 mm; OuterSurfaceArea: 0.0482 m2; GrossSurfaceArea: 0.0482 m2; CrossSectionArea: 0.001 m2; NetVolume: 0.00021 m3; GrossVolume: 0.00021 m3; NetWeight: 0 kg; GrossWeight: 0 kg
Name | Repère d'assemblage
3 x PLATINE | S22
3 x PLATINE | S21
3 x PLATINE | S20

# IfcMember: PL10*60 (8)
In: Undefined
Description: PL10*60; Material: Undefined/S235-E24
Tekla Quantités - Poids: 0 kg; Volume: 0 m3; Surface supérieure totale: 0 m2; Surface par tonne: 0 m2; Surface nette: 0 m2; Hauteur: 60 mm; Largeur: 10 mm; Longueur: 130 mm; sets with these values: 2
Tekla Commun - Finition: GALVA; Phase: 3; Profil: PL10*60; Nom: PLATINE; sets with these values: 2
Pset_MemberCommon - LoadBearing: no
BaseQuantities - Length: 130 mm; OuterSurfaceArea: 0.0194 m2; GrossSurfaceArea: 0.0194 m2; CrossSectionArea: 0.0006 m2; NetVolume: 0.000078 m3; GrossVolume: 0.000078 m3; NetWeight: 0 kg; GrossWeight: 0 kg
Name | Repère de pièce = Reference | Repère d'assemblage
PLATINE | 525 | GC12
PLATINE | 525 | GC8
3 x PLATINE | 525 | GC3
2 x PLATINE | 525 | GC2
PLATINE | 318 | GC1

# IfcMember: PL15*103.5 (8)
In: Undefined
Description: PL15*103.5; Material: Undefined/S235-E24
Tekla Commun - Repère de pièce: 27; Phase: 1; Profil: PL15*103.5; Nom: PLATINE; sets with these values: 2
Tekla Quantités - Poids: 0 kg; Volume: 0 m3; Surface supérieure totale: 0 m2; Surface par tonne: 0 m2; Surface nette: 0.1 m2; Hauteur: 103.5 mm; Largeur: 15 mm; Longueur: 226.7 mm; sets with these values: 2
Pset_MemberCommon - LoadBearing: no; Reference: 27
BaseQuantities - CrossSectionArea: 0.0015525 m2; NetWeight: 0 kg; GrossWeight: 0 kg
Name | Repère d'assemblage | Length (mm) | OuterSurfaceArea (m2) | GrossSurfaceArea (m2) | NetVolume (m3) | GrossVolume (m3)
2 x PLATINE | PT10 | 226.683 | 0.0562532 | 0.0568289 | 0.000348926 | 0.000351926
2 x PLATINE | PT10 | 226.686 | 0.0562539 | 0.0568297 | 0.000348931 | 0.000351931
2 x PLATINE | PT12 | 226.683 | 0.0562532 | 0.0568289 | 0.000348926 | 0.000351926
2 x PLATINE | PT12 | 226.686 | 0.0562539 | 0.0568297 | 0.000348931 | 0.000351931

# IfcMember: PL200*6 (2)
In: Undefined
Description: PL200*6; Material: Undefined/S235-E24
Tekla Commun - Finition: GALVA; Repère de pièce: GC0; Repère d'assemblage: GC0(?); Phase: 3; Profil: PL200*6; Nom: CACHE VIDE; sets with these values: 2
Tekla Quantités - Poids: 0 kg; Volume: 0 m3; Surface supérieure totale: 0 m2; Surface par tonne: 0 m2; Surface nette: 0.4 m2; Hauteur: 200 mm; Largeur: 6 mm; Longueur: 900 mm; sets with these values: 2
Pset_MemberCommon - LoadBearing: no; Reference: GC0
BaseQuantities - Length: 900 mm; OuterSurfaceArea: 0.3732 m2; GrossSurfaceArea: 0.3732 m2; CrossSectionArea: 0.0012 m2; NetVolume: 0.00108 m3; GrossVolume: 0.00108 m3; NetWeight: 0 kg; GrossWeight: 0 kg

# IfcMember: TUBE-21.3*2 (12)
In: Undefined
Description: TUBE-21.3*2; Material: Undefined/S235-E24
Tekla Commun - Finition: GALVA; Phase: 3; Profil: TUBE-21.3*2; Nom: LISSE; sets with these values: 2
Tekla Quantités - Poids: 0 kg; Volume: 0 m3; Surface supérieure totale: 0 m2; Surface par tonne: 0 m2; Surface nette: 0.1 m2; Hauteur: 21.3 mm; Largeur: 21.3 mm; sets with these values: 2
Pset_MemberCommon - LoadBearing: no
BaseQuantities - GrossSurfaceArea: 0 m2; CrossSectionArea: 0.000121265 m2; NetWeight: 0 kg; GrossWeight: 0 kg
Name | Repère de pièce = Reference | Repère d'assemblage | Longueur (mm) | Length (mm) | OuterSurfaceArea (m2) | NetVolume (m3) | GrossVolume (m3)
2 x LISSE | 644 | GC0(?) | 788.6 | 788.637 | 0.051493 | 0.0000898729 | 0.0000956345
LISSE | 625 | GC12 | 943.8 | 943.779 | 0.0617562 | 0.000107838 | 0.000114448
LISSE | 624 | GC12 | 987.3 | 987.296 | 0.0646227 | 0.000112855 | 0.000119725
LISSE | 625 | GC8 | 943.8 | 943.779 | 0.0617562 | 0.000107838 | 0.000114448
LISSE | 624 | GC8 | 987.3 | 987.296 | 0.0646227 | 0.000112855 | 0.000119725
2 x LISSE | 620 | GC2 | 1389.1 | 1389.13 | 0.0910763 | 0.000159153 | 0.000168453
3 x LISSE | 620 | GC3 | 1389.1 | 1389.13 | 0.0910763 | 0.000159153 | 0.000168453
LISSE | 620 | GC1 | 1389.1 | 1389.13 | 0.0910763 | 0.000159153 | 0.000168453

# IfcMember: TUBE-60.3*3.2 (2)
In: Undefined
Description: TUBE-60.3*3.2; Material: Undefined/S235-E24
Tekla Commun - Finition: GALVA; Repère de pièce: 196; Repère d'assemblage: B14; Phase: 2; Profil: TUBE-60.3*3.2; Nom: BUTON; sets with these values: 2
Tekla Quantités - Poids: 0 kg; Volume: 0 m3; Surface supérieure totale: 0 m2; Surface par tonne: 0 m2; Surface nette: 0.4 m2; Hauteur: 60.3 mm; Largeur: 60.3 mm; Longueur: 2230 mm; sets with these values: 2
Pset_MemberCommon - LoadBearing: no; Reference: 196
BaseQuantities - Length: 2230 mm; OuterSurfaceArea: 0.417322 m2; GrossSurfaceArea: 0 m2; CrossSectionArea: 0.000574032 m2; NetVolume: 0.00123369 m3; GrossVolume: 0.00128009 m3; NetWeight: 0 kg; GrossWeight: 0 kg

# IfcMember: UPN260 (14)
In: Undefined
Description: UPN260; Material: Undefined/S275-E28
Tekla Commun - Finition: GALVA; Phase: 3; Profil: UPN260; Nom: LIMON; sets with these values: 2
Tekla Quantités - Poids: 0 kg; Volume: 0 m3; Surface supérieure totale: 0 m2; Surface par tonne: 0 m2; Hauteur: 260 mm; Largeur: 90 mm; sets with these values: 2
Pset_MemberCommon - LoadBearing: no
BaseQuantities - CrossSectionArea: 0.00483 m2; NetWeight: 0 kg; GrossWeight: 0 kg
Name | Repère de pièce = Reference | Repère d'assemblage | Surface nette (m2) | Longueur (mm) | Length (mm) | OuterSurfaceArea (m2) = GrossSurfaceArea (m2) | NetVolume (m3) | GrossVolume (m3)
3 x LIMON | 608 | L90 | 1 | 1346.7 | 1346.65 | 1.12041 | 0.0057237 | 0.00650432
3 x LIMON | 607 | L89 | 1 | 1346.7 | 1346.65 | 1.12041 | 0.0057237 | 0.00650432
LIMON | 536 | L33(?) | 0.8 | 1023.8 | 1023.8 | 0.851798 | 0.00444587 | 0.00494493
LIMON | 535 | L63 | 0.8 | 1023.8 | 1023.8 | 0.851799 | 0.00444587 | 0.00494494
LIMON | 547 | L33(?) | 0.7 | 1007.9 | 1007.91 | 0.838578 | 0.00412697 | 0.00486819
LIMON | 546 | L63 | 0.7 | 1007.9 | 1007.91 | 0.838578 | 0.00412697 | 0.00486819
LIMON | 536 | L5(?) | 0.8 | 1023.8 | 1023.8 | 0.851798 | 0.00444587 | 0.00494493
LIMON | 535 | L75(?) | 0.8 | 1023.8 | 1023.8 | 0.851799 | 0.00444587 | 0.00494494
LIMON | 547 | L5(?) | 0.7 | 1007.9 | 1007.91 | 0.838578 | 0.00412697 | 0.00486819
LIMON | 546 | L75(?) | 0.7 | 1007.9 | 1007.91 | 0.838578 | 0.00412697 | 0.00486819

# IfcMember: UPN80 (36)
In: Undefined
Description: UPN80; Material: Undefined/S275-E28
Tekla Commun - Phase: 1; Profil: UPN80; Nom: DIAGONALE; sets with these values: 2
Tekla Quantités - Poids: 0 kg; Volume: 0 m3; Surface supérieure totale: 0 m2; Surface par tonne: 0 m2; Hauteur: 80 mm; Largeur: 45 mm; sets with these values: 2
Pset_MemberCommon - LoadBearing: no
BaseQuantities - CrossSectionArea: 0.0011 m2; NetWeight: 0 kg; GrossWeight: 0 kg
Name | Repère de pièce = Repère d'assemblage = Reference | Surface nette (m2) | Longueur (mm) | Length (mm) | OuterSurfaceArea (m2) = GrossSurfaceArea (m2) | NetVolume (m3) | GrossVolume (m3)
6 x DIAGONALE | D1 | 1.5 | 4703.5 | 4703.55 | 1.47221 | 0.00511226 | 0.0051739
2 x DIAGONALE | D1 | 1.5 | 4703.5 | 4703.54 | 1.47221 | 0.00511226 | 0.0051739
8 x DIAGONALE | D2 | 1.7 | 5260.1 | 5260.1 | 1.64641 | 0.00571628 | 0.00578611
8 x DIAGONALE | D3 | 1.9 | 5863.9 | 5863.9 | 1.8354 | 0.00637266 | 0.00645029
2 x DIAGONALE | D7 | 1.4 | 4211.2 | 4211.19 | 1.3181 | 0.00457791 | 0.00463231
2 x DIAGONALE | D6 | 1.4 | 4426.2 | 4426.2 | 1.3854 | 0.00481235 | 0.00486882
2 x DIAGONALE | D8 | 1.1 | 3481 | 3480.99 | 1.08955 | 0.00378437 | 0.00382909
2 x DIAGONALE | D5 | 1.1 | 3480 | 3480 | 1.08924 | 0.00378437 | 0.00382799
2 x DIAGONALE | D9 | 1.3 | 3919.2 | 3919.24 | 1.22672 | 0.00426216 | 0.00431117
2 x DIAGONALE | D4 | 1.2 | 3731.1 | 3731.05 | 1.16782 | 0.00405792 | 0.00410416

# IfcPlate: PL2*20, GOUSSET
In: Undefined
Description: PL2*20; Material: STEEL/S235JR
Tekla Commun - Repère de pièce: G0; Repère d'assemblage: G0(?); Phase: 1; Profil: PL2*20; Nom: GOUSSET; sets with these values: 2
Tekla Quantités - Poids: 0 kg; Volume: 0 m3; Surface supérieure totale: 0 m2; Surface par tonne: 0 m2; Surface nette: 0 m2; Hauteur: 20 mm; Largeur: 2 mm; Longueur: 20 mm; sets with these values: 2
Pset_PlateCommon - LoadBearing: no; Reference: G0
BaseQuantities - Width: 20 mm; NetArea: 0.00096 m2; GrossArea: 0.0004 m2; CrossSectionArea: 0.000004 m2; NetVolume: 8e-07 m3; GrossVolume: 8e-07 m3

# IfcPlate: TOLE10*100 (3)
In: Undefined
Description: TOLE10*100; Material: Undefined/S235-E24
Tekla Commun - Repère d'assemblage: PT10; Phase: 1; Profil: TOLE10*100; Nom: RAIDISSEUR; sets with these values: 2
Tekla Quantités - Poids: 0 kg; Volume: 0 m3; Surface par tonne: 0 m2; Surface nette: 0.1 m2; Hauteur: 100 mm; Largeur: 10 mm; sets with these values: 2
Pset_PlateCommon - LoadBearing: no
BaseQuantities - Width: 100 mm; CrossSectionArea: 0.0001 m2
Name | Repère de pièce = Reference | Surface supérieure totale (m2) | Longueur (mm) | NetArea (m2) | GrossArea (m2) | NetVolume (m3) = GrossVolume (m3)
RAIDISSEUR | 360 | 0 | 540 | 0.119766 | 0.054 | 0.000536
2 x RAIDISSEUR | 359 | 0.1 | 560 | 0.123049 | 0.056 | 0.000551

# IfcSlab: 200*13930, DALLE
In: Undefined
Description: 200*13930; PredefinedType: FLOOR; Material: CONCRETE/C25/30
Tekla Commun - Repère de pièce: Da6; Repère d'assemblage: Da6; Phase: 1; Profil: 200*13930; Nom: DALLE; sets with these values: 2
Tekla Quantités - Poids: 233208 kg; Volume: 97.2 m3; Surface supérieure totale: 485.8 m2; Surface par tonne: 4.3 m2; Surface nette: 996.8 m2; Hauteur: 13930 mm; Largeur: 200 mm; Longueur: 49248 mm; sets with these values: 2
Pset_SlabCommon - LoadBearing: no; Reference: Da6
BaseQuantities - Width: 200 mm; NetVolume: 97.1699 m3; NetArea: 485.85 m2; NetWeight: 233208 kg

# IfcSlab: 200*15570, DALLE
In: Undefined
Description: 200*15570; PredefinedType: FLOOR; Material: CONCRETE/C25/30
Tekla Commun - Repère de pièce: Da7; Repère d'assemblage: Da7; Phase: 1; Profil: 200*15570; Nom: DALLE; sets with these values: 2
Tekla Quantités - Poids: 298981 kg; Volume: 124.6 m3; Surface supérieure totale: 622.9 m2; Surface par tonne: 4.2 m2; Surface nette: 1268 m2; Hauteur: 15570 mm; Largeur: 200 mm; Longueur: 40005 mm; sets with these values: 2
Pset_SlabCommon - LoadBearing: no; Reference: Da7
BaseQuantities - Width: 200 mm; NetVolume: 124.576 m3; NetArea: 622.878 m2; NetWeight: 298981 kg

# IfcSlab: 200*2425, DALLE
In: Undefined
Description: 200*2425; PredefinedType: FLOOR; Material: CONCRETE/C25/30
Tekla Commun - Repère de pièce: Da3; Repère d'assemblage: Da3; Phase: 1; Profil: 200*2425; Nom: DALLE; sets with these values: 2
Tekla Quantités - Poids: 2217.3 kg; Volume: 0.9 m3; Surface supérieure totale: 0 m2; Surface par tonne: 5.6 m2; Surface nette: 12.3 m2; Hauteur: 2425.4 mm; Largeur: 200 mm; Longueur: 4933.1 mm; sets with these values: 2
Pset_SlabCommon - LoadBearing: no; Reference: Da3
BaseQuantities - Width: 200 mm; NetVolume: 0.923859 m3; NetArea: 0 m2; NetWeight: 2217.26 kg

# IfcSlab: 200*3249, DALLE
In: Undefined
Description: 200*3249; PredefinedType: FLOOR; Material: CONCRETE/C25/30
Tekla Commun - Repère de pièce: Da2; Repère d'assemblage: Da2; Phase: 1; Profil: 200*3249; Nom: DALLE; sets with these values: 2
Tekla Quantités - Poids: 4030.2 kg; Volume: 1.7 m3; Surface supérieure totale: 0 m2; Surface par tonne: 5.2 m2; Surface nette: 20.8 m2; Hauteur: 3249 mm; Largeur: 200 mm; Longueur: 6269.9 mm; sets with these values: 2
Pset_SlabCommon - LoadBearing: no; Reference: Da2
BaseQuantities - Width: 200 mm; NetVolume: 1.67926 m3; NetArea: 0 m2; NetWeight: 4030.23 kg

# IfcSlab: 200*4052, DALLE
In: Undefined
Description: 200*4052; PredefinedType: FLOOR; Material: CONCRETE/C25/30
Tekla Commun - Repère de pièce: Da1; Repère d'assemblage: Da1; Phase: 1; Profil: 200*4052; Nom: DALLE; sets with these values: 2
Tekla Quantités - Poids: 6459.2 kg; Volume: 2.7 m3; Surface supérieure totale: 0 m2; Surface par tonne: 5 m2; Surface nette: 32.3 m2; Hauteur: 4052 mm; Largeur: 200 mm; Longueur: 7745.8 mm; sets with these values: 2
Pset_SlabCommon - LoadBearing: no; Reference: Da1
BaseQuantities - Width: 200 mm; NetVolume: 2.69133 m3; NetArea: 0 m2; NetWeight: 6459.18 kg

# IfcSlab: 200*5000, DALLE
In: Undefined
Description: 200*5000; PredefinedType: FLOOR; Material: CONCRETE/C25/30
Tekla Commun - Repère de pièce: Da8; Repère d'assemblage: Da8; Phase: 1; Profil: 200*5000; Nom: DALLE; sets with these values: 2
Tekla Quantités - Poids: 22200 kg; Volume: 9.2 m3; Surface supérieure totale: 46.2 m2; Surface par tonne: 4.4 m2; Surface nette: 98.2 m2; Hauteur: 5000 mm; Largeur: 200 mm; Longueur: 9250 mm; sets with these values: 2
Pset_SlabCommon - LoadBearing: no; Reference: Da8
BaseQuantities - Width: 200 mm; NetVolume: 9.25 m3; NetArea: 46.25 m2; NetWeight: 22200 kg

# IfcSlab: 220*9250, DALLE
In: Undefined
Description: 220*9250; PredefinedType: FLOOR; Material: CONCRETE/C25/30
Tekla Commun - Repère de pièce: Da5; Repère d'assemblage: Da5; Phase: 1; Profil: 220*9250; Nom: DALLE; sets with these values: 2
Tekla Quantités - Poids: 142505 kg; Volume: 59.4 m3; Surface supérieure totale: 269.9 m2; Surface par tonne: 3.9 m2; Surface nette: 556.7 m2; Hauteur: 9250 mm; Largeur: 220 mm; Longueur: 29178 mm; sets with these values: 2
Pset_SlabCommon - LoadBearing: no; Reference: Da5
BaseQuantities - Width: 220 mm; NetVolume: 59.3772 m3; NetArea: 269.897 m2; NetWeight: 142505 kg

# IfcSlab: 230*9250 (2)
In: Undefined
Description: 230*9250; PredefinedType: FLOOR; Material: CONCRETE/C25/30
Tekla Commun - Phase: 1; Profil: 230*9250; Nom: DALLE; sets with these values: 2
Tekla Quantités - Hauteur: 9250 mm; Largeur: 230 mm; sets with these values: 2
Pset_SlabCommon - LoadBearing: no
BaseQuantities - Width: 230 mm
Name | Repère de pièce = Repère d'assemblage = Reference | Poids (kg) = NetWeight (kg) | Volume (m3) | Surface supérieure totale (m2) | Surface par tonne (m2) | Surface nette (m2) | Longueur (mm) | NetVolume (m3) | NetArea (m2)
DALLE | Da9 | 148983 | 62.1 | 269.9 | 3.7 | 557.5 | 29178 | 62.0762 | 269.897
DALLE | Da4 | 71045.8 | 29.6 | 128.7 | 3.8 | 268.1 | 14279.8 | 29.6024 | 128.706
